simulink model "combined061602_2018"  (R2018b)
settings: Solver=ode5  StartTime=0.0  StopTime=inf  FixedStep=1e-5  RelTol=1e-3
libraries: powerlib x156, powerlib_meascontrol x64, simulink x32, dspsigops x2
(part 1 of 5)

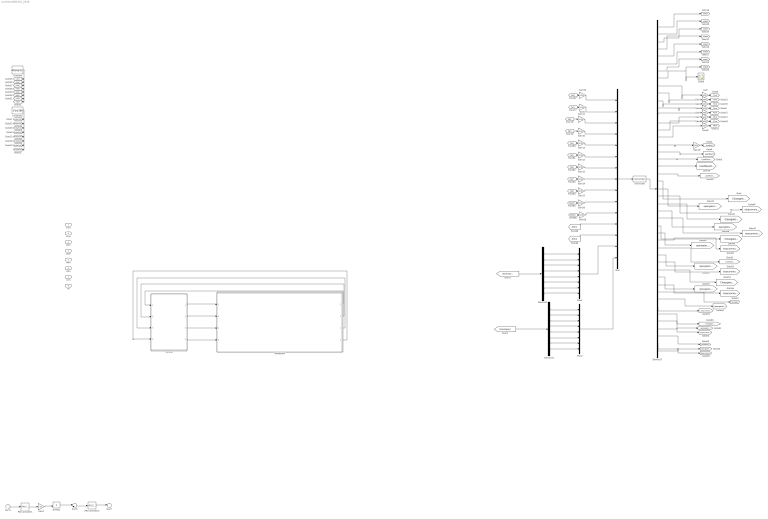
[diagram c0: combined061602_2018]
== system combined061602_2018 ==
  P1in : Inport
  P2in : Inport  Port=2
  Q1in : Inport  Port=3
  Q2in : Inport  Port=4
  vain : Inport  Port=5
  vbin : Inport  Port=6
  vcin : Inport  Port=7
  fin : Inport  Port=8
  Constant : Constant  Value=400/sqrt(3)
  Constant1 : Constant  Value=1*pi/180
  Control : Subsystem
  Demux15 : Demux  Outputs=8
  Demux16 : Demux  Outputs=8
  Demux17 : Demux  Outputs=45
  Divide1 : Product  Commented=on  Inputs=/*
  Gain{,3..9,19} (9 alike) : Gain  Gain=1000
  Gain1 : Gain  Commented=on  Gain=-2/3
  Gain{2,10..18,30} (11 alike) : Gain  Gain=1/1000  OutDataTypeStr=double
  Mux : Mux  Inputs=15
  Mux1 : Mux  Inputs=8
  Mux2 : Mux  Inputs=8
  PID Controller1 : simulink/Continuous/PID Controller  Commented=on  Controller=PI  Form=Parallel  TimeDomain=Continuous-time  SampleTime=-1  IntegratorMethod=Forward Euler  FilterMethod=Forward Euler  ControllerParametersSource=internal  P=1  I=1  D=0  UseFilter=on  N=100  TunerSelectOption=Transfer Function Based (PID Tuner App)  InitialConditionSource=internal  InitialConditionForIntegrator=0  InitialConditionForFilter=0  DifferentiatorICPrevScaledInput=0  ExternalReset=none  TrackingMode=off  Kt=1  LimitOutput=off  UpperSaturationLimit=inf  LowerSaturationLimit=-inf  LinearizeAsGain=on  AntiWindupMode=none  Kb=1  POutMin=[]  POutMax=[]  IOutMin=[]  IOutMax=[]  DOutMin=[]  DOutMax=[]  NOutMin=[]  NOutMax=[]  SumOutMin=[]  SumOutMax=[]  SaturationOutMin=[]  SaturationOutMax=[]  PParamMin=[]  PParamMax=[]  IParamMin=[]  IParamMax=[]  DParamMin=[]  DParamMax=[]  NParamMin=[]  NParamMax=[]  KbParamMin=[]  KbParamMax=[]  KtParamMin=[]  KtParamMax=[]  KbOutMin=[]  KbOutMax=[]  KtOutMin=[]  KtOutMax=[]  IntegratorOutMin=[]  IntegratorOutMax=[]  FilterOutMin=[]  FilterOutMax=[]  SumI1OutMin=[]  SumI1OutMax=[]  SumI2OutMin=[]  SumI2OutMax=[]  SumI3OutMin=[]  SumI3OutMax=[]  SumI4OutMin=[]  SumI4OutMax=[]  SumDOutMin=[]  SumDOutMax=[]  DifferentiatorOutMin=[]  DifferentiatorOutMax=[]  FilterDiffOutCoefMin=[]  FilterDiffOutCoefMax=[]  ReciprocalOutMin=[]  ReciprocalOutMax=[]  SumDenOutMin=[]  SumDenOutMax=[]  SumNumOutMin=[]  SumNumOutMax=[]  DivideOutMin=[]  DivideOutMax=[]  IntegratorContinuousStateAttributes=''  IntegratorStateMustResolveToSignalObject=off  IntegratorRTWStateStorageClass=Auto  FilterContinuousStateAttributes=''  FilterStateMustResolveToSignalObject=off  FilterRTWStateStorageClass=Auto  ParallelPVariant=InternalParameters  IdealPVariant=Disabled  IVariant=InternalParameters  DVariant=Disabled  IntegratorVariant=Continuous  SatVariant=Disabled  AWVariant=Passthrough  PCopyVariant=Disabled  TRVariant=Disabled  FdbkBlocksVariant=Forward  IdealPFdbkVariant=Disabled  SatFdbkVariant=Disabled  DerivativeFilterVariant=Disabled  NVariant=Disabled  NCopyVariant=Disabled_SignalSpec  FilterICVariant=Disabled  IntegratorICVariant=InternalICs  ExternalResetVariant=Disabled  TRSumVariant=Passthrough  SumFdbkVariant=Disabled  SumVariant=Sum_PI
  PID Controller3 : simulink/Continuous/PID Controller  Commented=on  Controller=PI  Form=Parallel  TimeDomain=Continuous-time  SampleTime=-1  IntegratorMethod=Forward Euler  FilterMethod=Forward Euler  ControllerParametersSource=internal  P=1  I=1  D=0  UseFilter=on  N=100  TunerSelectOption=Transfer Function Based (PID Tuner App)  InitialConditionSource=internal  InitialConditionForIntegrator=0  InitialConditionForFilter=0  DifferentiatorICPrevScaledInput=0  ExternalReset=none  TrackingMode=off  Kt=1  LimitOutput=off  UpperSaturationLimit=inf  LowerSaturationLimit=-inf  LinearizeAsGain=on  AntiWindupMode=none  Kb=1  POutMin=[]  POutMax=[]  IOutMin=[]  IOutMax=[]  DOutMin=[]  DOutMax=[]  NOutMin=[]  NOutMax=[]  SumOutMin=[]  SumOutMax=[]  SaturationOutMin=[]  SaturationOutMax=[]  PParamMin=[]  PParamMax=[]  IParamMin=[]  IParamMax=[]  DParamMin=[]  DParamMax=[]  NParamMin=[]  NParamMax=[]  KbParamMin=[]  KbParamMax=[]  KtParamMin=[]  KtParamMax=[]  KbOutMin=[]  KbOutMax=[]  KtOutMin=[]  KtOutMax=[]  IntegratorOutMin=[]  IntegratorOutMax=[]  FilterOutMin=[]  FilterOutMax=[]  SumI1OutMin=[]  SumI1OutMax=[]  SumI2OutMin=[]  SumI2OutMax=[]  SumI3OutMin=[]  SumI3OutMax=[]  SumI4OutMin=[]  SumI4OutMax=[]  SumDOutMin=[]  SumDOutMax=[]  DifferentiatorOutMin=[]  DifferentiatorOutMax=[]  FilterDiffOutCoefMin=[]  FilterDiffOutCoefMax=[]  ReciprocalOutMin=[]  ReciprocalOutMax=[]  SumDenOutMin=[]  SumDenOutMax=[]  SumNumOutMin=[]  SumNumOutMax=[]  DivideOutMin=[]  DivideOutMax=[]  IntegratorContinuousStateAttributes=''  IntegratorStateMustResolveToSignalObject=off  IntegratorRTWStateStorageClass=Auto  FilterContinuousStateAttributes=''  FilterStateMustResolveToSignalObject=off  FilterRTWStateStorageClass=Auto  ParallelPVariant=InternalParameters  IdealPVariant=Disabled  IVariant=InternalParameters  DVariant=Disabled  IntegratorVariant=Continuous  SatVariant=Disabled  AWVariant=Passthrough  PCopyVariant=Disabled  TRVariant=Disabled  FdbkBlocksVariant=Forward  IdealPFdbkVariant=Disabled  SatFdbkVariant=Disabled  DerivativeFilterVariant=Disabled  NVariant=Disabled  NCopyVariant=Disabled_SignalSpec  FilterICVariant=Disabled  IntegratorICVariant=InternalICs  ExternalResetVariant=Disabled  TRSumVariant=Passthrough  SumFdbkVariant=Disabled  SumVariant=Sum_PI
  S-Function : S-Function  FunctionName=modbusComPLCC  SFunctionDeploymentMode=off  EnableBusSupport=off
  Scope : Scope
  Subsystem : Subsystem
  Sum1 : Sum  Commented=on  Inputs=|+-
  Sum5 : Sum  Commented=on  Inputs=|+-
  Sum7 : Sum  Commented=on  Inputs=|++
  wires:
  Demux17/5 -> [enble5]
  Demux17/6 -> [enble6]
  Constant/1 -> [v1ref], [v2ref], [v3ref], [v4ref], [v5ref], [v6ref], [v7ref], [v8ref]
  Constant1/1 -> [theta1ref], [theta2ref], [theta3ref], [theta4ref], [theta5ref], [theta6ref], [theta8ref], [theta7ref]
  Demux17/4 -> [enble4]
  Sum5/1 -> PID Controller3/1
  Demux17/2 -> [enble2]
  Demux17/8 -> Scope/1, [enble8]
  Divide1/1 -> Sum5/1
  Demux17/3 -> [enble3]
  Demux17/1 -> [enble1]
  PID Controller3/1 -> Sum7/1
  Gain1/1 -> Divide1/2
  Sum1/1 -> PID Controller1/1
  PID Controller1/1 -> Gain1/1
  Q2in/1 -> ?
  P2in/1 -> ?
  Q1in/1 -> ?
  P1in/1 -> ?
  Control/1(P1out) -> Subsystem/1(P1ref2)
  Control/2(Q1out) -> Subsystem/2(Q1ref1)
  Control/3(P2out) -> Subsystem/3(P2ref)
  Control/4(Q2out) -> Subsystem/4(Q2ref)
  vain/1 -> ?
  vbin/1 -> ?
  fin/1 -> ?
  vcin/1 -> ?
  Subsystem/1(vaout) -> Control/1(vain)
  Subsystem/2(vbout) -> Control/2(vbin)
  Subsystem/3(vcout) -> Control/3(vcin)
  Subsystem/4(fout) -> Control/4(fin)
  Demux17/39 -> [stopcommand6]
  Demux17/37 -> [Closegatecommand6]
  Demux17/41 -> [opengatecommand7]
  Demux17/42 -> [stopcommand7]
  Demux17/40 -> [Closegatecommand7]
  [StartEnable] -> Demux15/1
  Demux16/2 -> Mux2/2
  Demux16/3 -> Mux2/3
  Demux16/1 -> Mux2/1
  Demux16/4 -> Mux2/4
  Demux16/5 -> Mux2/5
  Demux16/8 -> Mux2/8
  [RatedSpeed] -> Demux16/1
  Gain/1 -> [P1ref]
  Demux17/9 -> Gain/1
  Gain3/1 -> [P2ref]
  Gain4/1 -> [P3ref]
  Gain5/1 -> [P4ref]
  Gain6/1 -> [P5ref]
  Gain7/1 -> [P6ref]
  Gain8/1 -> [P7ref]
  Gain9/1 -> [P8ref]
  Demux17/16 -> Gain9/1
  Demux17/15 -> Gain8/1
  Demux17/14 -> Gain7/1
  Demux17/13 -> Gain6/1
  Demux17/12 -> Gain5/1
  Demux17/11 -> Gain4/1
  Demux17/10 -> Gain3/1
  [Pgt600] -> Gain18/1
  [Pgt400] -> Gain16/1
  [Pgt8] -> Gain17/1
  [Pgt7] -> Gain14/1
  [Pgt6] -> Gain15/1
  [Pgt5] -> Gain12/1
  [Pgt4] -> Gain13/1
  [Pgt3] -> Gain10/1
  [Pgt2] -> Gain11/1
  [Pgt1] -> Gain2/1
  [Pgt0] -> Gain30/1
  Gain30/1 -> Mux/1
  Gain2/1 -> Mux/2
  Gain11/1 -> Mux/3
  Gain10/1 -> Mux/4
  Gain13/1 -> Mux/5
  Gain12/1 -> Mux/6
  Gain15/1 -> Mux/7
  Gain14/1 -> Mux/8
  Gain17/1 -> Mux/9
  Gain16/1 -> Mux/10
  Gain18/1 -> Mux/11
  [SOC2] -> Mux/13
  [SOC1] -> Mux/12
  Mux1/1 -> Mux/14
  Mux2/1 -> Mux/15
  Mux/1 -> S-Function/1
  Demux17/43 -> [Closegatecommand8]
  Demux17/44 -> [opengatecommand8]
  Demux17/45 -> [stopcommand8]
  Demux17/38 -> [opengatecommand6]
  Demux17/34 -> [Closegatecommand5]
  Demux17/35 -> [opengatecommand5]
  Demux17/36 -> [stopcommand5]
  Demux17/32 -> [opengatecommand4]
  Demux17/31 -> [Closegatecommand4]
  Demux17/33 -> [stopcommand4]
  Demux17/29 -> [opengatecommand3]
  Demux17/28 -> [Closegatecommand3]
  Demux17/30 -> [stopcommand3]
  Demux17/25 -> [Closegatecommand2]
  Demux17/26 -> [opengatecommand2]
  Demux17/27 -> [stopcommand2]
  Demux17/23 -> [opengatecommand1]
  Demux17/24 -> [stopcommand1]
  Demux17/22 -> [Closegatecommand1]
  Demux17/17 -> Gain19/1
  Demux17/18 -> [LoadQset]
  Demux17/19 -> [LoadFactorySet]
  Demux17/20 -> [LoadSpeedSet]
  Demux17/21 -> [LoadTchangeSet]
  Demux17/7 -> [enble7]
  Demux16/6 -> Mux2/6
  Demux16/7 -> Mux2/7
  Demux15/1 -> Mux1/1
  Demux15/2 -> Mux1/2
  Demux15/3 -> Mux1/3
  Demux15/4 -> Mux1/4
  Demux15/5 -> Mux1/5
  Demux15/6 -> Mux1/6
  Demux15/7 -> Mux1/7
  Demux15/8 -> Mux1/8
  S-Function/1 -> Demux17/1
  Gain19/1 -> [LoadPset]

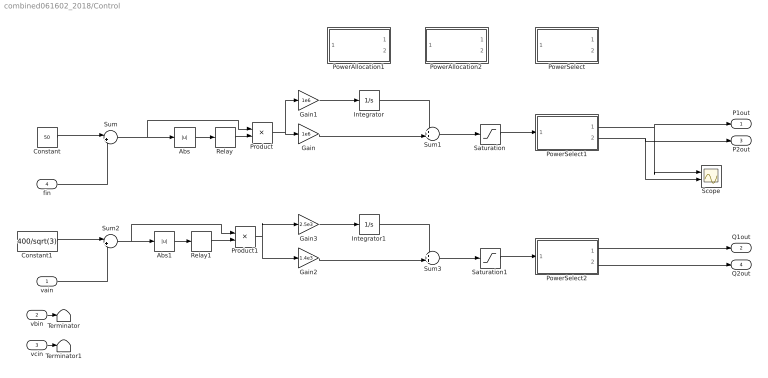
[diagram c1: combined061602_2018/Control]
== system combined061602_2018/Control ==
  vain : Inport
  vbin : Inport  Port=2
  vcin : Inport  Port=3
  fin : Inport  Port=4
  Abs : Abs
  Abs1 : Abs
  Constant : Constant  Value=50
  Constant1 : Constant  Value=400/sqrt(3)
  Gain : Gain  Gain=1e6
  Gain1 : Gain  Gain=1e6
  Gain2 : Gain  Gain=1.4e3
  Gain3 : Gain  Gain=2.5e3
  Integrator : Integrator
  Integrator1 : Integrator
  PowerAllocation1 : Subsystem  Commented=on
  PowerAllocation2 : Subsystem  Commented=on
  PowerSelect : Subsystem  Commented=on
  PowerSelect1 : Subsystem
  PowerSelect2 : Subsystem
  Product : Product
  Product1 : Product
  Relay : Relay  OnSwitchValue=0  OffSwitchValue=0
  Relay1 : Relay  OnSwitchValue=0  OffSwitchValue=0
  Saturation : Saturate  UpperLimit=1e6  LowerLimit=-1e6
  Saturation1 : Saturate  UpperLimit=5e5  LowerLimit=-5e5
  Scope : Scope  NumInputPorts=2
  Sum : Sum  Inputs=|+-
  Sum1 : Sum  Inputs=++|
  Sum2 : Sum  Inputs=|+-
  Sum3 : Sum  Inputs=++|
  Terminator : Terminator
  Terminator1 : Terminator
  P1out : Outport
  Q1out : Outport  Port=2
  P2out : Outport  Port=3
  Q2out : Outport  Port=4
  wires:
  PowerSelect2/1(P1) -> Q1out/1
  Integrator/1 -> Sum1/1
  PowerSelect1/1(P1) -> P1out/1, Scope/1
  Product1/1 -> Gain2/1, Gain3/1
  Integrator1/1 -> Sum3/1
  Gain3/1 -> Integrator1/1
  Sum1/1 -> Saturation/1
  Sum3/1 -> Saturation1/1
  Constant1/1 -> Sum2/1
  Gain1/1 -> Integrator/1
  Gain2/1 -> Sum3/2
  fin/1 -> Sum/2
  Saturation1/1 -> PowerSelect2/1(PAll)
  Gain/1 -> Sum1/2
  Product/1 -> Gain1/1, Gain/1
  vain/1 -> Sum2/2
  Saturation/1 -> PowerSelect1/1(PAll)
  vbin/1 -> Terminator/1
  vcin/1 -> Terminator1/1
  PowerSelect1/2(P2) -> P2out/1, Scope/2
  PowerSelect2/2(P2) -> Q2out/1
  Sum/1 -> Abs/1, Product/1
  Constant/1 -> Sum/1
  Relay/1 -> Product/2
  Abs/1 -> Relay/1
  Relay1/1 -> Product1/2
  Abs1/1 -> Relay1/1
  Sum2/1 -> Abs1/1, Product1/1

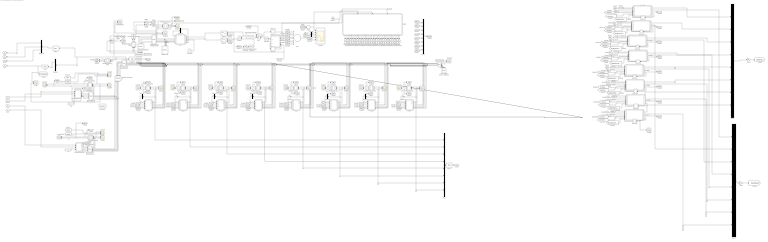
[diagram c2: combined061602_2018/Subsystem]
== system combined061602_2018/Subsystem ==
  P1ref2 : Inport
  Q1ref1 : Inport  Port=2
  P2ref : Inport  Port=3
  Q2ref : Inport  Port=4
  150kW Load : powerlib/Elements/Three-Phase Series RLC Load  LConnTagsString=A|B|C  Configuration=Y (grounded)  NominalVoltage=600  Vabc=[1e3 1e3 1e3]  Vabcp=[1e3 1e3 1e3]  NominalFrequency=50  UnbalancedPower=off  ActivePower=300e3  InductivePower=0  CapacitivePower=0  Pabc=[10e3 9e3 11e3]  QLabc=[100 90 110]  QCabc=[100 90 110]  Pabcp=[10e3 9e3 11e3]  QLabcp=[100 90 110]  QCabcp=[100 90 110]  Measurements=None  LoadType=constant Z
  400V/600V母线1 : Scope  NumInputPorts=2
  Add : Sum  Inputs=++++++++
  Add1 : Sum
  Clock{1..9} (9 alike) : Clock
  Constant2 : Constant
  Demux{1..2,10..19} (12 alike) : Demux  Outputs=3
  Gain : Gain  Gain=-1
  Gain1 : Gain  OutDataTypeStr=double
  Gain2 : Gain  OutDataTypeStr=double
  Gen FSM : MATLAB Function  TreatAsAtomicUnit=on
  Gen FSM1 : MATLAB Function  TreatAsAtomicUnit=on
  Gen FSM2 : MATLAB Function  TreatAsAtomicUnit=on
  Gen FSM3 : MATLAB Function  TreatAsAtomicUnit=on
  Gen FSM4 : MATLAB Function  TreatAsAtomicUnit=on
  Gen FSM5 : MATLAB Function  TreatAsAtomicUnit=on
  Gen FSM6 : MATLAB Function  TreatAsAtomicUnit=on
  Gen FSM7 : MATLAB Function  TreatAsAtomicUnit=on
  Isolation Transformer1 : powerlib/Elements/Three-Phase Transformer (Two Windings)  Winding1Connection=Yg  Winding2Connection=Yg  CoreType=Three single-phase transformers  SetSaturation=off  Hysteresis=off  DataFile='hysteresis'  SetInitialFlux=off  Measurements=None  UNITS=pu  NominalPower=[ 2000e3 , 50 ]  Winding1=[ 400 , 0.001 , 0.00 ]  Winding2=[ 400 , 0.001 , 0.05 ]  Rm=inf  Lm=inf  L0=0.5  Saturation=[ 0,0 ; 0.0024,1.2 ; 1.0,1.52 ]  InitialFluxes=[ 0.8 , -0.8 , 0.7 ]  MoreParameters=off  BreakLoop=off  DataType=off  TransfoNumber=1
  Load1 : Subsystem
  MATLAB Function1 : MATLAB Function  TreatAsAtomicUnit=on
  MGCC1 : MATLAB Function  Commented=on  TreatAsAtomicUnit=on
  MT_1 : Subsystem
  MT_10 : Subsystem
  MT_11 : Subsystem
  MT_12 : Subsystem
  MT_13 : Subsystem
  MT_14 : Subsystem
  MT_15 : Subsystem
  MT_9 : Subsystem
  Memory : Memory
  Memory1 : Memory
  Memory{2..9} (8 alike) : Memory  InitialCondition=[0 0 1 0 0]'
  Mux{,1..3} (4 alike) : Mux  Inputs=8
  PLL2 : powerlib_meascontrol/PLL/PLL  Fmin=45  Par_Init=[0, 50]  ParK=[100, 3200, 1]  TcD=1e-4  MaxRateChangeFreq=12  FilterCutOffFreq=25  Ts=0  AGC=on
  PQ Measurement_Load1 : Subsystem
  PQ Measurement_Load2 : Subsystem
  PQ Measurement_M10 : Subsystem
  PQ Measurement_M11 : Subsystem
  PQ Measurement_M12 : Subsystem
  PQ Measurement_M13 : Subsystem
  PQ Measurement_M14 : Subsystem
  PQ Measurement_M15 : Subsystem
  PQ Measurement_M16 : Subsystem
  PQ Measurement_M9 : Subsystem
  PQ Measurement_PCS1 : Subsystem
  PQ Measurement_PCS2 : Subsystem
  PQ Measurement_PCS3 : Subsystem
  Product : Product
  RMS{1..6,8} (7 alike) : powerlib_meascontrol/Measurements/RMS  TrueRMS=on  Freq=50  RMSInit=400/sqrt(3)  Ts=0
  Rate Limiter Dynamic : simulink/Discontinuities/Rate Limiter Dynamic
  Saturation : Saturate  UpperLimit=2500e3  LowerLimit=-1000e3
  Scope{,1..2,27..32,34..43,46..47,49..50,52} (24 alike) : Scope  NumInputPorts=2
  Scope3 : Scope  NumInputPorts=3
  Scope33 : Scope  NumInputPorts=6
  Scope4 : Scope
  Scope48 : Scope  NumInputPorts=3
  Storage Batteries3 : Subsystem
  Storage Batteries4 : Subsystem
  Switch : Switch  Criteria=u2 ~= 0
  Switch1 : Switch  Criteria=u2 ~= 0
  Three-Phase Series RLC Load Balance1 : powerlib/Elements/Three-Phase Series RLC Load  LConnTagsString=A|B|C  Configuration=Y (grounded)  NominalVoltage=0.40e3  Vabc=[1e3 1e3 1e3]  Vabcp=[1e3 1e3 1e3]  NominalFrequency=50  UnbalancedPower=off  ActivePower=10  InductivePower=0  CapacitivePower=0  Pabc=[10e3 9e3 11e3]  QLabc=[100 90 110]  QCabc=[100 90 110]  Pabcp=[10e3 9e3 11e3]  QLabcp=[100 90 110]  QCabcp=[100 90 110]  Measurements=None  LoadType=constant Z
  Three-Phase V-I Measurement{1..2,6..9} (6 alike) : powerlib/Measurements/Three-Phase V-I Measurement  VoltageMeasurement=phase-to-ground  SetLabelV=off  LabelV=Vabc  Vpu=off  VpuLL=off  CurrentMeasurement=yes  SetLabelI=off  LabelI=Iabc  Ipu=off  Pbase=100e6  Vbase=500e3  OutputType=Complex  PhasorSimulation=off  PSBequivalent=0
  Trigonometric Function : Trigonometry  Operator=acos
  Trigonometric Function1 : Trigonometry  Operator=tan
  Up-step Transformer1 : powerlib/Elements/Three-Phase Transformer (Two Windings)  Winding1Connection=Yg  Winding2Connection=Yg  CoreType=Three single-phase transformers  SetSaturation=off  Hysteresis=off  DataFile='hysteresis'  SetInitialFlux=off  Measurements=None  UNITS=pu  NominalPower=[ 4000e3 , 50 ]  Winding1=[ 400 , 0.001 , 0.00 ]  Winding2=[ 600 , 0.001 , 0.05 ]  Rm=inf  Lm=inf  L0=0.5  Saturation=[ 0,0 ; 0.0024,1.2 ; 1.0,1.52 ]  InitialFluxes=[ 0.8 , -0.8 , 0.7 ]  MoreParameters=off  BreakLoop=off  DataType=off  TransfoNumber=1
  fn1 : Constant
  fn2 : Constant
  powergui1 : powerlib/powergui  Priority=1  SimulationMode=Discrete  SampleTime=50e-6  frequency=60  Iterations=50  frequencyindice=0  Pbase=15e6  ErrMax=0.0001  UnitsV=V  UnitsW=MW  buscounter=0  FunctionMessages=off  echomessages=off  EnableUseOfTLC=off  CurrentSourceSwitches=off  DisableSnubberDevices=off  DisableRonSwitches=off  DisableVfSwitches=off  DisplayEquations=off  SolverType=Tustin/Backward Euler (TBE)  Interpol=off  ExternalGateDelay=off  methode=off  Ts=100  x0status=blocks  SPID=off  SwTol=0  HookPort=off  RestoreLinks=warning  ResistiveCurrentMeasurement=off  Frange=[0:2:500]  Ylog=off  Xlog=on  ShowGrid=off  save=off  variable=ZData  structure=0  ZoomFFT=off  StartTime=0.0  cycles=1  DisplayStyle=1  fundamental=60  FreqAxis=off  MaxFrequency=1000  frequencyindicesteady=1  RmsSteady=1  display=off
  vaout : Outport
  vbout : Outport  Port=2
  vcout : Outport  Port=3
  fout : Outport  Port=4
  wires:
  PQ Measurement_M14/2(Q) -> [Qgt6], Scope37/2  "燃机Q"
  PQ Measurement_M11/1(P) -> [Pgt3], Scope30/1  "燃机P"
  MT_14/2(Vabc) -> PQ Measurement_M14/1(Vabc), Scope39/1, Demux16/1
  PQ Measurement_M15/1(P) -> [Pgt7], Scope40/1  "燃机P"
  [v7ref] -> MT_15/3(Vref)
  Demux17/1 -> MT_15/1(Vt_a)
  [Udg2] -> Scope3/2
  Demux19/3 -> vcout/1
  Three-Phase V-I Measurement1/1 -> Scope2/1, Scope3/1, PQ Measurement_PCS1/1(Vabc)
  MGCC1/25(P7ref) -> [P7ref]
  Demux16/1 -> MT_14/1(Vt_a)
  MGCC1/7(enable2) -> [enble2]
  MT_15/1(Iabc) -> Scope41/2, PQ Measurement_M15/2(Iabc), Mux/7
  Three-Phase V-I Measurement9/1 -> Scope38/1
  Three-Phase V-I Measurement1/2 -> Scope2/2, PQ Measurement_PCS1/2(Iabc)
  Three-Phase V-I Measurement7/1 -> PQ Measurement_PCS3/1(Vabc), 400V/600V母线1/1, Demux1/1, RMS1/1
  PQ Measurement_PCS1/1(P) -> Scope1/1, [Pbat2]  "储能P"
  [v3ref] -> MT_11/3(Vref)
  MGCC1/26(theta7ref) -> [theta7ref]
  PQ Measurement_M16/2(Q) -> [Qgt8], Scope42/2  "燃机Q"
  MT_11/1(Iabc) -> Mux/3, Scope31/2, PQ Measurement_M11/2(Iabc)
  MT_12/2(Vabc) -> PQ Measurement_M12/1(Vabc), Scope34/1, Demux14/1
  Clock1/1 -> MATLAB Function1/1(clock), MGCC1/1(clock)
  Demux12/1 -> MT_10/1(Vt_a)
  Load1/1(Vabc) -> Demux10/1
  MGCC1/24(v6ref) -> [v6ref]
  PQ Measurement_M13/1(P) -> [Pgt5], Scope35/1  "燃机P"
  MGCC1/30(theta8ref) -> [theta8ref]
  MGCC1/13(P4ref) -> [P4ref]
  [v8ref] -> MT_1/3(Vref)
  PQ Measurement_M9/2(Q) -> [Qgt1], Scope49/2  "燃机Q"
  PQ Measurement_M10/1(P) -> [Pgt2], Scope28/1  "燃机P"
  PQ Measurement_PCS1/2(Q) -> [Qbat2], Scope1/2  "储能Q"
  PQ Measurement_M14/1(P) -> [Pgt6], Scope37/1  "燃机P"
  [freqdg2] -> Scope3/3
  MT_15/2(Vabc) -> Demux17/1, Scope41/1, PQ Measurement_M15/1(Vabc)
  MGCC1/21(P6ref) -> [P6ref]
  MGCC1/8(v2ref) -> [v2ref]
  MGCC1/10(theta3ref) -> [theta3ref]
  MT_9/2(Vabc) -> Demux11/1, Scope52/1, PQ Measurement_M9/1(Vabc)
  Saturation/1 -> Rate Limiter Dynamic/2, Memory1/1
  [v5ref] -> MT_13/3(Vref)
  Storage Batteries4/1(SOC) -> [SOC2]
  PQ Measurement_M11/2(Q) -> [Qgt3], Scope30/2  "燃机Q"
  MGCC1/3(enable1) -> [enble1]
  MGCC1/23(enable6) -> [enble6]
  MT_1/2(Vabc) -> PQ Measurement_M16/1(Vabc), Scope43/1, Demux18/1
  Add1/1 -> Scope33/1, MGCC1/2(p_bat)
  PQ Measurement_M9/1(P) -> [Pgt1], Scope49/1  "燃机P"
  [v1ref] -> MT_9/3(Vref)
  Demux13/1 -> MT_11/1(Vt_a)
  PQ Measurement_M12/1(P) -> [Pgt4], Scope32/1  "燃机P"
  PQ Measurement_M12/2(Q) -> [Qgt4], Scope32/2  "燃机Q"
  MGCC1/27(enable7) -> [enble7]
  MT_10/1(Iabc) -> Mux/2, PQ Measurement_M10/2(Iabc), Scope29/2
  Three-Phase V-I Measurement8/1 -> PQ Measurement_PCS2/1(Vabc), Scope48/1, Scope/2, Scope47/1
  MT_13/2(Vabc) -> Demux15/1, Scope36/1, PQ Measurement_M13/1(Vabc)
  Three-Phase V-I Measurement6/1 -> RMS5/1, PQ Measurement_Load1/1(Vabc), 400V/600V母线1/2, Scope46/1
  MGCC1/1(P1ref) -> [P1ref]
  [theta3ref] -> MT_11/4(theta(rad))
  MT_10/2(Vabc) -> PQ Measurement_M10/1(Vabc), Scope29/1, Demux12/1
  PLL2/1 -> Scope/1, [Frequency], fout/1
  MGCC1/18(theta5ref) -> [theta5ref]
  MGCC1/22(theta6ref) -> [theta6ref]
  MT_12/1(Iabc) -> Mux/4, PQ Measurement_M12/2(Iabc), Scope34/2
  Demux11/1 -> MT_9/1(Vt_a)
  Three-Phase V-I Measurement6/2 -> RMS6/1, PQ Measurement_Load1/2(Iabc), Scope46/2
  [theta7ref] -> MT_15/4(theta(rad))
  Constant2/1 -> Load1/3(active)
  MGCC1/9(P3ref) -> [P3ref]
  PQ Measurement_M15/2(Q) -> [Qgt7], Scope40/2  "燃机Q"
  PQ Measurement_M16/1(P) -> [Pgt8], Scope42/1  "燃机P"
  MGCC1/11(enable3) -> [enble3]
  MGCC1/17(P5ref) -> [P5ref]
  PQ Measurement_PCS2/1(P) -> [Pbat1], Scope27/1  "储能P"
  [theta8ref] -> MT_1/4(theta(rad))
  Demux15/1 -> MT_13/1(Vt_a)
  MGCC1/14(theta4ref) -> [theta4ref]
  [freqdg1] -> Scope48/3
  [P8ref] -> MT_1/2(Pref)
  MT_14/1(Iabc) -> PQ Measurement_M14/2(Iabc), Scope39/2, Mux/6
  PQ Measurement_PCS2/2(Q) -> [Qbat1], Scope27/2  "储能Q"
  PQ Measurement_M13/2(Q) -> [Qgt5], Scope35/2  "燃机Q"
  [P7ref] -> MT_15/2(Pref)
  Demux18/1 -> MT_1/1(Vt_a)
  [v2ref] -> MT_10/3(Vref)
  [v4ref] -> MT_12/3(Vref)
  Three-Phase V-I Measurement8/2 -> PQ Measurement_PCS2/2(Iabc), Scope47/2
  [v6ref] -> MT_14/3(Vref)
  MGCC1/5(P2ref) -> [P2ref]
  MT_11/2(Vabc) -> Demux13/1, Scope31/1, PQ Measurement_M11/1(Vabc)
  MGCC1/4(v1ref) -> [v1ref]
  [P5ref] -> MT_13/2(Pref)
  [Udg1] -> Scope48/2
  MGCC1/16(v4ref) -> [v4ref]
  MGCC1/19(enable5) -> [enble5]
  Demux14/1 -> MT_12/1(Vt_a)
  [theta4ref] -> MT_12/4(theta(rad))
  Three-Phase V-I Measurement9/2 -> Scope38/2
  MT_1/1(Iabc) -> Mux/8, PQ Measurement_M16/2(Iabc), Scope43/2
  MGCC1/32(v8ref) -> [v8ref]
  [theta1ref] -> MT_9/4(theta(rad))
  MGCC1/31(enable8) -> [enble8]
  MGCC1/20(v5ref) -> [v5ref]
  MT_9/1(Iabc) -> Mux/1, Scope52/2, PQ Measurement_M9/2(Iabc)
  MT_13/1(Iabc) -> Mux/5, Scope36/2, PQ Measurement_M13/2(Iabc)
  Demux10/1 -> Load1/4(Vt_a)
  MGCC1/28(v7ref) -> [v7ref]
  MGCC1/6(theta2ref) -> [theta2ref]
  MGCC1/2(theta1ref) -> [theta1ref]
  [theta6ref] -> MT_14/4(theta(rad))
  MGCC1/12(v3ref) -> [v3ref]
  MGCC1/29(P8ref) -> [P8ref]
  [theta5ref] -> MT_13/4(theta(rad))
  Demux19/2 -> vbout/1
  MGCC1/15(enable4) -> [enble4]
  [theta2ref] -> MT_10/4(theta(rad))
  RMS1/1 -> Demux19/1
  Storage Batteries3/1(SOC) -> [SOC1]
  Demux19/1 -> vaout/1
  P1ref2/1 -> Storage Batteries3/1(Pref)
  Q1ref1/1 -> Storage Batteries3/2(Qref)
  Q2ref/1 -> Storage Batteries4/2(Qref)
  P2ref/1 -> Storage Batteries4/1(Pref)
  Demux1/1 -> PLL2/1
  [P6ref] -> MT_14/2(Pref)
  [Active5] -> MT_13/5(Active)
  [P4ref] -> MT_12/2(Pref)
  [Active2] -> MT_10/5(Active)
  [Active4] -> MT_12/5(Active)
  [Active3] -> MT_11/5(Active)
  [P3ref] -> MT_11/2(Pref)
  [P1ref] -> MT_9/2(Pref)
  [Active6] -> MT_14/5(Active)
  [P2ref] -> MT_10/2(Pref)
  [Active8] -> MT_1/5(Active)
  [Active7] -> MT_15/5(Active)
  [Active1] -> MT_9/5(Active)
  Three-Phase V-I Measurement2/2 -> RMS3/1, PQ Measurement_Load2/2(Iabc)
  Three-Phase V-I Measurement2/1 -> RMS4/1, PQ Measurement_Load2/1(Vabc)
  PQ Measurement_Load2/1(P) -> [Pgt400]
  PQ Measurement_Load2/2(Q) -> [Qgt400]
  PQ Measurement_M10/2(Q) -> [Qgt2], Scope28/2  "燃机Q"
  Three-Phase V-I Measurement7/2 -> RMS8/1, PQ Measurement_PCS3/2(Iabc)
  PQ Measurement_PCS3/1(P) -> [Pgt0]  "储能P"
  PQ Measurement_PCS3/2(Q) -> [Qgt0]  "储能Q"
  Storage Batteries3/2(RemainCap) -> [RemainCap1]
  Storage Batteries4/2(RemainCap) -> [RemainCap2]
  RMS8/1 -> [I0]
  Mux/1 -> RMS2/1
  RMS2/1 -> [IG]
  RMS3/1 -> [I400]
  RMS4/1 -> [U400]
  RMS5/1 -> [U600]
  RMS6/1 -> [I600]
  [Pgt1] -> Add/1
  [Pgt2] -> Add/2
  [Pgt3] -> Add/3
  [Pgt4] -> Add/4
  [Pgt5] -> Add/5
  [Pgt6] -> Add/6
  [Pgt7] -> Add/7
  [Pgt8] -> Add/8
  [Pbat1] -> Add1/1
  [Pbat2] -> Add1/2
  Add/1 -> Scope33/2
  [U400] -> Demux2/1
  [Frequency] -> Scope33/4
  [enble1] -> Mux1/1
  [enble2] -> Mux1/2
  [enble3] -> Mux1/3
  [enble4] -> Mux1/4
  [enble5] -> Mux1/5
  [enble6] -> Mux1/6
  [enble7] -> Mux1/7
  [enble8] -> Mux1/8
  Mux1/1 -> [Enable]
  [Enable] -> Scope33/5
  Demux2/1 -> Scope33/3
  MATLAB Function1/2(Tlast) -> Memory/1
  Memory1/1 -> MATLAB Function1/2(plast)
  Rate Limiter Dynamic/1 -> Switch/1, Product/1
  Memory/1 -> MATLAB Function1/3("Tlast ")
  MATLAB Function1/1(p) -> Saturation/1
  Product/1 -> Switch1/1
  Switch1/1 -> Load1/2(Q)
  Switch/1 -> Load1/1(P)
  [LoadTchangeSet] -> Switch1/2, Switch/2, MATLAB Function1/4(Tchange)
  [LoadSpeedSet] -> Gain/1, Rate Limiter Dynamic/1
  Gain/1 -> Rate Limiter Dynamic/3
  [LoadFactorySet] -> Trigonometric Function/1
  Trigonometric Function/1 -> Trigonometric Function1/1
  Trigonometric Function1/1 -> Product/2
  [LoadPset] -> Switch/3
  [LoadQset] -> Switch1/3
  [enble1] -> Gen FSM/1(StartCommand)
  Clock2/1 -> Gen FSM/2(clock)
  Gen FSM/3(Active) -> [Active1]
  Gen FSM1/3(Active) -> [Active2]
  Gen FSM5/3(Active) -> [Active6]
  Gen FSM4/3(Active) -> [Active5]
  Gen FSM6/3(Active) -> [Active7]
  Gen FSM7/1(StartEnable) -> Mux2/8
  Gen FSM7/2(RatedSpeed) -> Mux3/8
  Gen FSM7/3(Active) -> [Active8]
  Gen FSM3/3(Active) -> [Active4]
  Gen FSM2/3(Active) -> [Active3]
  Gen FSM/1(StartEnable) -> Mux2/1
  Gen FSM1/1(StartEnable) -> Mux2/2
  Gen FSM2/1(StartEnable) -> Mux2/3
  Gen FSM3/1(StartEnable) -> Mux2/4
  Gen FSM4/1(StartEnable) -> Mux2/5
  Gen FSM5/1(StartEnable) -> Mux2/6
  Gen FSM6/1(StartEnable) -> Mux2/7
  Gen FSM/2(RatedSpeed) -> Mux3/1
  Gen FSM1/2(RatedSpeed) -> Mux3/2
  Gen FSM2/2(RatedSpeed) -> Mux3/3
  Gen FSM3/2(RatedSpeed) -> Mux3/4
  Gen FSM4/2(RatedSpeed) -> Mux3/5
  Gen FSM5/2(RatedSpeed) -> Mux3/6
  Gen FSM6/2(RatedSpeed) -> Mux3/7
  Mux2/1 -> Gain1/1
  Gen FSM/4(memory) -> Memory2/1
  Memory2/1 -> Gen FSM/3("memory ")
  Gain1/1 -> [StartEnable]
  Mux3/1 -> Gain2/1
  Gain2/1 -> [RatedSpeed]
  fn2/1 -> Storage Batteries3/3(PQ2VF)
  fn1/1 -> Storage Batteries4/3(PQ2VF)
  [Pgt1] -> Gen FSM/4(p)
  [Closegatecommand1] -> Gen FSM/5(ClosegateCommand)
  [opengatecommand1] -> Gen FSM/6(OpengateCommand)
  [stopcommand1] -> Gen FSM/7(stopcommand)
  [opengatecommand2] -> Gen FSM1/6(OpengateCommand)
  [stopcommand2] -> Gen FSM1/7(stopcommand)
  [Pgt2] -> Gen FSM1/4(p)
  [Closegatecommand2] -> Gen FSM1/5(ClosegateCommand)
  Clock3/1 -> Gen FSM1/2(clock)
  Gen FSM1/4(memory) -> Memory3/1
  Memory3/1 -> Gen FSM1/3("memory ")
  [enble2] -> Gen FSM1/1(StartCommand)
  [opengatecommand3] -> Gen FSM2/6(OpengateCommand)
  [stopcommand3] -> Gen FSM2/7(stopcommand)
  [Pgt3] -> Gen FSM2/4(p)
  [Closegatecommand3] -> Gen FSM2/5(ClosegateCommand)
  Clock4/1 -> Gen FSM2/2(clock)
  Gen FSM2/4(memory) -> Memory4/1
  Memory4/1 -> Gen FSM2/3("memory ")
  [enble3] -> Gen FSM2/1(StartCommand)
  [opengatecommand4] -> Gen FSM3/6(OpengateCommand)
  [stopcommand4] -> Gen FSM3/7(stopcommand)
  [Pgt4] -> Gen FSM3/4(p)
  [Closegatecommand4] -> Gen FSM3/5(ClosegateCommand)
  Clock5/1 -> Gen FSM3/2(clock)
  Gen FSM3/4(memory) -> Memory5/1
  Memory5/1 -> Gen FSM3/3("memory ")
  [enble4] -> Gen FSM3/1(StartCommand)
  [opengatecommand5] -> Gen FSM4/6(OpengateCommand)
  [stopcommand5] -> Gen FSM4/7(stopcommand)
  [Pgt5] -> Gen FSM4/4(p)
  [Closegatecommand5] -> Gen FSM4/5(ClosegateCommand)
  Clock6/1 -> Gen FSM4/2(clock)
  Gen FSM4/4(memory) -> Memory6/1
  Memory6/1 -> Gen FSM4/3("memory ")
  [enble5] -> Gen FSM4/1(StartCommand)
  [opengatecommand6] -> Gen FSM5/6(OpengateCommand)
  [stopcommand6] -> Gen FSM5/7(stopcommand)
  [Pgt6] -> Gen FSM5/4(p)
  [Closegatecommand6] -> Gen FSM5/5(ClosegateCommand)
  Clock7/1 -> Gen FSM5/2(clock)
  Gen FSM5/4(memory) -> Memory7/1
  Memory7/1 -> Gen FSM5/3("memory ")
  [enble6] -> Gen FSM5/1(StartCommand)
  [opengatecommand7] -> Gen FSM6/6(OpengateCommand)
  [stopcommand7] -> Gen FSM6/7(stopcommand)
  [Pgt7] -> Gen FSM6/4(p)
  [Closegatecommand7] -> Gen FSM6/5(ClosegateCommand)
  Clock8/1 -> Gen FSM6/2(clock)
  Gen FSM6/4(memory) -> Memory8/1
  Memory8/1 -> Gen FSM6/3("memory ")
  [enble7] -> Gen FSM6/1(StartCommand)
  [opengatecommand8] -> Gen FSM7/6(OpengateCommand)
  [stopcommand8] -> Gen FSM7/7(stopcommand)
  [Pgt8] -> Gen FSM7/4(p)
  [Closegatecommand8] -> Gen FSM7/5(ClosegateCommand)
  Clock9/1 -> Gen FSM7/2(clock)
  Gen FSM7/4(memory) -> Scope4/1, Memory9/1
  Memory9/1 -> Gen FSM7/3("memory ")
  [enble8] -> Gen FSM7/1(StartCommand)
  PQ Measurement_Load1/2(Q) -> [Qgt600], Scope50/2
  PQ Measurement_Load1/1(P) -> [Pgt600], Scope50/1, MGCC1/3(p_load)
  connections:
  Three-Phase V-I Measurement1/LConn1 -- Storage Batteries4/RConn1
  MT_12/RConn1 -- MT_1/RConn1 -- Three-Phase V-I Measurement9/LConn1 -- MT_15/RConn1 -- MT_14/RConn1 -- MT_13/RConn1 -- MT_11/RConn1 -- MT_10/RConn1 -- Three-Phase V-I Measurement2/LConn1 -- Three-Phase V-I Measurement7/RConn1 -- MT_9/RConn1
  Storage Batteries4/RConn2 -- Three-Phase V-I Measurement1/LConn2
  Three-Phase V-I Measurement9/LConn2 -- MT_1/RConn2 -- MT_15/RConn2 -- MT_14/RConn2 -- MT_13/RConn2 -- MT_12/RConn2 -- MT_11/RConn2 -- MT_10/RConn2 -- Three-Phase V-I Measurement2/LConn2 -- Three-Phase V-I Measurement7/RConn2 -- MT_9/RConn2
  Storage Batteries4/RConn3 -- Three-Phase V-I Measurement1/LConn3
  MT_15/RConn3 -- MT_1/RConn3 -- Three-Phase V-I Measurement9/LConn3 -- MT_14/RConn3 -- MT_13/RConn3 -- MT_12/RConn3 -- MT_11/RConn3 -- MT_10/RConn3 -- Three-Phase V-I Measurement2/LConn3 -- Three-Phase V-I Measurement7/RConn3 -- MT_9/RConn3
  Three-Phase V-I Measurement9/RConn1 -- Three-Phase Series RLC Load Balance1/LConn1
  Three-Phase V-I Measurement1/RConn2 -- Isolation Transformer1/LConn2 -- Three-Phase V-I Measurement8/RConn2
  Three-Phase V-I Measurement1/RConn1 -- Isolation Transformer1/LConn1 -- Three-Phase V-I Measurement8/RConn1
  Up-step Transformer1/RConn1 -- Three-Phase V-I Measurement6/LConn1
  Three-Phase V-I Measurement1/RConn3 -- Isolation Transformer1/LConn3 -- Three-Phase V-I Measurement8/RConn3
  Isolation Transformer1/RConn2 -- Three-Phase V-I Measurement7/LConn2
  Storage Batteries3/RConn1 -- Three-Phase V-I Measurement8/LConn1
  Three-Phase V-I Measurement9/RConn2 -- Three-Phase Series RLC Load Balance1/LConn2
  Load1/RConn1 -- 150kW Load/LConn1 -- Three-Phase V-I Measurement6/RConn1
  Isolation Transformer1/RConn1 -- Three-Phase V-I Measurement7/LConn1
  Storage Batteries3/RConn2 -- Three-Phase V-I Measurement8/LConn2
  Up-step Transformer1/RConn2 -- Three-Phase V-I Measurement6/LConn2
  Load1/RConn2 -- 150kW Load/LConn2 -- Three-Phase V-I Measurement6/RConn2
  Load1/RConn3 -- 150kW Load/LConn3 -- Three-Phase V-I Measurement6/RConn3
  Storage Batteries3/RConn3 -- Three-Phase V-I Measurement8/LConn3
  Up-step Transformer1/RConn3 -- Three-Phase V-I Measurement6/LConn3
  Isolation Transformer1/RConn3 -- Three-Phase V-I Measurement7/LConn3
  Three-Phase V-I Measurement9/RConn3 -- Three-Phase Series RLC Load Balance1/LConn3
  Up-step Transformer1/LConn1 -- Three-Phase V-I Measurement2/RConn1
  Up-step Transformer1/LConn2 -- Three-Phase V-I Measurement2/RConn2
  Up-step Transformer1/LConn3 -- Three-Phase V-I Measurement2/RConn3

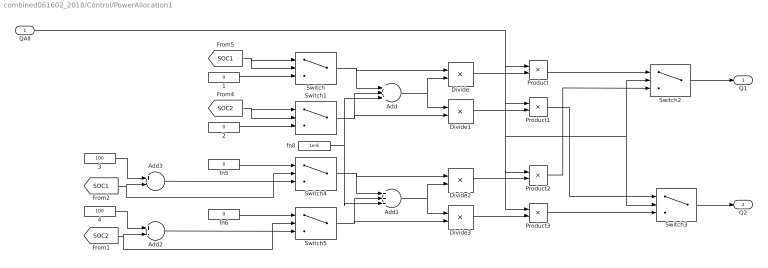
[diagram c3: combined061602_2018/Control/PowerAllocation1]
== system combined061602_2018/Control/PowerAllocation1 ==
  QAll : Inport
  1 : Constant  Value=0
  2 : Constant  Value=0
  3 : Constant  Value=100
  4 : Constant  Value=100
  Add : Sum  Inputs=+++  OutMin=[0.01]
  Add1 : Sum  Inputs=+++  OutMin=[0.01]
  Add2 : Sum  Inputs=+-  OutMin=[0.01]
  Add3 : Sum  Inputs=+-  OutMin=[0.01]
  Divide : Product  Inputs=*/
  Divide1 : Product  Inputs=/*
  Divide2 : Product  Inputs=*/
  Divide3 : Product  Inputs=/*
  Product{,1..3} (4 alike) : Product
  Switch : Switch  Criteria=u2 > Threshold  Threshold=10
  Switch1 : Switch  Criteria=u2 > Threshold  Threshold=10
  Switch2 : Switch  Criteria=u2 > Threshold
  Switch3 : Switch  Criteria=u2 > Threshold
  Switch4 : Switch  Criteria=u2 > Threshold  Threshold=90
  Switch5 : Switch  Criteria=u2 > Threshold  Threshold=90
  fn5 : Constant  Value=0
  fn6 : Constant  Value=0
  fn8 : Constant  Value=1e-6
  Q1 : Outport
  Q2 : Outport  Port=2
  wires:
  Switch3/1 -> Q2/1
  Product3/1 -> Switch3/3
  3/1 -> Add3/1
  [SOC1] -> Switch4/2, Add3/2
  [SOC2] -> Switch5/2, Add2/2
  4/1 -> Add2/1
  Switch2/1 -> Q1/1
  Add/1 -> Divide/2, Divide1/1
  2/1 -> Switch1/3
  fn6/1 -> Switch5/1
  [SOC2] -> Switch1/2, Switch1/1
  Divide2/1 -> Product2/2
  fn5/1 -> Switch4/1
  Switch4/1 -> Divide2/1, Add1/1
  Switch1/1 -> Add/2, Divide1/2
  Divide3/1 -> Product3/2
  [SOC1] -> Switch/1, Switch/2
  Product/1 -> Switch2/1
  Add3/1 -> Switch4/3
  Product2/1 -> Switch2/3
  QAll/1 -> Product/1, Product1/1, Product2/1, Product3/1, Switch3/2, Switch2/2
  Add2/1 -> Switch5/3
  Add1/1 -> Divide3/1, Divide2/2
  Product1/1 -> Switch3/1
  1/1 -> Switch/3
  Divide1/1 -> Product1/2
  Divide/1 -> Product/2
  Switch5/1 -> Divide3/2, Add1/2
  Switch/1 -> Add/1, Divide/1
  fn8/1 -> Add1/3, Add/3

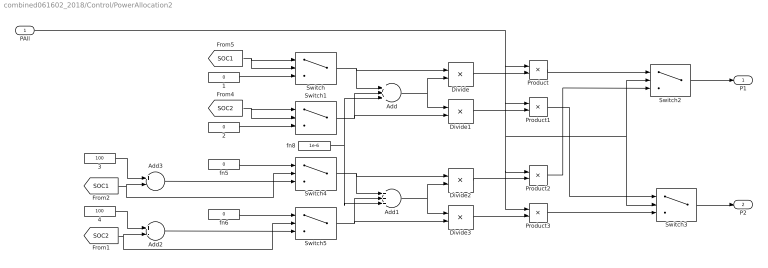
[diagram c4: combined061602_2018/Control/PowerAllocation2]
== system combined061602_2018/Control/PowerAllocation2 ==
  PAll : Inport
  1 : Constant  Value=0
  2 : Constant  Value=0
  3 : Constant  Value=100
  4 : Constant  Value=100
  Add : Sum  Inputs=+++  OutMin=[0.01]
  Add1 : Sum  Inputs=+++  OutMin=[0.01]
  Add2 : Sum  Inputs=+-  OutMin=[0.01]
  Add3 : Sum  Inputs=+-  OutMin=[0.01]
  Divide : Product  Inputs=*/
  Divide1 : Product  Inputs=/*
  Divide2 : Product  Inputs=*/
  Divide3 : Product  Inputs=/*
  Product{,1..3} (4 alike) : Product
  Switch : Switch  Criteria=u2 > Threshold  Threshold=10
  Switch1 : Switch  Criteria=u2 > Threshold  Threshold=10
  Switch2 : Switch  Criteria=u2 > Threshold
  Switch3 : Switch  Criteria=u2 > Threshold
  Switch4 : Switch  Criteria=u2 > Threshold  Threshold=90
  Switch5 : Switch  Criteria=u2 > Threshold  Threshold=90
  fn5 : Constant  Value=0
  fn6 : Constant  Value=0
  fn8 : Constant  Value=1e-6
  P1 : Outport
  P2 : Outport  Port=2
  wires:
  Switch3/1 -> P2/1
  Product3/1 -> Switch3/3
  3/1 -> Add3/1
  [SOC1] -> Switch4/2, Add3/2
  [SOC2] -> Switch5/2, Add2/2
  4/1 -> Add2/1
  Switch2/1 -> P1/1
  Add/1 -> Divide/2, Divide1/1
  2/1 -> Switch1/3
  fn6/1 -> Switch5/1
  [SOC2] -> Switch1/2, Switch1/1
  Divide2/1 -> Product2/2
  fn5/1 -> Switch4/1
  Switch4/1 -> Divide2/1, Add1/1
  Switch1/1 -> Add/2, Divide1/2
  Divide3/1 -> Product3/2
  [SOC1] -> Switch/1, Switch/2
  Product/1 -> Switch2/1
  Add3/1 -> Switch4/3
  Product2/1 -> Switch2/3
  PAll/1 -> Product/1, Product1/1, Product2/1, Product3/1, Switch3/2, Switch2/2
  Add2/1 -> Switch5/3
  Add1/1 -> Divide3/1, Divide2/2
  Product1/1 -> Switch3/1
  1/1 -> Switch/3
  Divide1/1 -> Product1/2
  Divide/1 -> Product/2
  Switch5/1 -> Divide3/2, Add1/2
  Switch/1 -> Add/1, Divide/1
  fn8/1 -> Add1/3, Add/3

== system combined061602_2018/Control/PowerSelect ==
  PAll : Inport
  Add4 : Sum  Inputs=+-  OutMin=[0.01]
  Add5 : Sum  OutMin=[0.01]
  Compare To Constant : simulink/Logic and Bit Operations/Compare To Constant  relop=>=  const=-5  OutDataTypeStr=boolean
  Compare To Constant1 : simulink/Logic and Bit Operations/Compare To Constant  relop=<=  const=5  OutDataTypeStr=boolean
  Divide4 : Product  Inputs=/*
  Divide5 : Product  Inputs=*/
  Product4 : Product
  Product5 : Product
  Switch7 : Switch  Criteria=u2 > Threshold
  Switch8 : Switch  Criteria=u2 > Threshold
  P1 : Outport
  P2 : Outport  Port=2
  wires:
  [SOC1] -> Add4/1
  [SOC2] -> Add4/2
  Add4/1 -> Compare To Constant/1, Compare To Constant1/1
  Compare To Constant/1 -> Add5/1, Divide5/1
  Compare To Constant1/1 -> Add5/2, Divide4/2
  Add5/1 -> Divide5/2, Divide4/1
  Divide5/1 -> Product4/2
  Divide4/1 -> Product5/2
  PAll/1 -> Switch8/2, Switch7/2, Product5/1, Product4/1
  Product4/1 -> Switch8/3, Switch7/1
  Product5/1 -> Switch8/1, Switch7/3
  Switch8/1 -> P2/1
  Switch7/1 -> P1/1

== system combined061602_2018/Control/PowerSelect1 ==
  PAll : Inport
  Add4 : Sum  Inputs=+-  OutMin=[0.01]
  Add5 : Sum  OutMin=[0.01]
  Compare To Constant : simulink/Logic and Bit Operations/Compare To Constant  relop=>=  const=-5  OutDataTypeStr=uint8
  Compare To Constant1 : simulink/Logic and Bit Operations/Compare To Constant  relop=<=  const=5  OutDataTypeStr=uint8
  Divide4 : Product  Inputs=/*  OutDataTypeStr=double
  Divide5 : Product  Inputs=*/  OutDataTypeStr=double
  Product4 : Product
  Product5 : Product
  Switch7 : Switch  Criteria=u2 > Threshold
  Switch8 : Switch  Criteria=u2 > Threshold
  P1 : Outport
  P2 : Outport  Port=2
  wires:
  Switch7/1 -> P1/1
  Switch8/1 -> P2/1
  Product5/1 -> Switch7/3, Switch8/1
  Product4/1 -> Switch7/1, Switch8/3
  PAll/1 -> Product4/1, Product5/1, Switch7/2, Switch8/2
  Divide4/1 -> Product5/2
  Divide5/1 -> Product4/2
  Add5/1 -> Divide4/1, Divide5/2
  Compare To Constant1/1 -> Divide4/2, Add5/2
  Compare To Constant/1 -> Divide5/1, Add5/1
  Add4/1 -> Compare To Constant1/1, Compare To Constant/1
  [SOC_PLC2] -> Add4/2
  [SOC_PLC1] -> Add4/1
  [SOC1] -> ?
  [SOC2] -> ?

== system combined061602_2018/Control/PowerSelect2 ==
  PAll : Inport
  Add4 : Sum  Inputs=+-  OutMin=[0.01]
  Add5 : Sum  OutMin=[0.01]
  Compare To Constant : simulink/Logic and Bit Operations/Compare To Constant  relop=>=  const=-5  OutDataTypeStr=uint8
  Compare To Constant1 : simulink/Logic and Bit Operations/Compare To Constant  relop=<=  const=5  OutDataTypeStr=uint8
  Divide4 : Product  Inputs=/*  OutDataTypeStr=double
  Divide5 : Product  Inputs=*/  OutDataTypeStr=double
  Product4 : Product
  Product5 : Product
  Switch7 : Switch  Criteria=u2 > Threshold
  Switch8 : Switch  Criteria=u2 > Threshold
  P1 : Outport
  P2 : Outport  Port=2
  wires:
  [SOC_PLC1] -> Add4/1
  [SOC_PLC2] -> Add4/2
  Add4/1 -> Compare To Constant/1, Compare To Constant1/1
  Compare To Constant/1 -> Add5/1, Divide5/1
  Compare To Constant1/1 -> Add5/2, Divide4/2
  Add5/1 -> Divide5/2, Divide4/1
  Divide5/1 -> Product4/2
  Divide4/1 -> Product5/2
  PAll/1 -> Switch8/2, Switch7/2, Product5/1, Product4/1
  Product4/1 -> Switch8/3, Switch7/1
  Product5/1 -> Switch8/1, Switch7/3
  Switch8/1 -> P2/1
  Switch7/1 -> P1/1
  [SOC1] -> ?
  [SOC2] -> ?

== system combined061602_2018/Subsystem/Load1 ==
  P : Inport
  Q : Inport  Port=2
  active : Inport  Port=3
  Vt_a : Inport  Port=4
  Current Caculator : MATLAB Function  TreatAsAtomicUnit=on
  Ground : powerlib/Elements/Ground  LConnTagsString=a
  Memory : Memory
  PLL : powerlib_meascontrol/PLL/PLL  Fmin=45  Par_Init=[0, 50]  ParK=[180, 3200, 1]  TcD=1e-4  MaxRateChangeFreq=12  FilterCutOffFreq=25  Ts=0  AGC=on
  Phase_A : powerlib/Electrical Sources/Controlled Current Source  Initialize=on  Source_Type=AC  Amplitude=0  Phase=0  Frequency=0  Measurements=None
  Phase_B : powerlib/Electrical Sources/Controlled Current Source  Initialize=on  Source_Type=AC  Amplitude=0  Phase=0  Frequency=0  Measurements=None
  Phase_C : powerlib/Electrical Sources/Controlled Current Source  Initialize=on  Source_Type=AC  Amplitude=0  Phase=0  Frequency=0  Measurements=None
  RMS1 : powerlib_meascontrol/Measurements/RMS  TrueRMS=on  Freq=50  RMSInit=600/sqrt(3)  Ts=0
  Three-Phase Series RLC Load1 : powerlib/Elements/Three-Phase Series RLC Load  LConnTagsString=A|B|C  Configuration=Y (grounded)  NominalVoltage=600  Vabc=[1e3 1e3 1e3]  Vabcp=[1e3 1e3 1e3]  NominalFrequency=50  UnbalancedPower=off  ActivePower=10  InductivePower=0  CapacitivePower=0  Pabc=[10e3 9e3 11e3]  QLabc=[100 90 110]  QCabc=[100 90 110]  Pabcp=[10e3 9e3 11e3]  QLabcp=[100 90 110]  QCabcp=[100 90 110]  Measurements=None  LoadType=constant Z
  Three-Phase Series RLC Load2 : powerlib/Elements/Three-Phase Series RLC Load  LConnTagsString=A|B|C  Configuration=Y (grounded)  NominalVoltage=600  Vabc=[1e3 1e3 1e3]  Vabcp=[1e3 1e3 1e3]  NominalFrequency=50  UnbalancedPower=off  ActivePower=10  InductivePower=0  CapacitivePower=0  Pabc=[10e3 9e3 11e3]  QLabc=[100 90 110]  QCabc=[100 90 110]  Pabcp=[10e3 9e3 11e3]  QLabcp=[100 90 110]  QCabcp=[100 90 110]  Measurements=None  LoadType=constant Z
  Three-Phase V-I Measurement : powerlib/Measurements/Three-Phase V-I Measurement  VoltageMeasurement=phase-to-ground  SetLabelV=off  LabelV=Vabc  Vpu=off  VpuLL=off  CurrentMeasurement=yes  SetLabelI=off  LabelI=Iabc  Ipu=off  Pbase=100e6  Vbase=500e3  OutputType=Complex  PhasorSimulation=off  PSBequivalent=0
  Three-Phase V-I Measurement1 : powerlib/Measurements/Three-Phase V-I Measurement  VoltageMeasurement=phase-to-ground  SetLabelV=off  LabelV=Vabc  Vpu=off  VpuLL=off  CurrentMeasurement=yes  SetLabelI=off  LabelI=Iabc  Ipu=off  Pbase=100e6  Vbase=500e3  OutputType=Complex  PhasorSimulation=off  PSBequivalent=0
  Three-Phase Breaker : powerlib/Elements/Three-Phase Breaker  InitialState=open  SwitchA=on  SwitchB=on  SwitchC=on  SwitchTimes=[2]  External=on  BreakerResistance=0.01  SnubberResistance=inf  SnubberCapacitance=inf  Measurements=None
  A : PMIOPort  Side=Right
  B : PMIOPort  Port=2  Side=Right
  C : PMIOPort  Port=3  Side=Right
  Vabc : Outport
  Iabc : Outport  Port=2
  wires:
  Current Caculator/2(ib) -> Phase_B/1
  Current Caculator/1(ia) -> Phase_A/1
  Current Caculator/3(ic) -> Phase_C/1
  active/1 -> Three-Phase Breaker/1, Current Caculator/5(active)
  Q/1 -> Current Caculator/2(q)
  Vt_a/1 -> Memory/1, PLL/1
  P/1 -> Current Caculator/1(p)
  RMS1/1 -> Current Caculator/4(vrms)
  Memory/1 -> RMS1/1
  Three-Phase V-I Measurement1/1 -> Vabc/1
  Three-Phase V-I Measurement1/2 -> Iabc/1
  PLL/2 -> Current Caculator/3(wt)
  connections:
  Three-Phase Breaker/LConn2 -- Three-Phase V-I Measurement/RConn2
  Ground/LConn1 -- Phase_B/LConn1 -- Phase_A/LConn1 -- Phase_C/LConn1
  Phase_C/RConn1 -- Three-Phase Series RLC Load1/LConn3 -- Three-Phase V-I Measurement/LConn3
  Three-Phase Breaker/LConn1 -- Three-Phase V-I Measurement/RConn1
  Three-Phase Breaker/LConn3 -- Three-Phase V-I Measurement/RConn3
  Three-Phase Breaker/RConn1 -- Three-Phase Series RLC Load2/LConn1 -- Three-Phase V-I Measurement1/LConn1
  Three-Phase V-I Measurement/LConn2 -- Three-Phase Series RLC Load1/LConn2 -- Phase_B/RConn1
  Phase_A/RConn1 -- Three-Phase Series RLC Load1/LConn1 -- Three-Phase V-I Measurement/LConn1
  Three-Phase Breaker/RConn3 -- Three-Phase Series RLC Load2/LConn3 -- Three-Phase V-I Measurement1/LConn3
  Three-Phase Breaker/RConn2 -- Three-Phase Series RLC Load2/LConn2 -- Three-Phase V-I Measurement1/LConn2
  A/RConn1 -- Three-Phase V-I Measurement1/RConn1
  Three-Phase V-I Measurement1/RConn2 -- B/RConn1
  C/RConn1 -- Three-Phase V-I Measurement1/RConn3

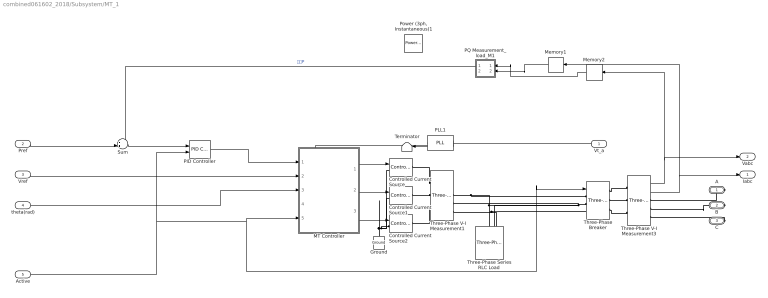
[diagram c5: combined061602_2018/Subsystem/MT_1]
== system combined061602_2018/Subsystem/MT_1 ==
  Vt_a : Inport
  Pref : Inport  Port=2
  Vref : Inport  Port=3
  theta(rad) : Inport  Port=4
  Active : Inport  Port=5
  Controlled Current Source : powerlib/Electrical Sources/Controlled Current Source  Initialize=on  Source_Type=AC  Amplitude=0  Phase=0  Frequency=0  Measurements=None
  Controlled Current Source1 : powerlib/Electrical Sources/Controlled Current Source  Initialize=on  Source_Type=AC  Amplitude=0  Phase=0  Frequency=0  Measurements=None
  Controlled Current Source2 : powerlib/Electrical Sources/Controlled Current Source  Initialize=on  Source_Type=AC  Amplitude=0  Phase=0  Frequency=0  Measurements=None
  Ground : powerlib/Elements/Ground  LConnTagsString=a
  MT Controller : MATLAB Function  TreatAsAtomicUnit=on
  Memory1 : Memory
  Memory2 : Memory
  PID Controller : simulink/Continuous/PID Controller  Controller=PI  Form=Parallel  TimeDomain=Continuous-time  SampleTime=-1  IntegratorMethod=Forward Euler  FilterMethod=Forward Euler  ControllerParametersSource=internal  P=0.01  I=0.2  D=0  UseFilter=on  N=100  TunerSelectOption=Transfer Function Based (PID Tuner App)  InitialConditionSource=internal  InitialConditionForIntegrator=0  InitialConditionForFilter=0  DifferentiatorICPrevScaledInput=0  ExternalReset=either  TrackingMode=off  Kt=1  LimitOutput=off  UpperSaturationLimit=inf  LowerSaturationLimit=-inf  LinearizeAsGain=on  AntiWindupMode=none  Kb=1  POutMin=[]  POutMax=[]  IOutMin=[]  IOutMax=[]  DOutMin=[]  DOutMax=[]  NOutMin=[]  NOutMax=[]  SumOutMin=[]  SumOutMax=[]  SaturationOutMin=[]  SaturationOutMax=[]  PParamMin=[]  PParamMax=[]  IParamMin=[]  IParamMax=[]  DParamMin=[]  DParamMax=[]  NParamMin=[]  NParamMax=[]  KbParamMin=[]  KbParamMax=[]  KtParamMin=[]  KtParamMax=[]  KbOutMin=[]  KbOutMax=[]  KtOutMin=[]  KtOutMax=[]  IntegratorOutMin=[]  IntegratorOutMax=[]  FilterOutMin=[]  FilterOutMax=[]  SumI1OutMin=[]  SumI1OutMax=[]  SumI2OutMin=[]  SumI2OutMax=[]  SumI3OutMin=[]  SumI3OutMax=[]  SumI4OutMin=[]  SumI4OutMax=[]  SumDOutMin=[]  SumDOutMax=[]  DifferentiatorOutMin=[]  DifferentiatorOutMax=[]  FilterDiffOutCoefMin=[]  FilterDiffOutCoefMax=[]  ReciprocalOutMin=[]  ReciprocalOutMax=[]  SumDenOutMin=[]  SumDenOutMax=[]  SumNumOutMin=[]  SumNumOutMax=[]  DivideOutMin=[]  DivideOutMax=[]  IntegratorContinuousStateAttributes=''  IntegratorStateMustResolveToSignalObject=off  IntegratorRTWStateStorageClass=Auto  FilterContinuousStateAttributes=''  FilterStateMustResolveToSignalObject=off  FilterRTWStateStorageClass=Auto  ParallelPVariant=InternalParameters  IdealPVariant=Disabled  IVariant=InternalParameters  DVariant=Disabled  IntegratorVariant=Continuous  SatVariant=Disabled  AWVariant=Passthrough  PCopyVariant=Disabled  TRVariant=Disabled  FdbkBlocksVariant=Forward  IdealPFdbkVariant=Disabled  SatFdbkVariant=Disabled  DerivativeFilterVariant=Disabled  NVariant=Disabled  NCopyVariant=Disabled_SignalSpec  FilterICVariant=Disabled  IntegratorICVariant=InternalICs  ExternalResetVariant=ExternalReset  TRSumVariant=Passthrough  SumFdbkVariant=Disabled  SumVariant=Sum_PI
  PLL1 : powerlib_meascontrol/PLL/PLL  Fmin=45  Par_Init=[0, 50]  ParK=[180, 3200, 1]  TcD=1e-4  MaxRateChangeFreq=12  FilterCutOffFreq=25  Ts=0  AGC=on
  PQ Measurement_load_M1 : Subsystem
  "Power (3ph, Instantaneous)1" : powerlib_meascontrol/Measurements/Power (3ph, Instantaneous)  Commented=on
  Sum : Sum  Inputs=-+|
  Terminator : Terminator
  Three-Phase Series RLC Load : powerlib/Elements/Three-Phase Series RLC Load  LConnTagsString=A|B|C  Configuration=Y (grounded)  NominalVoltage=400  Vabc=[1e3 1e3 1e3]  Vabcp=[1e3 1e3 1e3]  NominalFrequency=50  UnbalancedPower=off  ActivePower=10  InductivePower=0  CapacitivePower=0  Pabc=[10e3 9e3 11e3]  QLabc=[100 90 110]  QCabc=[100 90 110]  Pabcp=[10e3 9e3 11e3]  QLabcp=[100 90 110]  QCabcp=[100 90 110]  Measurements=None  LoadType=constant Z
  Three-Phase V-I Measurement1 : powerlib/Measurements/Three-Phase V-I Measurement  VoltageMeasurement=phase-to-ground  SetLabelV=off  LabelV=Vabc  Vpu=off  VpuLL=off  CurrentMeasurement=yes  SetLabelI=off  LabelI=Iabc  Ipu=off  Pbase=100e6  Vbase=500e3  OutputType=Complex  PhasorSimulation=off  PSBequivalent=0
  Three-Phase V-I Measurement3 : powerlib/Measurements/Three-Phase V-I Measurement  VoltageMeasurement=phase-to-ground  SetLabelV=off  LabelV=Vabc  Vpu=off  VpuLL=off  CurrentMeasurement=yes  SetLabelI=off  LabelI=Iabc  Ipu=off  Pbase=100e6  Vbase=500e3  OutputType=Complex  PhasorSimulation=off  PSBequivalent=0
  Three-Phase Breaker : powerlib/Elements/Three-Phase Breaker  InitialState=open  SwitchA=on  SwitchB=on  SwitchC=on  SwitchTimes=[2]  External=on  BreakerResistance=0.01  SnubberResistance=inf  SnubberCapacitance=0  Measurements=None
  A : PMIOPort  Side=Right
  B : PMIOPort  Port=2  Side=Right
  C : PMIOPort  Port=3  Side=Right
  Iabc : Outport
  Vabc : Outport  Port=2
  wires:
  PQ Measurement_load_M1/1(P) -> Sum/1  "燃机P"
  Memory2/1 -> PQ Measurement_load_M1/1(Vabc)
  Memory1/1 -> PQ Measurement_load_M1/2(Iabc)
  theta(rad)/1 -> MT Controller/3(theta)
  PID Controller/1 -> MT Controller/1(Pref)
  Pref/1 -> Sum/2
  Vref/1 -> MT Controller/2(Vref)
  Sum/1 -> PID Controller/1
  Active/1 -> PID Controller/2, Three-Phase Breaker/1, MT Controller/5(active)
  Three-Phase V-I Measurement3/2 -> Iabc/1, Memory1/1
  Vt_a/1 -> PLL1/1
  Three-Phase V-I Measurement3/1 -> Vabc/1, Memory2/1
  PLL1/1 -> Terminator/1
  MT Controller/3(ic) -> Controlled Current Source2/1
  MT Controller/2(ib) -> Controlled Current Source1/1
  PLL1/2 -> MT Controller/4(wt)
  MT Controller/1(ia) -> Controlled Current Source/1
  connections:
  Three-Phase V-I Measurement1/RConn3 -- Three-Phase Series RLC Load/LConn3 -- Three-Phase Breaker/LConn3
  Three-Phase V-I Measurement1/RConn1 -- Three-Phase Series RLC Load/LConn1 -- Three-Phase Breaker/LConn1
  Three-Phase Breaker/LConn2 -- Three-Phase V-I Measurement1/RConn2 -- Three-Phase Series RLC Load/LConn2
  Three-Phase Breaker/RConn3 -- Three-Phase V-I Measurement3/LConn3
  Three-Phase Breaker/RConn1 -- Three-Phase V-I Measurement3/LConn1
  Three-Phase V-I Measurement3/LConn2 -- Three-Phase Breaker/RConn2
  Three-Phase V-I Measurement1/LConn3 -- Controlled Current Source2/RConn1
  Three-Phase V-I Measurement1/LConn1 -- Controlled Current Source/RConn1
  Three-Phase V-I Measurement1/LConn2 -- Controlled Current Source1/RConn1
  C/RConn1 -- Three-Phase V-I Measurement3/RConn3
  B/RConn1 -- Three-Phase V-I Measurement3/RConn2
  A/RConn1 -- Three-Phase V-I Measurement3/RConn1
  Controlled Current Source2/LConn1 -- Controlled Current Source1/LConn1 -- Controlled Current Source/LConn1 -- Ground/LConn1
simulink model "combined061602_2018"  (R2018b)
settings: Solver=ode5  StartTime=0.0  StopTime=inf  FixedStep=1e-5  RelTol=1e-3
libraries: powerlib x156, powerlib_meascontrol x64, simulink x32, dspsigops x2
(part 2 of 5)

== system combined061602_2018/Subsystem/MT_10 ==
  Vt_a : Inport
  Pref : Inport  Port=2
  Vref : Inport  Port=3
  theta(rad) : Inport  Port=4
  Active : Inport  Port=5
  Controlled Current Source : powerlib/Electrical Sources/Controlled Current Source  Initialize=on  Source_Type=AC  Amplitude=0  Phase=0  Frequency=0  Measurements=None
  Controlled Current Source1 : powerlib/Electrical Sources/Controlled Current Source  Initialize=on  Source_Type=AC  Amplitude=0  Phase=0  Frequency=0  Measurements=None
  Controlled Current Source2 : powerlib/Electrical Sources/Controlled Current Source  Initialize=on  Source_Type=AC  Amplitude=0  Phase=0  Frequency=0  Measurements=None
  Ground : powerlib/Elements/Ground  LConnTagsString=a
  MT Controller : MATLAB Function  TreatAsAtomicUnit=on
  Memory1 : Memory
  Memory2 : Memory
  PID Controller : simulink/Continuous/PID Controller  Controller=PI  Form=Parallel  TimeDomain=Continuous-time  SampleTime=-1  IntegratorMethod=Forward Euler  FilterMethod=Forward Euler  ControllerParametersSource=internal  P=0.01  I=0.2  D=0  UseFilter=on  N=100  TunerSelectOption=Transfer Function Based (PID Tuner App)  InitialConditionSource=internal  InitialConditionForIntegrator=0  InitialConditionForFilter=0  DifferentiatorICPrevScaledInput=0  ExternalReset=either  TrackingMode=off  Kt=1  LimitOutput=off  UpperSaturationLimit=inf  LowerSaturationLimit=-inf  LinearizeAsGain=on  AntiWindupMode=none  Kb=1  POutMin=[]  POutMax=[]  IOutMin=[]  IOutMax=[]  DOutMin=[]  DOutMax=[]  NOutMin=[]  NOutMax=[]  SumOutMin=[]  SumOutMax=[]  SaturationOutMin=[]  SaturationOutMax=[]  PParamMin=[]  PParamMax=[]  IParamMin=[]  IParamMax=[]  DParamMin=[]  DParamMax=[]  NParamMin=[]  NParamMax=[]  KbParamMin=[]  KbParamMax=[]  KtParamMin=[]  KtParamMax=[]  KbOutMin=[]  KbOutMax=[]  KtOutMin=[]  KtOutMax=[]  IntegratorOutMin=[]  IntegratorOutMax=[]  FilterOutMin=[]  FilterOutMax=[]  SumI1OutMin=[]  SumI1OutMax=[]  SumI2OutMin=[]  SumI2OutMax=[]  SumI3OutMin=[]  SumI3OutMax=[]  SumI4OutMin=[]  SumI4OutMax=[]  SumDOutMin=[]  SumDOutMax=[]  DifferentiatorOutMin=[]  DifferentiatorOutMax=[]  FilterDiffOutCoefMin=[]  FilterDiffOutCoefMax=[]  ReciprocalOutMin=[]  ReciprocalOutMax=[]  SumDenOutMin=[]  SumDenOutMax=[]  SumNumOutMin=[]  SumNumOutMax=[]  DivideOutMin=[]  DivideOutMax=[]  IntegratorContinuousStateAttributes=''  IntegratorStateMustResolveToSignalObject=off  IntegratorRTWStateStorageClass=Auto  FilterContinuousStateAttributes=''  FilterStateMustResolveToSignalObject=off  FilterRTWStateStorageClass=Auto  ParallelPVariant=InternalParameters  IdealPVariant=Disabled  IVariant=InternalParameters  DVariant=Disabled  IntegratorVariant=Continuous  SatVariant=Disabled  AWVariant=Passthrough  PCopyVariant=Disabled  TRVariant=Disabled  FdbkBlocksVariant=Forward  IdealPFdbkVariant=Disabled  SatFdbkVariant=Disabled  DerivativeFilterVariant=Disabled  NVariant=Disabled  NCopyVariant=Disabled_SignalSpec  FilterICVariant=Disabled  IntegratorICVariant=InternalICs  ExternalResetVariant=ExternalReset  TRSumVariant=Passthrough  SumFdbkVariant=Disabled  SumVariant=Sum_PI
  PLL1 : powerlib_meascontrol/PLL/PLL  Fmin=45  Par_Init=[0, 50]  ParK=[180, 3200, 1]  TcD=1e-4  MaxRateChangeFreq=12  FilterCutOffFreq=25  Ts=0  AGC=on
  PQ Measurement_load_M2 : Subsystem
  Sum : Sum  Inputs=-+|
  Terminator : Terminator
  Three-Phase Series RLC Load : powerlib/Elements/Three-Phase Series RLC Load  LConnTagsString=A|B|C  Configuration=Y (grounded)  NominalVoltage=400  Vabc=[1e3 1e3 1e3]  Vabcp=[1e3 1e3 1e3]  NominalFrequency=50  UnbalancedPower=off  ActivePower=10  InductivePower=0  CapacitivePower=0  Pabc=[10e3 9e3 11e3]  QLabc=[100 90 110]  QCabc=[100 90 110]  Pabcp=[10e3 9e3 11e3]  QLabcp=[100 90 110]  QCabcp=[100 90 110]  Measurements=None  LoadType=constant Z
  Three-Phase V-I Measurement1 : powerlib/Measurements/Three-Phase V-I Measurement  VoltageMeasurement=phase-to-ground  SetLabelV=off  LabelV=Vabc  Vpu=off  VpuLL=off  CurrentMeasurement=yes  SetLabelI=off  LabelI=Iabc  Ipu=off  Pbase=100e6  Vbase=500e3  OutputType=Complex  PhasorSimulation=off  PSBequivalent=0
  Three-Phase V-I Measurement3 : powerlib/Measurements/Three-Phase V-I Measurement  VoltageMeasurement=phase-to-ground  SetLabelV=off  LabelV=Vabc  Vpu=off  VpuLL=off  CurrentMeasurement=yes  SetLabelI=off  LabelI=Iabc  Ipu=off  Pbase=100e6  Vbase=500e3  OutputType=Complex  PhasorSimulation=off  PSBequivalent=0
  Three-Phase Breaker : powerlib/Elements/Three-Phase Breaker  InitialState=open  SwitchA=on  SwitchB=on  SwitchC=on  SwitchTimes=[2]  External=on  BreakerResistance=0.01  SnubberResistance=inf  SnubberCapacitance=0  Measurements=None
  A : PMIOPort  Side=Right
  B : PMIOPort  Port=2  Side=Right
  C : PMIOPort  Port=3  Side=Right
  Iabc : Outport
  Vabc : Outport  Port=2
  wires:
  PQ Measurement_load_M2/1(P) -> Sum/1  "燃机P"
  Memory2/1 -> PQ Measurement_load_M2/1(Vabc)
  Memory1/1 -> PQ Measurement_load_M2/2(Iabc)
  theta(rad)/1 -> MT Controller/3(theta)
  PID Controller/1 -> MT Controller/1(Pref)
  Pref/1 -> Sum/2
  Vref/1 -> MT Controller/2(Vref)
  Sum/1 -> PID Controller/1
  Active/1 -> PID Controller/2, Three-Phase Breaker/1, MT Controller/5(active)
  Three-Phase V-I Measurement3/2 -> Iabc/1, Memory1/1
  Vt_a/1 -> PLL1/1
  Three-Phase V-I Measurement3/1 -> Vabc/1, Memory2/1
  PLL1/1 -> Terminator/1
  MT Controller/3(ic) -> Controlled Current Source2/1
  MT Controller/2(ib) -> Controlled Current Source1/1
  PLL1/2 -> MT Controller/4(wt)
  MT Controller/1(ia) -> Controlled Current Source/1
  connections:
  Three-Phase V-I Measurement1/RConn3 -- Three-Phase Series RLC Load/LConn3 -- Three-Phase Breaker/LConn3
  Three-Phase V-I Measurement1/RConn1 -- Three-Phase Series RLC Load/LConn1 -- Three-Phase Breaker/LConn1
  Three-Phase Breaker/LConn2 -- Three-Phase V-I Measurement1/RConn2 -- Three-Phase Series RLC Load/LConn2
  Three-Phase Breaker/RConn3 -- Three-Phase V-I Measurement3/LConn3
  Three-Phase Breaker/RConn1 -- Three-Phase V-I Measurement3/LConn1
  Three-Phase V-I Measurement3/LConn2 -- Three-Phase Breaker/RConn2
  Three-Phase V-I Measurement1/LConn3 -- Controlled Current Source2/RConn1
  Three-Phase V-I Measurement1/LConn1 -- Controlled Current Source/RConn1
  Three-Phase V-I Measurement1/LConn2 -- Controlled Current Source1/RConn1
  C/RConn1 -- Three-Phase V-I Measurement3/RConn3
  B/RConn1 -- Three-Phase V-I Measurement3/RConn2
  A/RConn1 -- Three-Phase V-I Measurement3/RConn1
  Controlled Current Source2/LConn1 -- Controlled Current Source1/LConn1 -- Controlled Current Source/LConn1 -- Ground/LConn1

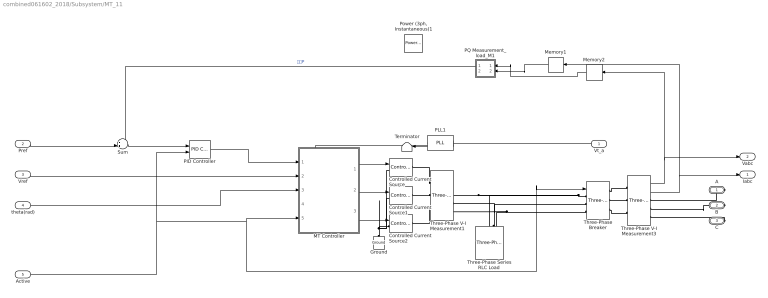
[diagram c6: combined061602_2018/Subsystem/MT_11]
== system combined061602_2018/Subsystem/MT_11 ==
  Vt_a : Inport
  Pref : Inport  Port=2
  Vref : Inport  Port=3
  theta(rad) : Inport  Port=4
  Active : Inport  Port=5
  Controlled Current Source : powerlib/Electrical Sources/Controlled Current Source  Initialize=on  Source_Type=AC  Amplitude=0  Phase=0  Frequency=0  Measurements=None
  Controlled Current Source1 : powerlib/Electrical Sources/Controlled Current Source  Initialize=on  Source_Type=AC  Amplitude=0  Phase=0  Frequency=0  Measurements=None
  Controlled Current Source2 : powerlib/Electrical Sources/Controlled Current Source  Initialize=on  Source_Type=AC  Amplitude=0  Phase=0  Frequency=0  Measurements=None
  Ground : powerlib/Elements/Ground  LConnTagsString=a
  MT Controller : MATLAB Function  TreatAsAtomicUnit=on
  Memory1 : Memory
  Memory2 : Memory
  PID Controller : simulink/Continuous/PID Controller  Controller=PI  Form=Parallel  TimeDomain=Continuous-time  SampleTime=-1  IntegratorMethod=Forward Euler  FilterMethod=Forward Euler  ControllerParametersSource=internal  P=0.01  I=0.2  D=0  UseFilter=on  N=100  TunerSelectOption=Transfer Function Based (PID Tuner App)  InitialConditionSource=internal  InitialConditionForIntegrator=0  InitialConditionForFilter=0  DifferentiatorICPrevScaledInput=0  ExternalReset=either  TrackingMode=off  Kt=1  LimitOutput=off  UpperSaturationLimit=inf  LowerSaturationLimit=-inf  LinearizeAsGain=on  AntiWindupMode=none  Kb=1  POutMin=[]  POutMax=[]  IOutMin=[]  IOutMax=[]  DOutMin=[]  DOutMax=[]  NOutMin=[]  NOutMax=[]  SumOutMin=[]  SumOutMax=[]  SaturationOutMin=[]  SaturationOutMax=[]  PParamMin=[]  PParamMax=[]  IParamMin=[]  IParamMax=[]  DParamMin=[]  DParamMax=[]  NParamMin=[]  NParamMax=[]  KbParamMin=[]  KbParamMax=[]  KtParamMin=[]  KtParamMax=[]  KbOutMin=[]  KbOutMax=[]  KtOutMin=[]  KtOutMax=[]  IntegratorOutMin=[]  IntegratorOutMax=[]  FilterOutMin=[]  FilterOutMax=[]  SumI1OutMin=[]  SumI1OutMax=[]  SumI2OutMin=[]  SumI2OutMax=[]  SumI3OutMin=[]  SumI3OutMax=[]  SumI4OutMin=[]  SumI4OutMax=[]  SumDOutMin=[]  SumDOutMax=[]  DifferentiatorOutMin=[]  DifferentiatorOutMax=[]  FilterDiffOutCoefMin=[]  FilterDiffOutCoefMax=[]  ReciprocalOutMin=[]  ReciprocalOutMax=[]  SumDenOutMin=[]  SumDenOutMax=[]  SumNumOutMin=[]  SumNumOutMax=[]  DivideOutMin=[]  DivideOutMax=[]  IntegratorContinuousStateAttributes=''  IntegratorStateMustResolveToSignalObject=off  IntegratorRTWStateStorageClass=Auto  FilterContinuousStateAttributes=''  FilterStateMustResolveToSignalObject=off  FilterRTWStateStorageClass=Auto  ParallelPVariant=InternalParameters  IdealPVariant=Disabled  IVariant=InternalParameters  DVariant=Disabled  IntegratorVariant=Continuous  SatVariant=Disabled  AWVariant=Passthrough  PCopyVariant=Disabled  TRVariant=Disabled  FdbkBlocksVariant=Forward  IdealPFdbkVariant=Disabled  SatFdbkVariant=Disabled  DerivativeFilterVariant=Disabled  NVariant=Disabled  NCopyVariant=Disabled_SignalSpec  FilterICVariant=Disabled  IntegratorICVariant=InternalICs  ExternalResetVariant=ExternalReset  TRSumVariant=Passthrough  SumFdbkVariant=Disabled  SumVariant=Sum_PI
  PLL1 : powerlib_meascontrol/PLL/PLL  Fmin=45  Par_Init=[0, 50]  ParK=[180, 3200, 1]  TcD=1e-4  MaxRateChangeFreq=12  FilterCutOffFreq=25  Ts=0  AGC=on
  PQ Measurement_load_M1 : Subsystem
  "Power (3ph, Instantaneous)1" : powerlib_meascontrol/Measurements/Power (3ph, Instantaneous)  Commented=on
  Sum : Sum  Inputs=-+|
  Terminator : Terminator
  Three-Phase Series RLC Load : powerlib/Elements/Three-Phase Series RLC Load  LConnTagsString=A|B|C  Configuration=Y (grounded)  NominalVoltage=400  Vabc=[1e3 1e3 1e3]  Vabcp=[1e3 1e3 1e3]  NominalFrequency=50  UnbalancedPower=off  ActivePower=10  InductivePower=0  CapacitivePower=0  Pabc=[10e3 9e3 11e3]  QLabc=[100 90 110]  QCabc=[100 90 110]  Pabcp=[10e3 9e3 11e3]  QLabcp=[100 90 110]  QCabcp=[100 90 110]  Measurements=None  LoadType=constant Z
  Three-Phase V-I Measurement1 : powerlib/Measurements/Three-Phase V-I Measurement  VoltageMeasurement=phase-to-ground  SetLabelV=off  LabelV=Vabc  Vpu=off  VpuLL=off  CurrentMeasurement=yes  SetLabelI=off  LabelI=Iabc  Ipu=off  Pbase=100e6  Vbase=500e3  OutputType=Complex  PhasorSimulation=off  PSBequivalent=0
  Three-Phase V-I Measurement3 : powerlib/Measurements/Three-Phase V-I Measurement  VoltageMeasurement=phase-to-ground  SetLabelV=off  LabelV=Vabc  Vpu=off  VpuLL=off  CurrentMeasurement=yes  SetLabelI=off  LabelI=Iabc  Ipu=off  Pbase=100e6  Vbase=500e3  OutputType=Complex  PhasorSimulation=off  PSBequivalent=0
  Three-Phase Breaker : powerlib/Elements/Three-Phase Breaker  InitialState=open  SwitchA=on  SwitchB=on  SwitchC=on  SwitchTimes=[2]  External=on  BreakerResistance=0.01  SnubberResistance=inf  SnubberCapacitance=0  Measurements=None
  A : PMIOPort  Side=Right
  B : PMIOPort  Port=2  Side=Right
  C : PMIOPort  Port=3  Side=Right
  Iabc : Outport
  Vabc : Outport  Port=2
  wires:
  MT Controller/1(ia) -> Controlled Current Source/1
  PLL1/2 -> MT Controller/4(wt)
  MT Controller/2(ib) -> Controlled Current Source1/1
  MT Controller/3(ic) -> Controlled Current Source2/1
  PLL1/1 -> Terminator/1
  Three-Phase V-I Measurement3/1 -> Memory2/1, Vabc/1
  Vt_a/1 -> PLL1/1
  Three-Phase V-I Measurement3/2 -> Memory1/1, Iabc/1
  Active/1 -> MT Controller/5(active), Three-Phase Breaker/1, PID Controller/2
  Sum/1 -> PID Controller/1
  Vref/1 -> MT Controller/2(Vref)
  Pref/1 -> Sum/2
  PID Controller/1 -> MT Controller/1(Pref)
  theta(rad)/1 -> MT Controller/3(theta)
  Memory1/1 -> PQ Measurement_load_M1/2(Iabc)
  Memory2/1 -> PQ Measurement_load_M1/1(Vabc)
  PQ Measurement_load_M1/1(P) -> Sum/1  "燃机P"
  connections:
  Ground/LConn1 -- Controlled Current Source/LConn1 -- Controlled Current Source1/LConn1 -- Controlled Current Source2/LConn1
  A/RConn1 -- Three-Phase V-I Measurement3/RConn1
  B/RConn1 -- Three-Phase V-I Measurement3/RConn2
  C/RConn1 -- Three-Phase V-I Measurement3/RConn3
  Three-Phase V-I Measurement1/LConn2 -- Controlled Current Source1/RConn1
  Three-Phase V-I Measurement1/LConn1 -- Controlled Current Source/RConn1
  Three-Phase V-I Measurement1/LConn3 -- Controlled Current Source2/RConn1
  Three-Phase V-I Measurement3/LConn2 -- Three-Phase Breaker/RConn2
  Three-Phase Breaker/RConn1 -- Three-Phase V-I Measurement3/LConn1
  Three-Phase Breaker/RConn3 -- Three-Phase V-I Measurement3/LConn3
  Three-Phase Series RLC Load/LConn2 -- Three-Phase V-I Measurement1/RConn2 -- Three-Phase Breaker/LConn2
  Three-Phase Breaker/LConn1 -- Three-Phase Series RLC Load/LConn1 -- Three-Phase V-I Measurement1/RConn1
  Three-Phase Breaker/LConn3 -- Three-Phase Series RLC Load/LConn3 -- Three-Phase V-I Measurement1/RConn3

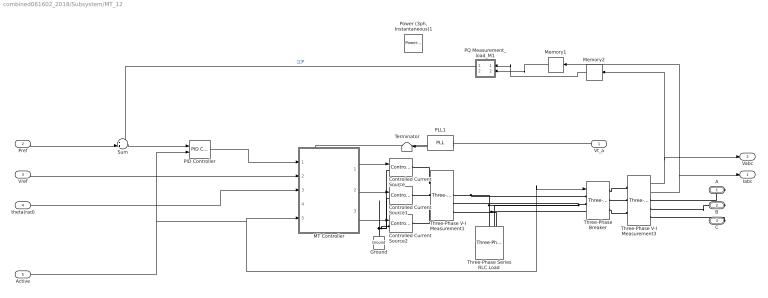
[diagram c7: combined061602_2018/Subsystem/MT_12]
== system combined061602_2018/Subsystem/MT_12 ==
  Vt_a : Inport
  Pref : Inport  Port=2
  Vref : Inport  Port=3
  theta(rad) : Inport  Port=4
  Active : Inport  Port=5
  Controlled Current Source : powerlib/Electrical Sources/Controlled Current Source  Initialize=on  Source_Type=AC  Amplitude=0  Phase=0  Frequency=0  Measurements=None
  Controlled Current Source1 : powerlib/Electrical Sources/Controlled Current Source  Initialize=on  Source_Type=AC  Amplitude=0  Phase=0  Frequency=0  Measurements=None
  Controlled Current Source2 : powerlib/Electrical Sources/Controlled Current Source  Initialize=on  Source_Type=AC  Amplitude=0  Phase=0  Frequency=0  Measurements=None
  Ground : powerlib/Elements/Ground  LConnTagsString=a
  MT Controller : MATLAB Function  TreatAsAtomicUnit=on
  Memory1 : Memory
  Memory2 : Memory
  PID Controller : simulink/Continuous/PID Controller  Controller=PI  Form=Parallel  TimeDomain=Continuous-time  SampleTime=-1  IntegratorMethod=Forward Euler  FilterMethod=Forward Euler  ControllerParametersSource=internal  P=0.01  I=0.2  D=0  UseFilter=on  N=100  TunerSelectOption=Transfer Function Based (PID Tuner App)  InitialConditionSource=internal  InitialConditionForIntegrator=0  InitialConditionForFilter=0  DifferentiatorICPrevScaledInput=0  ExternalReset=either  TrackingMode=off  Kt=1  LimitOutput=off  UpperSaturationLimit=inf  LowerSaturationLimit=-inf  LinearizeAsGain=on  AntiWindupMode=none  Kb=1  POutMin=[]  POutMax=[]  IOutMin=[]  IOutMax=[]  DOutMin=[]  DOutMax=[]  NOutMin=[]  NOutMax=[]  SumOutMin=[]  SumOutMax=[]  SaturationOutMin=[]  SaturationOutMax=[]  PParamMin=[]  PParamMax=[]  IParamMin=[]  IParamMax=[]  DParamMin=[]  DParamMax=[]  NParamMin=[]  NParamMax=[]  KbParamMin=[]  KbParamMax=[]  KtParamMin=[]  KtParamMax=[]  KbOutMin=[]  KbOutMax=[]  KtOutMin=[]  KtOutMax=[]  IntegratorOutMin=[]  IntegratorOutMax=[]  FilterOutMin=[]  FilterOutMax=[]  SumI1OutMin=[]  SumI1OutMax=[]  SumI2OutMin=[]  SumI2OutMax=[]  SumI3OutMin=[]  SumI3OutMax=[]  SumI4OutMin=[]  SumI4OutMax=[]  SumDOutMin=[]  SumDOutMax=[]  DifferentiatorOutMin=[]  DifferentiatorOutMax=[]  FilterDiffOutCoefMin=[]  FilterDiffOutCoefMax=[]  ReciprocalOutMin=[]  ReciprocalOutMax=[]  SumDenOutMin=[]  SumDenOutMax=[]  SumNumOutMin=[]  SumNumOutMax=[]  DivideOutMin=[]  DivideOutMax=[]  IntegratorContinuousStateAttributes=''  IntegratorStateMustResolveToSignalObject=off  IntegratorRTWStateStorageClass=Auto  FilterContinuousStateAttributes=''  FilterStateMustResolveToSignalObject=off  FilterRTWStateStorageClass=Auto  ParallelPVariant=InternalParameters  IdealPVariant=Disabled  IVariant=InternalParameters  DVariant=Disabled  IntegratorVariant=Continuous  SatVariant=Disabled  AWVariant=Passthrough  PCopyVariant=Disabled  TRVariant=Disabled  FdbkBlocksVariant=Forward  IdealPFdbkVariant=Disabled  SatFdbkVariant=Disabled  DerivativeFilterVariant=Disabled  NVariant=Disabled  NCopyVariant=Disabled_SignalSpec  FilterICVariant=Disabled  IntegratorICVariant=InternalICs  ExternalResetVariant=ExternalReset  TRSumVariant=Passthrough  SumFdbkVariant=Disabled  SumVariant=Sum_PI
  PLL1 : powerlib_meascontrol/PLL/PLL  Fmin=45  Par_Init=[0, 50]  ParK=[180, 3200, 1]  TcD=1e-4  MaxRateChangeFreq=12  FilterCutOffFreq=25  Ts=0  AGC=on
  PQ Measurement_load_M1 : Subsystem
  "Power (3ph, Instantaneous)1" : powerlib_meascontrol/Measurements/Power (3ph, Instantaneous)  Commented=on
  Sum : Sum  Inputs=-+|
  Terminator : Terminator
  Three-Phase Series RLC Load : powerlib/Elements/Three-Phase Series RLC Load  LConnTagsString=A|B|C  Configuration=Y (grounded)  NominalVoltage=400  Vabc=[1e3 1e3 1e3]  Vabcp=[1e3 1e3 1e3]  NominalFrequency=50  UnbalancedPower=off  ActivePower=10  InductivePower=0  CapacitivePower=0  Pabc=[10e3 9e3 11e3]  QLabc=[100 90 110]  QCabc=[100 90 110]  Pabcp=[10e3 9e3 11e3]  QLabcp=[100 90 110]  QCabcp=[100 90 110]  Measurements=None  LoadType=constant Z
  Three-Phase V-I Measurement1 : powerlib/Measurements/Three-Phase V-I Measurement  VoltageMeasurement=phase-to-ground  SetLabelV=off  LabelV=Vabc  Vpu=off  VpuLL=off  CurrentMeasurement=yes  SetLabelI=off  LabelI=Iabc  Ipu=off  Pbase=100e6  Vbase=500e3  OutputType=Complex  PhasorSimulation=off  PSBequivalent=0
  Three-Phase V-I Measurement3 : powerlib/Measurements/Three-Phase V-I Measurement  VoltageMeasurement=phase-to-ground  SetLabelV=off  LabelV=Vabc  Vpu=off  VpuLL=off  CurrentMeasurement=yes  SetLabelI=off  LabelI=Iabc  Ipu=off  Pbase=100e6  Vbase=500e3  OutputType=Complex  PhasorSimulation=off  PSBequivalent=0
  Three-Phase Breaker : powerlib/Elements/Three-Phase Breaker  InitialState=open  SwitchA=on  SwitchB=on  SwitchC=on  SwitchTimes=[2]  External=on  BreakerResistance=0.01  SnubberResistance=inf  SnubberCapacitance=0  Measurements=None
  A : PMIOPort  Side=Right
  B : PMIOPort  Port=2  Side=Right
  C : PMIOPort  Port=3  Side=Right
  Iabc : Outport
  Vabc : Outport  Port=2
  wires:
  PQ Measurement_load_M1/1(P) -> Sum/1  "燃机P"
  Memory2/1 -> PQ Measurement_load_M1/1(Vabc)
  Memory1/1 -> PQ Measurement_load_M1/2(Iabc)
  theta(rad)/1 -> MT Controller/3(theta)
  PID Controller/1 -> MT Controller/1(Pref)
  Pref/1 -> Sum/2
  Vref/1 -> MT Controller/2(Vref)
  Sum/1 -> PID Controller/1
  Active/1 -> PID Controller/2, Three-Phase Breaker/1, MT Controller/5(active)
  Three-Phase V-I Measurement3/2 -> Iabc/1, Memory1/1
  Vt_a/1 -> PLL1/1
  Three-Phase V-I Measurement3/1 -> Vabc/1, Memory2/1
  PLL1/1 -> Terminator/1
  MT Controller/3(ic) -> Controlled Current Source2/1
  MT Controller/2(ib) -> Controlled Current Source1/1
  PLL1/2 -> MT Controller/4(wt)
  MT Controller/1(ia) -> Controlled Current Source/1
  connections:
  Three-Phase V-I Measurement1/RConn3 -- Three-Phase Series RLC Load/LConn3 -- Three-Phase Breaker/LConn3
  Three-Phase V-I Measurement1/RConn1 -- Three-Phase Series RLC Load/LConn1 -- Three-Phase Breaker/LConn1
  Three-Phase Breaker/LConn2 -- Three-Phase V-I Measurement1/RConn2 -- Three-Phase Series RLC Load/LConn2
  Three-Phase Breaker/RConn3 -- Three-Phase V-I Measurement3/LConn3
  Three-Phase Breaker/RConn1 -- Three-Phase V-I Measurement3/LConn1
  Three-Phase V-I Measurement3/LConn2 -- Three-Phase Breaker/RConn2
  Three-Phase V-I Measurement1/LConn3 -- Controlled Current Source2/RConn1
  Three-Phase V-I Measurement1/LConn1 -- Controlled Current Source/RConn1
  Three-Phase V-I Measurement1/LConn2 -- Controlled Current Source1/RConn1
  C/RConn1 -- Three-Phase V-I Measurement3/RConn3
  B/RConn1 -- Three-Phase V-I Measurement3/RConn2
  A/RConn1 -- Three-Phase V-I Measurement3/RConn1
  Controlled Current Source2/LConn1 -- Controlled Current Source1/LConn1 -- Controlled Current Source/LConn1 -- Ground/LConn1

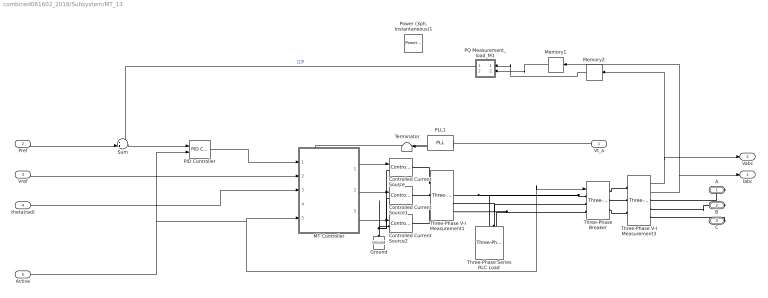
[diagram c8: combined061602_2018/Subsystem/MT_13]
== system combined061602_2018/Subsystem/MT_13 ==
  Vt_a : Inport
  Pref : Inport  Port=2
  Vref : Inport  Port=3
  theta(rad) : Inport  Port=4
  Active : Inport  Port=5
  Controlled Current Source : powerlib/Electrical Sources/Controlled Current Source  Initialize=on  Source_Type=AC  Amplitude=0  Phase=0  Frequency=0  Measurements=None
  Controlled Current Source1 : powerlib/Electrical Sources/Controlled Current Source  Initialize=on  Source_Type=AC  Amplitude=0  Phase=0  Frequency=0  Measurements=None
  Controlled Current Source2 : powerlib/Electrical Sources/Controlled Current Source  Initialize=on  Source_Type=AC  Amplitude=0  Phase=0  Frequency=0  Measurements=None
  Ground : powerlib/Elements/Ground  LConnTagsString=a
  MT Controller : MATLAB Function  TreatAsAtomicUnit=on
  Memory1 : Memory
  Memory2 : Memory
  PID Controller : simulink/Continuous/PID Controller  Controller=PI  Form=Parallel  TimeDomain=Continuous-time  SampleTime=-1  IntegratorMethod=Forward Euler  FilterMethod=Forward Euler  ControllerParametersSource=internal  P=0.01  I=0.2  D=0  UseFilter=on  N=100  TunerSelectOption=Transfer Function Based (PID Tuner App)  InitialConditionSource=internal  InitialConditionForIntegrator=0  InitialConditionForFilter=0  DifferentiatorICPrevScaledInput=0  ExternalReset=either  TrackingMode=off  Kt=1  LimitOutput=off  UpperSaturationLimit=inf  LowerSaturationLimit=-inf  LinearizeAsGain=on  AntiWindupMode=none  Kb=1  POutMin=[]  POutMax=[]  IOutMin=[]  IOutMax=[]  DOutMin=[]  DOutMax=[]  NOutMin=[]  NOutMax=[]  SumOutMin=[]  SumOutMax=[]  SaturationOutMin=[]  SaturationOutMax=[]  PParamMin=[]  PParamMax=[]  IParamMin=[]  IParamMax=[]  DParamMin=[]  DParamMax=[]  NParamMin=[]  NParamMax=[]  KbParamMin=[]  KbParamMax=[]  KtParamMin=[]  KtParamMax=[]  KbOutMin=[]  KbOutMax=[]  KtOutMin=[]  KtOutMax=[]  IntegratorOutMin=[]  IntegratorOutMax=[]  FilterOutMin=[]  FilterOutMax=[]  SumI1OutMin=[]  SumI1OutMax=[]  SumI2OutMin=[]  SumI2OutMax=[]  SumI3OutMin=[]  SumI3OutMax=[]  SumI4OutMin=[]  SumI4OutMax=[]  SumDOutMin=[]  SumDOutMax=[]  DifferentiatorOutMin=[]  DifferentiatorOutMax=[]  FilterDiffOutCoefMin=[]  FilterDiffOutCoefMax=[]  ReciprocalOutMin=[]  ReciprocalOutMax=[]  SumDenOutMin=[]  SumDenOutMax=[]  SumNumOutMin=[]  SumNumOutMax=[]  DivideOutMin=[]  DivideOutMax=[]  IntegratorContinuousStateAttributes=''  IntegratorStateMustResolveToSignalObject=off  IntegratorRTWStateStorageClass=Auto  FilterContinuousStateAttributes=''  FilterStateMustResolveToSignalObject=off  FilterRTWStateStorageClass=Auto  ParallelPVariant=InternalParameters  IdealPVariant=Disabled  IVariant=InternalParameters  DVariant=Disabled  IntegratorVariant=Continuous  SatVariant=Disabled  AWVariant=Passthrough  PCopyVariant=Disabled  TRVariant=Disabled  FdbkBlocksVariant=Forward  IdealPFdbkVariant=Disabled  SatFdbkVariant=Disabled  DerivativeFilterVariant=Disabled  NVariant=Disabled  NCopyVariant=Disabled_SignalSpec  FilterICVariant=Disabled  IntegratorICVariant=InternalICs  ExternalResetVariant=ExternalReset  TRSumVariant=Passthrough  SumFdbkVariant=Disabled  SumVariant=Sum_PI
  PLL1 : powerlib_meascontrol/PLL/PLL  Fmin=45  Par_Init=[0, 50]  ParK=[180, 3200, 1]  TcD=1e-4  MaxRateChangeFreq=12  FilterCutOffFreq=25  Ts=0  AGC=on
  PQ Measurement_load_M1 : Subsystem
  "Power (3ph, Instantaneous)1" : powerlib_meascontrol/Measurements/Power (3ph, Instantaneous)  Commented=on
  Sum : Sum  Inputs=-+|
  Terminator : Terminator
  Three-Phase Series RLC Load : powerlib/Elements/Three-Phase Series RLC Load  LConnTagsString=A|B|C  Configuration=Y (grounded)  NominalVoltage=400  Vabc=[1e3 1e3 1e3]  Vabcp=[1e3 1e3 1e3]  NominalFrequency=50  UnbalancedPower=off  ActivePower=10  InductivePower=0  CapacitivePower=0  Pabc=[10e3 9e3 11e3]  QLabc=[100 90 110]  QCabc=[100 90 110]  Pabcp=[10e3 9e3 11e3]  QLabcp=[100 90 110]  QCabcp=[100 90 110]  Measurements=None  LoadType=constant Z
  Three-Phase V-I Measurement1 : powerlib/Measurements/Three-Phase V-I Measurement  VoltageMeasurement=phase-to-ground  SetLabelV=off  LabelV=Vabc  Vpu=off  VpuLL=off  CurrentMeasurement=yes  SetLabelI=off  LabelI=Iabc  Ipu=off  Pbase=100e6  Vbase=500e3  OutputType=Complex  PhasorSimulation=off  PSBequivalent=0
  Three-Phase V-I Measurement3 : powerlib/Measurements/Three-Phase V-I Measurement  VoltageMeasurement=phase-to-ground  SetLabelV=off  LabelV=Vabc  Vpu=off  VpuLL=off  CurrentMeasurement=yes  SetLabelI=off  LabelI=Iabc  Ipu=off  Pbase=100e6  Vbase=500e3  OutputType=Complex  PhasorSimulation=off  PSBequivalent=0
  Three-Phase Breaker : powerlib/Elements/Three-Phase Breaker  InitialState=open  SwitchA=on  SwitchB=on  SwitchC=on  SwitchTimes=[2]  External=on  BreakerResistance=0.01  SnubberResistance=inf  SnubberCapacitance=0  Measurements=None
  A : PMIOPort  Side=Right
  B : PMIOPort  Port=2  Side=Right
  C : PMIOPort  Port=3  Side=Right
  Iabc : Outport
  Vabc : Outport  Port=2
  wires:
  MT Controller/1(ia) -> Controlled Current Source/1
  PLL1/2 -> MT Controller/4(wt)
  MT Controller/2(ib) -> Controlled Current Source1/1
  MT Controller/3(ic) -> Controlled Current Source2/1
  PLL1/1 -> Terminator/1
  Three-Phase V-I Measurement3/1 -> Memory2/1, Vabc/1
  Vt_a/1 -> PLL1/1
  Three-Phase V-I Measurement3/2 -> Memory1/1, Iabc/1
  Active/1 -> MT Controller/5(active), Three-Phase Breaker/1, PID Controller/2
  Sum/1 -> PID Controller/1
  Vref/1 -> MT Controller/2(Vref)
  Pref/1 -> Sum/2
  PID Controller/1 -> MT Controller/1(Pref)
  theta(rad)/1 -> MT Controller/3(theta)
  Memory1/1 -> PQ Measurement_load_M1/2(Iabc)
  Memory2/1 -> PQ Measurement_load_M1/1(Vabc)
  PQ Measurement_load_M1/1(P) -> Sum/1  "燃机P"
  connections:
  Ground/LConn1 -- Controlled Current Source/LConn1 -- Controlled Current Source1/LConn1 -- Controlled Current Source2/LConn1
  A/RConn1 -- Three-Phase V-I Measurement3/RConn1
  B/RConn1 -- Three-Phase V-I Measurement3/RConn2
  C/RConn1 -- Three-Phase V-I Measurement3/RConn3
  Three-Phase V-I Measurement1/LConn2 -- Controlled Current Source1/RConn1
  Three-Phase V-I Measurement1/LConn1 -- Controlled Current Source/RConn1
  Three-Phase V-I Measurement1/LConn3 -- Controlled Current Source2/RConn1
  Three-Phase V-I Measurement3/LConn2 -- Three-Phase Breaker/RConn2
  Three-Phase Breaker/RConn1 -- Three-Phase V-I Measurement3/LConn1
  Three-Phase Breaker/RConn3 -- Three-Phase V-I Measurement3/LConn3
  Three-Phase Series RLC Load/LConn2 -- Three-Phase V-I Measurement1/RConn2 -- Three-Phase Breaker/LConn2
  Three-Phase Breaker/LConn1 -- Three-Phase Series RLC Load/LConn1 -- Three-Phase V-I Measurement1/RConn1
  Three-Phase Breaker/LConn3 -- Three-Phase Series RLC Load/LConn3 -- Three-Phase V-I Measurement1/RConn3

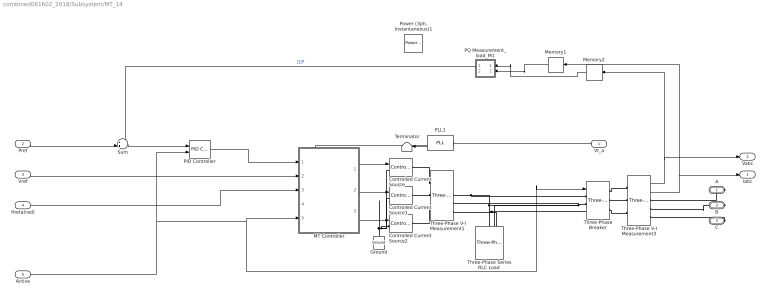
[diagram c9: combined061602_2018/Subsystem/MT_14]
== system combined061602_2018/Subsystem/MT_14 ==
  Vt_a : Inport
  Pref : Inport  Port=2
  Vref : Inport  Port=3
  theta(rad) : Inport  Port=4
  Active : Inport  Port=5
  Controlled Current Source : powerlib/Electrical Sources/Controlled Current Source  Initialize=on  Source_Type=AC  Amplitude=0  Phase=0  Frequency=0  Measurements=None
  Controlled Current Source1 : powerlib/Electrical Sources/Controlled Current Source  Initialize=on  Source_Type=AC  Amplitude=0  Phase=0  Frequency=0  Measurements=None
  Controlled Current Source2 : powerlib/Electrical Sources/Controlled Current Source  Initialize=on  Source_Type=AC  Amplitude=0  Phase=0  Frequency=0  Measurements=None
  Ground : powerlib/Elements/Ground  LConnTagsString=a
  MT Controller : MATLAB Function  TreatAsAtomicUnit=on
  Memory1 : Memory
  Memory2 : Memory
  PID Controller : simulink/Continuous/PID Controller  Controller=PI  Form=Parallel  TimeDomain=Continuous-time  SampleTime=-1  IntegratorMethod=Forward Euler  FilterMethod=Forward Euler  ControllerParametersSource=internal  P=0.01  I=0.2  D=0  UseFilter=on  N=100  TunerSelectOption=Transfer Function Based (PID Tuner App)  InitialConditionSource=internal  InitialConditionForIntegrator=0  InitialConditionForFilter=0  DifferentiatorICPrevScaledInput=0  ExternalReset=either  TrackingMode=off  Kt=1  LimitOutput=off  UpperSaturationLimit=inf  LowerSaturationLimit=-inf  LinearizeAsGain=on  AntiWindupMode=none  Kb=1  POutMin=[]  POutMax=[]  IOutMin=[]  IOutMax=[]  DOutMin=[]  DOutMax=[]  NOutMin=[]  NOutMax=[]  SumOutMin=[]  SumOutMax=[]  SaturationOutMin=[]  SaturationOutMax=[]  PParamMin=[]  PParamMax=[]  IParamMin=[]  IParamMax=[]  DParamMin=[]  DParamMax=[]  NParamMin=[]  NParamMax=[]  KbParamMin=[]  KbParamMax=[]  KtParamMin=[]  KtParamMax=[]  KbOutMin=[]  KbOutMax=[]  KtOutMin=[]  KtOutMax=[]  IntegratorOutMin=[]  IntegratorOutMax=[]  FilterOutMin=[]  FilterOutMax=[]  SumI1OutMin=[]  SumI1OutMax=[]  SumI2OutMin=[]  SumI2OutMax=[]  SumI3OutMin=[]  SumI3OutMax=[]  SumI4OutMin=[]  SumI4OutMax=[]  SumDOutMin=[]  SumDOutMax=[]  DifferentiatorOutMin=[]  DifferentiatorOutMax=[]  FilterDiffOutCoefMin=[]  FilterDiffOutCoefMax=[]  ReciprocalOutMin=[]  ReciprocalOutMax=[]  SumDenOutMin=[]  SumDenOutMax=[]  SumNumOutMin=[]  SumNumOutMax=[]  DivideOutMin=[]  DivideOutMax=[]  IntegratorContinuousStateAttributes=''  IntegratorStateMustResolveToSignalObject=off  IntegratorRTWStateStorageClass=Auto  FilterContinuousStateAttributes=''  FilterStateMustResolveToSignalObject=off  FilterRTWStateStorageClass=Auto  ParallelPVariant=InternalParameters  IdealPVariant=Disabled  IVariant=InternalParameters  DVariant=Disabled  IntegratorVariant=Continuous  SatVariant=Disabled  AWVariant=Passthrough  PCopyVariant=Disabled  TRVariant=Disabled  FdbkBlocksVariant=Forward  IdealPFdbkVariant=Disabled  SatFdbkVariant=Disabled  DerivativeFilterVariant=Disabled  NVariant=Disabled  NCopyVariant=Disabled_SignalSpec  FilterICVariant=Disabled  IntegratorICVariant=InternalICs  ExternalResetVariant=ExternalReset  TRSumVariant=Passthrough  SumFdbkVariant=Disabled  SumVariant=Sum_PI
  PLL1 : powerlib_meascontrol/PLL/PLL  Fmin=45  Par_Init=[0, 50]  ParK=[180, 3200, 1]  TcD=1e-4  MaxRateChangeFreq=12  FilterCutOffFreq=25  Ts=0  AGC=on
  PQ Measurement_load_M1 : Subsystem
  "Power (3ph, Instantaneous)1" : powerlib_meascontrol/Measurements/Power (3ph, Instantaneous)  Commented=on
  Sum : Sum  Inputs=-+|
  Terminator : Terminator
  Three-Phase Series RLC Load : powerlib/Elements/Three-Phase Series RLC Load  LConnTagsString=A|B|C  Configuration=Y (grounded)  NominalVoltage=400  Vabc=[1e3 1e3 1e3]  Vabcp=[1e3 1e3 1e3]  NominalFrequency=50  UnbalancedPower=off  ActivePower=10  InductivePower=0  CapacitivePower=0  Pabc=[10e3 9e3 11e3]  QLabc=[100 90 110]  QCabc=[100 90 110]  Pabcp=[10e3 9e3 11e3]  QLabcp=[100 90 110]  QCabcp=[100 90 110]  Measurements=None  LoadType=constant Z
  Three-Phase V-I Measurement1 : powerlib/Measurements/Three-Phase V-I Measurement  VoltageMeasurement=phase-to-ground  SetLabelV=off  LabelV=Vabc  Vpu=off  VpuLL=off  CurrentMeasurement=yes  SetLabelI=off  LabelI=Iabc  Ipu=off  Pbase=100e6  Vbase=500e3  OutputType=Complex  PhasorSimulation=off  PSBequivalent=0
  Three-Phase V-I Measurement3 : powerlib/Measurements/Three-Phase V-I Measurement  VoltageMeasurement=phase-to-ground  SetLabelV=off  LabelV=Vabc  Vpu=off  VpuLL=off  CurrentMeasurement=yes  SetLabelI=off  LabelI=Iabc  Ipu=off  Pbase=100e6  Vbase=500e3  OutputType=Complex  PhasorSimulation=off  PSBequivalent=0
  Three-Phase Breaker : powerlib/Elements/Three-Phase Breaker  InitialState=open  SwitchA=on  SwitchB=on  SwitchC=on  SwitchTimes=[2]  External=on  BreakerResistance=0.01  SnubberResistance=inf  SnubberCapacitance=0  Measurements=None
  A : PMIOPort  Side=Right
  B : PMIOPort  Port=2  Side=Right
  C : PMIOPort  Port=3  Side=Right
  Iabc : Outport
  Vabc : Outport  Port=2
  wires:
  PQ Measurement_load_M1/1(P) -> Sum/1  "燃机P"
  Memory2/1 -> PQ Measurement_load_M1/1(Vabc)
  Memory1/1 -> PQ Measurement_load_M1/2(Iabc)
  theta(rad)/1 -> MT Controller/3(theta)
  PID Controller/1 -> MT Controller/1(Pref)
  Pref/1 -> Sum/2
  Vref/1 -> MT Controller/2(Vref)
  Sum/1 -> PID Controller/1
  Active/1 -> PID Controller/2, Three-Phase Breaker/1, MT Controller/5(active)
  Three-Phase V-I Measurement3/2 -> Iabc/1, Memory1/1
  Vt_a/1 -> PLL1/1
  Three-Phase V-I Measurement3/1 -> Vabc/1, Memory2/1
  PLL1/1 -> Terminator/1
  MT Controller/3(ic) -> Controlled Current Source2/1
  MT Controller/2(ib) -> Controlled Current Source1/1
  PLL1/2 -> MT Controller/4(wt)
  MT Controller/1(ia) -> Controlled Current Source/1
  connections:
  Three-Phase V-I Measurement1/RConn3 -- Three-Phase Series RLC Load/LConn3 -- Three-Phase Breaker/LConn3
  Three-Phase V-I Measurement1/RConn1 -- Three-Phase Series RLC Load/LConn1 -- Three-Phase Breaker/LConn1
  Three-Phase Breaker/LConn2 -- Three-Phase V-I Measurement1/RConn2 -- Three-Phase Series RLC Load/LConn2
  Three-Phase Breaker/RConn3 -- Three-Phase V-I Measurement3/LConn3
  Three-Phase Breaker/RConn1 -- Three-Phase V-I Measurement3/LConn1
  Three-Phase V-I Measurement3/LConn2 -- Three-Phase Breaker/RConn2
  Three-Phase V-I Measurement1/LConn3 -- Controlled Current Source2/RConn1
  Three-Phase V-I Measurement1/LConn1 -- Controlled Current Source/RConn1
  Three-Phase V-I Measurement1/LConn2 -- Controlled Current Source1/RConn1
  C/RConn1 -- Three-Phase V-I Measurement3/RConn3
  B/RConn1 -- Three-Phase V-I Measurement3/RConn2
  A/RConn1 -- Three-Phase V-I Measurement3/RConn1
  Controlled Current Source2/LConn1 -- Controlled Current Source1/LConn1 -- Controlled Current Source/LConn1 -- Ground/LConn1

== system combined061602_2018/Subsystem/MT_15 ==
  Vt_a : Inport
  Pref : Inport  Port=2
  Vref : Inport  Port=3
  theta(rad) : Inport  Port=4
  Active : Inport  Port=5
  Controlled Current Source : powerlib/Electrical Sources/Controlled Current Source  Initialize=on  Source_Type=AC  Amplitude=0  Phase=0  Frequency=0  Measurements=None
  Controlled Current Source1 : powerlib/Electrical Sources/Controlled Current Source  Initialize=on  Source_Type=AC  Amplitude=0  Phase=0  Frequency=0  Measurements=None
  Controlled Current Source2 : powerlib/Electrical Sources/Controlled Current Source  Initialize=on  Source_Type=AC  Amplitude=0  Phase=0  Frequency=0  Measurements=None
  Ground : powerlib/Elements/Ground  LConnTagsString=a
  MT Controller : MATLAB Function  TreatAsAtomicUnit=on
  Memory1 : Memory
  Memory2 : Memory
  PID Controller : simulink/Continuous/PID Controller  Controller=PI  Form=Parallel  TimeDomain=Continuous-time  SampleTime=-1  IntegratorMethod=Forward Euler  FilterMethod=Forward Euler  ControllerParametersSource=internal  P=0.01  I=0.2  D=0  UseFilter=on  N=100  TunerSelectOption=Transfer Function Based (PID Tuner App)  InitialConditionSource=internal  InitialConditionForIntegrator=0  InitialConditionForFilter=0  DifferentiatorICPrevScaledInput=0  ExternalReset=either  TrackingMode=off  Kt=1  LimitOutput=off  UpperSaturationLimit=inf  LowerSaturationLimit=-inf  LinearizeAsGain=on  AntiWindupMode=none  Kb=1  POutMin=[]  POutMax=[]  IOutMin=[]  IOutMax=[]  DOutMin=[]  DOutMax=[]  NOutMin=[]  NOutMax=[]  SumOutMin=[]  SumOutMax=[]  SaturationOutMin=[]  SaturationOutMax=[]  PParamMin=[]  PParamMax=[]  IParamMin=[]  IParamMax=[]  DParamMin=[]  DParamMax=[]  NParamMin=[]  NParamMax=[]  KbParamMin=[]  KbParamMax=[]  KtParamMin=[]  KtParamMax=[]  KbOutMin=[]  KbOutMax=[]  KtOutMin=[]  KtOutMax=[]  IntegratorOutMin=[]  IntegratorOutMax=[]  FilterOutMin=[]  FilterOutMax=[]  SumI1OutMin=[]  SumI1OutMax=[]  SumI2OutMin=[]  SumI2OutMax=[]  SumI3OutMin=[]  SumI3OutMax=[]  SumI4OutMin=[]  SumI4OutMax=[]  SumDOutMin=[]  SumDOutMax=[]  DifferentiatorOutMin=[]  DifferentiatorOutMax=[]  FilterDiffOutCoefMin=[]  FilterDiffOutCoefMax=[]  ReciprocalOutMin=[]  ReciprocalOutMax=[]  SumDenOutMin=[]  SumDenOutMax=[]  SumNumOutMin=[]  SumNumOutMax=[]  DivideOutMin=[]  DivideOutMax=[]  IntegratorContinuousStateAttributes=''  IntegratorStateMustResolveToSignalObject=off  IntegratorRTWStateStorageClass=Auto  FilterContinuousStateAttributes=''  FilterStateMustResolveToSignalObject=off  FilterRTWStateStorageClass=Auto  ParallelPVariant=InternalParameters  IdealPVariant=Disabled  IVariant=InternalParameters  DVariant=Disabled  IntegratorVariant=Continuous  SatVariant=Disabled  AWVariant=Passthrough  PCopyVariant=Disabled  TRVariant=Disabled  FdbkBlocksVariant=Forward  IdealPFdbkVariant=Disabled  SatFdbkVariant=Disabled  DerivativeFilterVariant=Disabled  NVariant=Disabled  NCopyVariant=Disabled_SignalSpec  FilterICVariant=Disabled  IntegratorICVariant=InternalICs  ExternalResetVariant=ExternalReset  TRSumVariant=Passthrough  SumFdbkVariant=Disabled  SumVariant=Sum_PI
  PLL1 : powerlib_meascontrol/PLL/PLL  Fmin=45  Par_Init=[0, 50]  ParK=[180, 3200, 1]  TcD=1e-4  MaxRateChangeFreq=12  FilterCutOffFreq=25  Ts=0  AGC=on
  PQ Measurement_load_M1 : Subsystem
  "Power (3ph, Instantaneous)1" : powerlib_meascontrol/Measurements/Power (3ph, Instantaneous)  Commented=on
  Sum : Sum  Inputs=-+|
  Terminator : Terminator
  Three-Phase Series RLC Load : powerlib/Elements/Three-Phase Series RLC Load  LConnTagsString=A|B|C  Configuration=Y (grounded)  NominalVoltage=400  Vabc=[1e3 1e3 1e3]  Vabcp=[1e3 1e3 1e3]  NominalFrequency=50  UnbalancedPower=off  ActivePower=10  InductivePower=0  CapacitivePower=0  Pabc=[10e3 9e3 11e3]  QLabc=[100 90 110]  QCabc=[100 90 110]  Pabcp=[10e3 9e3 11e3]  QLabcp=[100 90 110]  QCabcp=[100 90 110]  Measurements=None  LoadType=constant Z
  Three-Phase V-I Measurement1 : powerlib/Measurements/Three-Phase V-I Measurement  VoltageMeasurement=phase-to-ground  SetLabelV=off  LabelV=Vabc  Vpu=off  VpuLL=off  CurrentMeasurement=yes  SetLabelI=off  LabelI=Iabc  Ipu=off  Pbase=100e6  Vbase=500e3  OutputType=Complex  PhasorSimulation=off  PSBequivalent=0
  Three-Phase V-I Measurement3 : powerlib/Measurements/Three-Phase V-I Measurement  VoltageMeasurement=phase-to-ground  SetLabelV=off  LabelV=Vabc  Vpu=off  VpuLL=off  CurrentMeasurement=yes  SetLabelI=off  LabelI=Iabc  Ipu=off  Pbase=100e6  Vbase=500e3  OutputType=Complex  PhasorSimulation=off  PSBequivalent=0
  Three-Phase Breaker : powerlib/Elements/Three-Phase Breaker  InitialState=open  SwitchA=on  SwitchB=on  SwitchC=on  SwitchTimes=[2]  External=on  BreakerResistance=0.01  SnubberResistance=inf  SnubberCapacitance=0  Measurements=None
  A : PMIOPort  Side=Right
  B : PMIOPort  Port=2  Side=Right
  C : PMIOPort  Port=3  Side=Right
  Iabc : Outport
  Vabc : Outport  Port=2
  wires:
  MT Controller/1(ia) -> Controlled Current Source/1
  PLL1/2 -> MT Controller/4(wt)
  MT Controller/2(ib) -> Controlled Current Source1/1
  MT Controller/3(ic) -> Controlled Current Source2/1
  PLL1/1 -> Terminator/1
  Three-Phase V-I Measurement3/1 -> Memory2/1, Vabc/1
  Vt_a/1 -> PLL1/1
  Three-Phase V-I Measurement3/2 -> Memory1/1, Iabc/1
  Active/1 -> MT Controller/5(active), Three-Phase Breaker/1, PID Controller/2
  Sum/1 -> PID Controller/1
  Vref/1 -> MT Controller/2(Vref)
  Pref/1 -> Sum/2
  PID Controller/1 -> MT Controller/1(Pref)
  theta(rad)/1 -> MT Controller/3(theta)
  Memory1/1 -> PQ Measurement_load_M1/2(Iabc)
  Memory2/1 -> PQ Measurement_load_M1/1(Vabc)
  PQ Measurement_load_M1/1(P) -> Sum/1  "燃机P"
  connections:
  Ground/LConn1 -- Controlled Current Source/LConn1 -- Controlled Current Source1/LConn1 -- Controlled Current Source2/LConn1
  A/RConn1 -- Three-Phase V-I Measurement3/RConn1
  B/RConn1 -- Three-Phase V-I Measurement3/RConn2
  C/RConn1 -- Three-Phase V-I Measurement3/RConn3
  Three-Phase V-I Measurement1/LConn2 -- Controlled Current Source1/RConn1
  Three-Phase V-I Measurement1/LConn1 -- Controlled Current Source/RConn1
  Three-Phase V-I Measurement1/LConn3 -- Controlled Current Source2/RConn1
  Three-Phase V-I Measurement3/LConn2 -- Three-Phase Breaker/RConn2
  Three-Phase Breaker/RConn1 -- Three-Phase V-I Measurement3/LConn1
  Three-Phase Breaker/RConn3 -- Three-Phase V-I Measurement3/LConn3
  Three-Phase Series RLC Load/LConn2 -- Three-Phase V-I Measurement1/RConn2 -- Three-Phase Breaker/LConn2
  Three-Phase Breaker/LConn1 -- Three-Phase Series RLC Load/LConn1 -- Three-Phase V-I Measurement1/RConn1
  Three-Phase Breaker/LConn3 -- Three-Phase Series RLC Load/LConn3 -- Three-Phase V-I Measurement1/RConn3

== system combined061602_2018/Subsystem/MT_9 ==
  Vt_a : Inport
  Pref : Inport  Port=2
  Vref : Inport  Port=3
  theta(rad) : Inport  Port=4
  Active : Inport  Port=5
  Controlled Current Source : powerlib/Electrical Sources/Controlled Current Source  Initialize=on  Source_Type=AC  Amplitude=0  Phase=0  Frequency=0  Measurements=None
  Controlled Current Source1 : powerlib/Electrical Sources/Controlled Current Source  Initialize=on  Source_Type=AC  Amplitude=0  Phase=0  Frequency=0  Measurements=None
  Controlled Current Source2 : powerlib/Electrical Sources/Controlled Current Source  Initialize=on  Source_Type=AC  Amplitude=0  Phase=0  Frequency=0  Measurements=None
  Ground : powerlib/Elements/Ground  LConnTagsString=a
  MT Controller : MATLAB Function  TreatAsAtomicUnit=on
  Memory1 : Memory
  Memory2 : Memory
  PID Controller : simulink/Continuous/PID Controller  Controller=PI  Form=Parallel  TimeDomain=Continuous-time  SampleTime=-1  IntegratorMethod=Forward Euler  FilterMethod=Forward Euler  ControllerParametersSource=internal  P=0.01  I=0.2  D=0  UseFilter=on  N=100  TunerSelectOption=Transfer Function Based (PID Tuner App)  InitialConditionSource=internal  InitialConditionForIntegrator=0  InitialConditionForFilter=0  DifferentiatorICPrevScaledInput=0  ExternalReset=either  TrackingMode=off  Kt=1  LimitOutput=off  UpperSaturationLimit=inf  LowerSaturationLimit=-inf  LinearizeAsGain=on  AntiWindupMode=none  Kb=1  POutMin=[]  POutMax=[]  IOutMin=[]  IOutMax=[]  DOutMin=[]  DOutMax=[]  NOutMin=[]  NOutMax=[]  SumOutMin=[]  SumOutMax=[]  SaturationOutMin=[]  SaturationOutMax=[]  PParamMin=[]  PParamMax=[]  IParamMin=[]  IParamMax=[]  DParamMin=[]  DParamMax=[]  NParamMin=[]  NParamMax=[]  KbParamMin=[]  KbParamMax=[]  KtParamMin=[]  KtParamMax=[]  KbOutMin=[]  KbOutMax=[]  KtOutMin=[]  KtOutMax=[]  IntegratorOutMin=[]  IntegratorOutMax=[]  FilterOutMin=[]  FilterOutMax=[]  SumI1OutMin=[]  SumI1OutMax=[]  SumI2OutMin=[]  SumI2OutMax=[]  SumI3OutMin=[]  SumI3OutMax=[]  SumI4OutMin=[]  SumI4OutMax=[]  SumDOutMin=[]  SumDOutMax=[]  DifferentiatorOutMin=[]  DifferentiatorOutMax=[]  FilterDiffOutCoefMin=[]  FilterDiffOutCoefMax=[]  ReciprocalOutMin=[]  ReciprocalOutMax=[]  SumDenOutMin=[]  SumDenOutMax=[]  SumNumOutMin=[]  SumNumOutMax=[]  DivideOutMin=[]  DivideOutMax=[]  IntegratorContinuousStateAttributes=''  IntegratorStateMustResolveToSignalObject=off  IntegratorRTWStateStorageClass=Auto  FilterContinuousStateAttributes=''  FilterStateMustResolveToSignalObject=off  FilterRTWStateStorageClass=Auto  ParallelPVariant=InternalParameters  IdealPVariant=Disabled  IVariant=InternalParameters  DVariant=Disabled  IntegratorVariant=Continuous  SatVariant=Disabled  AWVariant=Passthrough  PCopyVariant=Disabled  TRVariant=Disabled  FdbkBlocksVariant=Forward  IdealPFdbkVariant=Disabled  SatFdbkVariant=Disabled  DerivativeFilterVariant=Disabled  NVariant=Disabled  NCopyVariant=Disabled_SignalSpec  FilterICVariant=Disabled  IntegratorICVariant=InternalICs  ExternalResetVariant=ExternalReset  TRSumVariant=Passthrough  SumFdbkVariant=Disabled  SumVariant=Sum_PI
  PLL1 : powerlib_meascontrol/PLL/PLL  Fmin=45  Par_Init=[0, 50]  ParK=[180, 3200, 1]  TcD=1e-4  MaxRateChangeFreq=12  FilterCutOffFreq=25  Ts=0  AGC=on
  PQ Measurement_load_M1 : Subsystem
  "Power (3ph, Instantaneous)1" : powerlib_meascontrol/Measurements/Power (3ph, Instantaneous)  Commented=on
  Sum : Sum  Inputs=-+|
  Terminator : Terminator
  Three-Phase Series RLC Load : powerlib/Elements/Three-Phase Series RLC Load  LConnTagsString=A|B|C  Configuration=Y (grounded)  NominalVoltage=400  Vabc=[1e3 1e3 1e3]  Vabcp=[1e3 1e3 1e3]  NominalFrequency=50  UnbalancedPower=off  ActivePower=10  InductivePower=0  CapacitivePower=0  Pabc=[10e3 9e3 11e3]  QLabc=[100 90 110]  QCabc=[100 90 110]  Pabcp=[10e3 9e3 11e3]  QLabcp=[100 90 110]  QCabcp=[100 90 110]  Measurements=None  LoadType=constant Z
  Three-Phase V-I Measurement1 : powerlib/Measurements/Three-Phase V-I Measurement  VoltageMeasurement=phase-to-ground  SetLabelV=off  LabelV=Vabc  Vpu=off  VpuLL=off  CurrentMeasurement=yes  SetLabelI=off  LabelI=Iabc  Ipu=off  Pbase=100e6  Vbase=500e3  OutputType=Complex  PhasorSimulation=off  PSBequivalent=0
  Three-Phase V-I Measurement3 : powerlib/Measurements/Three-Phase V-I Measurement  VoltageMeasurement=phase-to-ground  SetLabelV=off  LabelV=Vabc  Vpu=off  VpuLL=off  CurrentMeasurement=yes  SetLabelI=off  LabelI=Iabc  Ipu=off  Pbase=100e6  Vbase=500e3  OutputType=Complex  PhasorSimulation=off  PSBequivalent=0
  Three-Phase Breaker : powerlib/Elements/Three-Phase Breaker  InitialState=open  SwitchA=on  SwitchB=on  SwitchC=on  SwitchTimes=[2]  External=on  BreakerResistance=0.01  SnubberResistance=inf  SnubberCapacitance=0  Measurements=None
  A : PMIOPort  Side=Right
  B : PMIOPort  Port=2  Side=Right
  C : PMIOPort  Port=3  Side=Right
  Iabc : Outport
  Vabc : Outport  Port=2
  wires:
  MT Controller/1(ia) -> Controlled Current Source/1
  PLL1/2 -> MT Controller/4(wt)
  MT Controller/2(ib) -> Controlled Current Source1/1
  MT Controller/3(ic) -> Controlled Current Source2/1
  PLL1/1 -> Terminator/1
  Three-Phase V-I Measurement3/1 -> Memory2/1, Vabc/1
  Vt_a/1 -> PLL1/1
  Three-Phase V-I Measurement3/2 -> Memory1/1, Iabc/1
  Active/1 -> MT Controller/5(active), Three-Phase Breaker/1, PID Controller/2
  Sum/1 -> PID Controller/1
  Vref/1 -> MT Controller/2(Vref)
  Pref/1 -> Sum/2
  PID Controller/1 -> MT Controller/1(Pref)
  theta(rad)/1 -> MT Controller/3(theta)
  Memory1/1 -> PQ Measurement_load_M1/2(Iabc)
  Memory2/1 -> PQ Measurement_load_M1/1(Vabc)
  PQ Measurement_load_M1/1(P) -> Sum/1  "燃机P"
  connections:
  Ground/LConn1 -- Controlled Current Source/LConn1 -- Controlled Current Source1/LConn1 -- Controlled Current Source2/LConn1
  A/RConn1 -- Three-Phase V-I Measurement3/RConn1
  B/RConn1 -- Three-Phase V-I Measurement3/RConn2
  C/RConn1 -- Three-Phase V-I Measurement3/RConn3
  Three-Phase V-I Measurement1/LConn2 -- Controlled Current Source1/RConn1
  Three-Phase V-I Measurement1/LConn1 -- Controlled Current Source/RConn1
  Three-Phase V-I Measurement1/LConn3 -- Controlled Current Source2/RConn1
  Three-Phase V-I Measurement3/LConn2 -- Three-Phase Breaker/RConn2
  Three-Phase Breaker/RConn1 -- Three-Phase V-I Measurement3/LConn1
  Three-Phase Breaker/RConn3 -- Three-Phase V-I Measurement3/LConn3
  Three-Phase Series RLC Load/LConn2 -- Three-Phase V-I Measurement1/RConn2 -- Three-Phase Breaker/LConn2
  Three-Phase Breaker/LConn1 -- Three-Phase Series RLC Load/LConn1 -- Three-Phase V-I Measurement1/RConn1
  Three-Phase Breaker/LConn3 -- Three-Phase Series RLC Load/LConn3 -- Three-Phase V-I Measurement1/RConn3

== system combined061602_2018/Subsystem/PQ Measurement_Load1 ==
  Vabc : Inport
  Iabc : Inport  Port=2
  Power : powerlib_meascontrol/Measurements/Power  Freq=50  Vinit=[1, 0]  Iinit=[1, 0]  Ts=0
  Sum of Elements : Sum  Inputs=+
  Sum of Elements1 : Sum  Inputs=+
  P : Outport
  Q : Outport  Port=2
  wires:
  Power/2 -> Sum of Elements1/1
  Sum of Elements1/1 -> Q/1
  Sum of Elements/1 -> P/1
  Iabc/1 -> Power/2
  Vabc/1 -> Power/1
  Power/1 -> Sum of Elements/1

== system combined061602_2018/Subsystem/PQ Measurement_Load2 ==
  Vabc : Inport
  Iabc : Inport  Port=2
  Power : powerlib_meascontrol/Measurements/Power  Freq=50  Vinit=[1, 0]  Iinit=[1, 0]  Ts=0
  Sum of Elements : Sum  Inputs=+
  Sum of Elements1 : Sum  Inputs=+
  P : Outport
  Q : Outport  Port=2
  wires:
  Power/1 -> Sum of Elements/1
  Vabc/1 -> Power/1
  Iabc/1 -> Power/2
  Sum of Elements/1 -> P/1
  Sum of Elements1/1 -> Q/1
  Power/2 -> Sum of Elements1/1

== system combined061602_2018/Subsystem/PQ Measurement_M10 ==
  Vabc : Inport
  Iabc : Inport  Port=2
  Power : powerlib_meascontrol/Measurements/Power  Freq=50  Vinit=[1, 0]  Iinit=[1, 0]  Ts=0
  Sum of Elements : Sum  Inputs=+
  Sum of Elements1 : Sum  Inputs=+
  P : Outport
  Q : Outport  Port=2
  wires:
  Power/2 -> Sum of Elements1/1
  Sum of Elements1/1 -> Q/1
  Sum of Elements/1 -> P/1
  Iabc/1 -> Power/2
  Vabc/1 -> Power/1
  Power/1 -> Sum of Elements/1

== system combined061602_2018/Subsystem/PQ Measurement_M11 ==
  Vabc : Inport
  Iabc : Inport  Port=2
  Power : powerlib_meascontrol/Measurements/Power  Freq=50  Vinit=[1, 0]  Iinit=[1, 0]  Ts=0
  Sum of Elements : Sum  Inputs=+
  Sum of Elements1 : Sum  Inputs=+
  P : Outport
  Q : Outport  Port=2
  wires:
  Power/1 -> Sum of Elements/1
  Vabc/1 -> Power/1
  Iabc/1 -> Power/2
  Sum of Elements/1 -> P/1
  Sum of Elements1/1 -> Q/1
  Power/2 -> Sum of Elements1/1

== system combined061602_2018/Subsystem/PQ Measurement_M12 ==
  Vabc : Inport
  Iabc : Inport  Port=2
  Power : powerlib_meascontrol/Measurements/Power  Freq=50  Vinit=[1, 0]  Iinit=[1, 0]  Ts=0
  Sum of Elements : Sum  Inputs=+
  Sum of Elements1 : Sum  Inputs=+
  P : Outport
  Q : Outport  Port=2
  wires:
  Power/2 -> Sum of Elements1/1
  Sum of Elements1/1 -> Q/1
  Sum of Elements/1 -> P/1
  Iabc/1 -> Power/2
  Vabc/1 -> Power/1
  Power/1 -> Sum of Elements/1

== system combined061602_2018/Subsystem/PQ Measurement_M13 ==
  Vabc : Inport
  Iabc : Inport  Port=2
  Power : powerlib_meascontrol/Measurements/Power  Freq=50  Vinit=[1, 0]  Iinit=[1, 0]  Ts=0
  Sum of Elements : Sum  Inputs=+
  Sum of Elements1 : Sum  Inputs=+
  P : Outport
  Q : Outport  Port=2
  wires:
  Power/1 -> Sum of Elements/1
  Vabc/1 -> Power/1
  Iabc/1 -> Power/2
  Sum of Elements/1 -> P/1
  Sum of Elements1/1 -> Q/1
  Power/2 -> Sum of Elements1/1
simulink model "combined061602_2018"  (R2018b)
settings: Solver=ode5  StartTime=0.0  StopTime=inf  FixedStep=1e-5  RelTol=1e-3
libraries: powerlib x156, powerlib_meascontrol x64, simulink x32, dspsigops x2
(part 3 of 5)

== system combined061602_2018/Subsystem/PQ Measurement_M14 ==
  Vabc : Inport
  Iabc : Inport  Port=2
  Power : powerlib_meascontrol/Measurements/Power  Freq=50  Vinit=[1, 0]  Iinit=[1, 0]  Ts=0
  Sum of Elements : Sum  Inputs=+
  Sum of Elements1 : Sum  Inputs=+
  P : Outport
  Q : Outport  Port=2
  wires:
  Power/2 -> Sum of Elements1/1
  Sum of Elements1/1 -> Q/1
  Sum of Elements/1 -> P/1
  Iabc/1 -> Power/2
  Vabc/1 -> Power/1
  Power/1 -> Sum of Elements/1

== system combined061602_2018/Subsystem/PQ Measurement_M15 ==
  Vabc : Inport
  Iabc : Inport  Port=2
  Power : powerlib_meascontrol/Measurements/Power  Freq=50  Vinit=[1, 0]  Iinit=[1, 0]  Ts=0
  Sum of Elements : Sum  Inputs=+
  Sum of Elements1 : Sum  Inputs=+
  P : Outport
  Q : Outport  Port=2
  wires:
  Power/1 -> Sum of Elements/1
  Vabc/1 -> Power/1
  Iabc/1 -> Power/2
  Sum of Elements/1 -> P/1
  Sum of Elements1/1 -> Q/1
  Power/2 -> Sum of Elements1/1

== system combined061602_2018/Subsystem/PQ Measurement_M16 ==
  Vabc : Inport
  Iabc : Inport  Port=2
  Power : powerlib_meascontrol/Measurements/Power  Freq=50  Vinit=[1, 0]  Iinit=[1, 0]  Ts=0
  Sum of Elements : Sum  Inputs=+
  Sum of Elements1 : Sum  Inputs=+
  P : Outport
  Q : Outport  Port=2
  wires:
  Power/2 -> Sum of Elements1/1
  Sum of Elements1/1 -> Q/1
  Sum of Elements/1 -> P/1
  Iabc/1 -> Power/2
  Vabc/1 -> Power/1
  Power/1 -> Sum of Elements/1

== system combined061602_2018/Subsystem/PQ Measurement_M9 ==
  Vabc : Inport
  Iabc : Inport  Port=2
  Power : powerlib_meascontrol/Measurements/Power  Freq=50  Vinit=[1, 0]  Iinit=[1, 0]  Ts=0
  Sum of Elements : Sum  Inputs=+
  Sum of Elements1 : Sum  Inputs=+
  P : Outport
  Q : Outport  Port=2
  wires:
  Power/1 -> Sum of Elements/1
  Vabc/1 -> Power/1
  Iabc/1 -> Power/2
  Sum of Elements/1 -> P/1
  Sum of Elements1/1 -> Q/1
  Power/2 -> Sum of Elements1/1

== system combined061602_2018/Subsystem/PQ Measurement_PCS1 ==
  Vabc : Inport
  Iabc : Inport  Port=2
  Power : powerlib_meascontrol/Measurements/Power  Freq=50  Vinit=[1, 0]  Iinit=[1, 0]  Ts=0
  Sum of Elements : Sum  Inputs=+
  Sum of Elements1 : Sum  Inputs=+
  P : Outport
  Q : Outport  Port=2
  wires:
  Power/2 -> Sum of Elements1/1
  Sum of Elements1/1 -> Q/1
  Sum of Elements/1 -> P/1
  Iabc/1 -> Power/2
  Vabc/1 -> Power/1
  Power/1 -> Sum of Elements/1

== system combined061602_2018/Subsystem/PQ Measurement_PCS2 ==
  Vabc : Inport
  Iabc : Inport  Port=2
  Power : powerlib_meascontrol/Measurements/Power  Freq=50  Vinit=[1, 0]  Iinit=[1, 0]  Ts=0
  Sum of Elements : Sum  Inputs=+
  Sum of Elements1 : Sum  Inputs=+
  P : Outport
  Q : Outport  Port=2
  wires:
  Power/1 -> Sum of Elements/1
  Vabc/1 -> Power/1
  Iabc/1 -> Power/2
  Sum of Elements/1 -> P/1
  Sum of Elements1/1 -> Q/1
  Power/2 -> Sum of Elements1/1

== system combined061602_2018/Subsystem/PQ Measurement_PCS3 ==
  Vabc : Inport
  Iabc : Inport  Port=2
  Power : powerlib_meascontrol/Measurements/Power  Freq=50  Vinit=[1, 0]  Iinit=[1, 0]  Ts=0
  Sum of Elements : Sum  Inputs=+
  Sum of Elements1 : Sum  Inputs=+
  P : Outport
  Q : Outport  Port=2
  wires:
  Power/2 -> Sum of Elements1/1
  Sum of Elements1/1 -> Q/1
  Sum of Elements/1 -> P/1
  Iabc/1 -> Power/2
  Vabc/1 -> Power/1
  Power/1 -> Sum of Elements/1

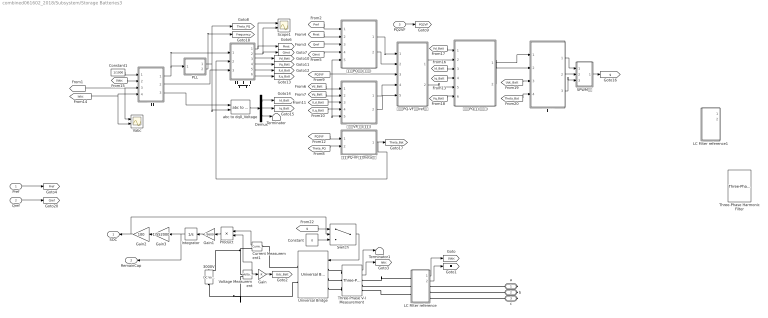
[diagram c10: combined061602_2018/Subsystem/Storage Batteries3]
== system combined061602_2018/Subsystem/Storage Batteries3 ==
  Pref : Inport
  Qref : Inport  Port=2
  PQ2VF : Inport  Port=3
  3000V : powerlib/Electrical Sources/DC Voltage Source  Amplitude=3000  Measurements=None
  Constant : Constant  Value=0
  Constant1 : Constant  Value=1/1000
  Current Measurement1 : powerlib/Measurements/Current Measurement  PhasorSimulation=off  OutputType=Complex  PSBequivalent=0
  Demux : Demux  Outputs=3
  Gain : Gain
  Gain1 : Gain  Gain=1/3600
  Gain2 : Gain  Gain=100  ParamDataTypeStr=double
  Gain3 : Gain  Gain=1/552000
  Integrator : Integrator  InitialCondition=552000*0.5  LimitOutput=on  UpperSaturationLimit=552000  LowerSaturationLimit=0
  LC Filter reference : Subsystem
  LC Filter reference1 : Subsystem  Commented=on
  PLL : Subsystem
  Product : Product
  SPWM控制 : Subsystem
  Scope1 : Scope  NumInputPorts=2
  Switch : Switch  Criteria=u2 > Threshold  Threshold=5
  Terminator : Terminator
  Terminator1 : Terminator
  Three-Phase Harmonic Filter : powerlib/Elements/Three-Phase Harmonic Filter  Commented=on  LConnTagsString=A|B|C  FilterType=Double-tuned  FilterConnection=Y (grounded)  ParNom=[400 50]  Qc=1000  Fr=[5*60]  Frd=[5*50 7*50]  Q=16  Measurements=None
  Three-Phase V-I Measurement : powerlib/Measurements/Three-Phase V-I Measurement  VoltageMeasurement=phase-to-ground  SetLabelV=off  LabelV=Vabc  Vpu=off  VpuLL=off  CurrentMeasurement=yes  SetLabelI=off  LabelI=Iabc  Ipu=off  Pbase=100e6  Vbase=500e3  OutputType=Complex  PhasorSimulation=off  PSBequivalent=0
  Universal Bridge : powerlib/Power Electronics/Universal Bridge  Arms=3  SnubberResistance=100000000  SnubberCapacitance=inf  Device=IGBT / Diodes  Ron=5e-3  Lon=0  ForwardVoltages="[  0  0  ]"  ForwardVoltage=0  GTOparameters=[ 10e-6 , 20e-6 ]  IGBTparameters=[ 1e-6 , 2e-6 ]  Measurements=None  Measurements_2=None  converterType=Rectifier
  Vabc : Scope  NumInputPorts=2
  Voltage Measurement : powerlib/Measurements/Voltage Measurement  PhasorSimulation=off  OutputType=Complex  PSBequivalent=0
  abc to dq0_Voltage : powerlib_meascontrol/Transformations/abc to dq0  Alignment=90 degrees behind phase A axis
  参考信号生成 : Subsystem
  变流器PQ-VF控制Iref切换 : Subsystem
  变流器PQ-VF控制theta变换 : Subsystem
  变流器PQ控制(电压环) : Subsystem
  变流器PQ控制(电流环) : Subsystem
  变流器VF控制(电压环) : Subsystem
  比例变换 : Subsystem
  电网电压定向，坐标变换 +瞬时功率计算 : Subsystem
  a : PMIOPort  Side=Right
  b : PMIOPort  Port=2  Side=Right
  c : PMIOPort  Port=3  Side=Right
  SOC : Outport
  RemainCap : Outport  Port=2
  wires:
  [Iq_Batt] -> 变流器PQ控制(电流环)/4(Iq_Batt)
  [Id_Batt] -> 变流器PQ控制(电流环)/3(Id_Batt)
  比例变换/3(Out3) -> abc to dq0_Voltage/1
  [Iabc] -> 比例变换/4(In3), Vabc/2
  PQ2VF/1 -> [PQ2VF]
  Qref/1 -> [Qref]
  Pref/1 -> [Pref]
  Three-Phase V-I Measurement/1 -> Terminator1/1
  Constant1/1 -> 比例变换/1(proportion)
  电网电压定向，坐标变换 +瞬时功率计算/6(ILq) -> [ILq_Batt]
  [PQ2VF] -> 变流器PQ-VF控制theta变换/1(PQ2VF)
  Three-Phase V-I Measurement/2 -> [Iabc]
  电网电压定向，坐标变换 +瞬时功率计算/2(Qinst) -> [Qinst], Scope1/2
  [Theta_PQ] -> 变流器PQ-VF控制theta变换/2(theta_PQref)
  [Vd_Batt] -> 变流器PQ控制(电流环)/1(Vd_Batt)
  变流器PQ控制(电压环)/2(Iq_PQref) -> 变流器PQ-VF控制Iref切换/2(Iq_PQref)
  LC Filter reference/2(ILabc) -> [IL]
  [Udc_Batt] -> 参考信号生成/3(Vdc_Batt)
  PLL/1(wt) -> [Theta_PQ], abc to dq0_Voltage/2
  变流器VF控制(电压环)/1(Id_VFref) -> 变流器PQ-VF控制Iref切换/4(Id_VFref)
  [PQ2VF] -> 变流器PQ-VF控制Iref切换/3(PQ2VF), 变流器VF控制(电压环)/5(PQ2VF), 变流器PQ控制(电压环)/5(PQ2VF)
  [Uabc] -> 比例变换/2(In1)
  变流器PQ-VF控制Iref切换/2(Iqref) -> 变流器PQ控制(电流环)/5(Iq_ref)
  [ILd_Batt] -> 变流器VF控制(电压环)/3(ILd)
  比例变换/1(Out1) -> PLL/1(Uabc), 电网电压定向，坐标变换 +瞬时功率计算/1(Uabc)
  Demux/3 -> Terminator/1
  [IL] -> 比例变换/3(In2), Vabc/1
  Demux/2 -> [Iq_Batt]
  Switch/1 -> Universal Bridge/1
  变流器PQ控制(电流环)/1(Vd_ref) -> 参考信号生成/1(Vd_ref)
  Gain/1 -> [Udc_Batt]
  LC Filter reference/1(Uabc) -> [Uabc]
  [Qinst] -> 变流器PQ控制(电压环)/4(Qinst)
  参考信号生成/1(Ua_ref) -> SPWM控制/1(a)
  [Vq_Batt] -> 变流器VF控制(电压环)/2(Vq_Batt)
  参考信号生成/3(Uc_ref) -> SPWM控制/3(c)
  变流器PQ控制(电压环)/1(Id_PQref) -> 变流器PQ-VF控制Iref切换/1(Id_PQref)
  [Theta_Bat] -> 参考信号生成/4(Theta_Park)
  变流器PQ-VF控制theta变换/1(theta_Bat) -> [Theta_Bat], 电网电压定向，坐标变换 +瞬时功率计算/2(wt)
  比例变换/2(Out2) -> 电网电压定向，坐标变换 +瞬时功率计算/3(ILabc)
  [Pref] -> 变流器PQ控制(电压环)/1(Pref)
  [Qref] -> 变流器PQ控制(电压环)/3(Qref)
  [Vq_Batt] -> 变流器PQ控制(电流环)/6(Vq_Batt)
  abc to dq0_Voltage/1 -> Demux/1
  [Pinst] -> 变流器PQ控制(电压环)/2(Pinst)
  [ILq_Batt] -> 变流器VF控制(电压环)/4(ILq)
  变流器PQ控制(电流环)/2(Vq_ref) -> 参考信号生成/2(Vq_ref)
  Demux/1 -> [Id_Batt]
  电网电压定向，坐标变换 +瞬时功率计算/3(Ud) -> [Vd_Batt]
  电网电压定向，坐标变换 +瞬时功率计算/4(Uq) -> [Vq_Batt]
  电网电压定向，坐标变换 +瞬时功率计算/1(Pinst) -> [Pinst], Scope1/1
  [Vd_Batt] -> 变流器VF控制(电压环)/1(Vd_Batt)
  电网电压定向，坐标变换 +瞬时功率计算/5(ILd) -> [ILd_Batt]
  PLL/2(freq) -> [Frequency]
  变流器VF控制(电压环)/2(Iq_VFref) -> 变流器PQ-VF控制Iref切换/5(Iq_VFref)
  参考信号生成/2(Ub_ref) -> SPWM控制/2(b)
  变流器PQ-VF控制Iref切换/1(Idref) -> 变流器PQ控制(电流环)/2(Id_ref)
  SPWM控制/1(g) -> [g]
  Gain1/1 -> Integrator/1
  Gain2/1 -> Switch/2, SOC/1
  Product/1 -> Gain1/1
  Gain3/1 -> Gain2/1
  Integrator/1 -> RemainCap/1, Gain3/1
  Voltage Measurement/1 -> Product/2, Gain/1
  Current Measurement1/1 -> Product/1
  [g] -> Switch/1
  Constant/1 -> Switch/3
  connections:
  LC Filter reference/RConn2 -- b/RConn1
  LC Filter reference/RConn3 -- c/RConn1
  LC Filter reference/RConn1 -- a/RConn1
  Three-Phase V-I Measurement/RConn3 -- LC Filter reference/LConn3
  Three-Phase V-I Measurement/LConn3 -- Universal Bridge/LConn3
  Three-Phase V-I Measurement/RConn1 -- LC Filter reference/LConn1
  Three-Phase V-I Measurement/RConn2 -- LC Filter reference/LConn2
  Current Measurement1/LConn1 -- Universal Bridge/RConn1
  Three-Phase V-I Measurement/LConn1 -- Universal Bridge/LConn1
  Universal Bridge/LConn2 -- Three-Phase V-I Measurement/LConn2
  3000V/LConn1 -- Voltage Measurement/LConn2 -- Universal Bridge/RConn2
  Voltage Measurement/LConn1 -- Current Measurement1/RConn1 -- 3000V/RConn1

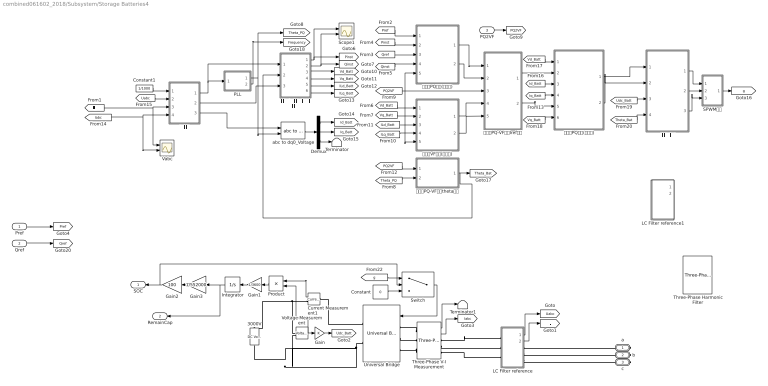
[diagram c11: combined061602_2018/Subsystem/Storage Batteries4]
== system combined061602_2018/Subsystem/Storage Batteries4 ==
  Pref : Inport
  Qref : Inport  Port=2
  PQ2VF : Inport  Port=3
  3000V : powerlib/Electrical Sources/DC Voltage Source  Amplitude=3000  Measurements=None
  Constant : Constant  Value=0
  Constant1 : Constant  Value=1/1000
  Current Measurement1 : powerlib/Measurements/Current Measurement  PhasorSimulation=off  OutputType=Complex  PSBequivalent=0
  Demux : Demux  Outputs=3
  Gain : Gain
  Gain1 : Gain  Gain=1/3600
  Gain2 : Gain  Gain=100
  Gain3 : Gain  Gain=1/552000
  Integrator : Integrator  InitialCondition=552000*0.5  LimitOutput=on  UpperSaturationLimit=552000  LowerSaturationLimit=0
  LC Filter reference : Subsystem
  LC Filter reference1 : Subsystem  Commented=on
  PLL : Subsystem
  Product : Product
  SPWM控制 : Subsystem
  Scope1 : Scope  NumInputPorts=2
  Switch : Switch  Criteria=u2 > Threshold  Threshold=5
  Terminator : Terminator
  Terminator1 : Terminator
  Three-Phase Harmonic Filter : powerlib/Elements/Three-Phase Harmonic Filter  Commented=on  LConnTagsString=A|B|C  FilterType=Double-tuned  FilterConnection=Y (grounded)  ParNom=[400 50]  Qc=1000  Fr=[5*60]  Frd=[5*50 7*50]  Q=16  Measurements=None
  Three-Phase V-I Measurement : powerlib/Measurements/Three-Phase V-I Measurement  VoltageMeasurement=phase-to-ground  SetLabelV=off  LabelV=Vabc  Vpu=off  VpuLL=off  CurrentMeasurement=yes  SetLabelI=off  LabelI=Iabc  Ipu=off  Pbase=100e6  Vbase=500e3  OutputType=Complex  PhasorSimulation=off  PSBequivalent=0
  Universal Bridge : powerlib/Power Electronics/Universal Bridge  Arms=3  SnubberResistance=100000000  SnubberCapacitance=inf  Device=IGBT / Diodes  Ron=5e-3  Lon=0  ForwardVoltages="[  0  0  ]"  ForwardVoltage=0  GTOparameters=[ 10e-6 , 20e-6 ]  IGBTparameters=[ 1e-6 , 2e-6 ]  Measurements=None  Measurements_2=None  converterType=Rectifier
  Vabc : Scope  NumInputPorts=2
  Voltage Measurement : powerlib/Measurements/Voltage Measurement  PhasorSimulation=off  OutputType=Complex  PSBequivalent=0
  abc to dq0_Voltage : powerlib_meascontrol/Transformations/abc to dq0  Alignment=90 degrees behind phase A axis
  参考信号生成 : Subsystem
  变流器PQ-VF控制Iref切换 : Subsystem
  变流器PQ-VF控制theta变换 : Subsystem
  变流器PQ控制(电压环) : Subsystem
  变流器PQ控制(电流环) : Subsystem
  变流器VF控制(电压环) : Subsystem
  比例变换 : Subsystem
  电网电压定向，坐标变换 +瞬时功率计算 : Subsystem
  a : PMIOPort  Side=Right
  b : PMIOPort  Port=2  Side=Right
  c : PMIOPort  Port=3  Side=Right
  SOC : Outport
  RemainCap : Outport  Port=2
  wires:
  Constant/1 -> Switch/3
  [g] -> Switch/1
  Current Measurement1/1 -> Product/1
  Voltage Measurement/1 -> Gain/1, Product/2
  Integrator/1 -> Gain3/1, RemainCap/1
  Gain3/1 -> Gain2/1
  Product/1 -> Gain1/1
  Gain2/1 -> SOC/1, Switch/2
  Gain1/1 -> Integrator/1
  SPWM控制/1(g) -> [g]
  变流器PQ-VF控制Iref切换/1(Idref) -> 变流器PQ控制(电流环)/2(Id_ref)
  参考信号生成/2(Ub_ref) -> SPWM控制/2(b)
  变流器VF控制(电压环)/2(Iq_VFref) -> 变流器PQ-VF控制Iref切换/5(Iq_VFref)
  PLL/2(freq) -> [Frequency]
  电网电压定向，坐标变换 +瞬时功率计算/5(ILd) -> [ILd_Batt]
  [Vd_Batt] -> 变流器VF控制(电压环)/1(Vd_Batt)
  电网电压定向，坐标变换 +瞬时功率计算/1(Pinst) -> Scope1/1, [Pinst]
  电网电压定向，坐标变换 +瞬时功率计算/4(Uq) -> [Vq_Batt]
  电网电压定向，坐标变换 +瞬时功率计算/3(Ud) -> [Vd_Batt]
  Demux/1 -> [Id_Batt]
  变流器PQ控制(电流环)/2(Vq_ref) -> 参考信号生成/2(Vq_ref)
  [ILq_Batt] -> 变流器VF控制(电压环)/4(ILq)
  [Pinst] -> 变流器PQ控制(电压环)/2(Pinst)
  abc to dq0_Voltage/1 -> Demux/1
  [Vq_Batt] -> 变流器PQ控制(电流环)/6(Vq_Batt)
  [Qref] -> 变流器PQ控制(电压环)/3(Qref)
  [Pref] -> 变流器PQ控制(电压环)/1(Pref)
  比例变换/2(Out2) -> 电网电压定向，坐标变换 +瞬时功率计算/3(ILabc)
  变流器PQ-VF控制theta变换/1(theta_Bat) -> 电网电压定向，坐标变换 +瞬时功率计算/2(wt), [Theta_Bat]
  [Theta_Bat] -> 参考信号生成/4(Theta_Park)
  变流器PQ控制(电压环)/1(Id_PQref) -> 变流器PQ-VF控制Iref切换/1(Id_PQref)
  参考信号生成/3(Uc_ref) -> SPWM控制/3(c)
  [Vq_Batt] -> 变流器VF控制(电压环)/2(Vq_Batt)
  参考信号生成/1(Ua_ref) -> SPWM控制/1(a)
  [Qinst] -> 变流器PQ控制(电压环)/4(Qinst)
  LC Filter reference/1(Uabc) -> [Uabc]
  Gain/1 -> [Udc_Batt]
  变流器PQ控制(电流环)/1(Vd_ref) -> 参考信号生成/1(Vd_ref)
  Switch/1 -> Universal Bridge/1
  Demux/2 -> [Iq_Batt]
  [IL] -> Vabc/1, 比例变换/3(In2)
  Demux/3 -> Terminator/1
  比例变换/1(Out1) -> 电网电压定向，坐标变换 +瞬时功率计算/1(Uabc), PLL/1(Uabc)
  [ILd_Batt] -> 变流器VF控制(电压环)/3(ILd)
  变流器PQ-VF控制Iref切换/2(Iqref) -> 变流器PQ控制(电流环)/5(Iq_ref)
  [Uabc] -> 比例变换/2(In1)
  [PQ2VF] -> 变流器PQ控制(电压环)/5(PQ2VF), 变流器VF控制(电压环)/5(PQ2VF), 变流器PQ-VF控制Iref切换/3(PQ2VF)
  变流器VF控制(电压环)/1(Id_VFref) -> 变流器PQ-VF控制Iref切换/4(Id_VFref)
  PLL/1(wt) -> abc to dq0_Voltage/2, [Theta_PQ]
  [Udc_Batt] -> 参考信号生成/3(Vdc_Batt)
  LC Filter reference/2(ILabc) -> [IL]
  变流器PQ控制(电压环)/2(Iq_PQref) -> 变流器PQ-VF控制Iref切换/2(Iq_PQref)
  [Vd_Batt] -> 变流器PQ控制(电流环)/1(Vd_Batt)
  [Theta_PQ] -> 变流器PQ-VF控制theta变换/2(theta_PQref)
  电网电压定向，坐标变换 +瞬时功率计算/2(Qinst) -> Scope1/2, [Qinst]
  Three-Phase V-I Measurement/2 -> [Iabc]
  [PQ2VF] -> 变流器PQ-VF控制theta变换/1(PQ2VF)
  电网电压定向，坐标变换 +瞬时功率计算/6(ILq) -> [ILq_Batt]
  Constant1/1 -> 比例变换/1(proportion)
  Three-Phase V-I Measurement/1 -> Terminator1/1
  Pref/1 -> [Pref]
  Qref/1 -> [Qref]
  PQ2VF/1 -> [PQ2VF]
  [Iabc] -> Vabc/2, 比例变换/4(In3)
  比例变换/3(Out3) -> abc to dq0_Voltage/1
  [Id_Batt] -> 变流器PQ控制(电流环)/3(Id_Batt)
  [Iq_Batt] -> 变流器PQ控制(电流环)/4(Iq_Batt)
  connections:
  Current Measurement1/RConn1 -- 3000V/RConn1 -- Voltage Measurement/LConn1
  Universal Bridge/RConn2 -- Voltage Measurement/LConn2 -- 3000V/LConn1
  Universal Bridge/LConn2 -- Three-Phase V-I Measurement/LConn2
  Three-Phase V-I Measurement/LConn1 -- Universal Bridge/LConn1
  Current Measurement1/LConn1 -- Universal Bridge/RConn1
  Three-Phase V-I Measurement/RConn2 -- LC Filter reference/LConn2
  Three-Phase V-I Measurement/RConn1 -- LC Filter reference/LConn1
  Three-Phase V-I Measurement/LConn3 -- Universal Bridge/LConn3
  Three-Phase V-I Measurement/RConn3 -- LC Filter reference/LConn3
  LC Filter reference/RConn1 -- a/RConn1
  LC Filter reference/RConn3 -- c/RConn1
  LC Filter reference/RConn2 -- b/RConn1

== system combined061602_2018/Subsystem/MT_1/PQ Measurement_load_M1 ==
  Vabc : Inport
  Iabc : Inport  Port=2
  Power : powerlib_meascontrol/Measurements/Power  Freq=50  Vinit=[1, 0]  Iinit=[1, 0]  Ts=0
  Sum of Elements : Sum  Inputs=+
  Sum of Elements1 : Sum  Inputs=+
  P : Outport
  Q : Outport  Port=2
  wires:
  Power/2 -> Sum of Elements1/1
  Sum of Elements1/1 -> Q/1
  Sum of Elements/1 -> P/1
  Iabc/1 -> Power/2
  Vabc/1 -> Power/1
  Power/1 -> Sum of Elements/1

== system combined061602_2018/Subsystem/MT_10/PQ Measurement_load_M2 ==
  Vabc : Inport
  Iabc : Inport  Port=2
  Power : powerlib_meascontrol/Measurements/Power  Freq=50  Vinit=[1, 0]  Iinit=[1, 0]  Ts=0
  Sum of Elements : Sum  Inputs=+
  Sum of Elements1 : Sum  Inputs=+
  P : Outport
  Q : Outport  Port=2
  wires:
  Power/2 -> Sum of Elements1/1
  Sum of Elements1/1 -> Q/1
  Sum of Elements/1 -> P/1
  Iabc/1 -> Power/2
  Vabc/1 -> Power/1
  Power/1 -> Sum of Elements/1

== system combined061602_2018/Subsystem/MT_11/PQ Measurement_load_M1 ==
  Vabc : Inport
  Iabc : Inport  Port=2
  Power : powerlib_meascontrol/Measurements/Power  Freq=50  Vinit=[1, 0]  Iinit=[1, 0]  Ts=0
  Sum of Elements : Sum  Inputs=+
  Sum of Elements1 : Sum  Inputs=+
  P : Outport
  Q : Outport  Port=2
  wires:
  Power/1 -> Sum of Elements/1
  Vabc/1 -> Power/1
  Iabc/1 -> Power/2
  Sum of Elements/1 -> P/1
  Sum of Elements1/1 -> Q/1
  Power/2 -> Sum of Elements1/1

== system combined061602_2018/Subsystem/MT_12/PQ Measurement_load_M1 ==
  Vabc : Inport
  Iabc : Inport  Port=2
  Power : powerlib_meascontrol/Measurements/Power  Freq=50  Vinit=[1, 0]  Iinit=[1, 0]  Ts=0
  Sum of Elements : Sum  Inputs=+
  Sum of Elements1 : Sum  Inputs=+
  P : Outport
  Q : Outport  Port=2
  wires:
  Power/2 -> Sum of Elements1/1
  Sum of Elements1/1 -> Q/1
  Sum of Elements/1 -> P/1
  Iabc/1 -> Power/2
  Vabc/1 -> Power/1
  Power/1 -> Sum of Elements/1

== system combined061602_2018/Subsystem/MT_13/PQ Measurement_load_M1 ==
  Vabc : Inport
  Iabc : Inport  Port=2
  Power : powerlib_meascontrol/Measurements/Power  Freq=50  Vinit=[1, 0]  Iinit=[1, 0]  Ts=0
  Sum of Elements : Sum  Inputs=+
  Sum of Elements1 : Sum  Inputs=+
  P : Outport
  Q : Outport  Port=2
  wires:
  Power/1 -> Sum of Elements/1
  Vabc/1 -> Power/1
  Iabc/1 -> Power/2
  Sum of Elements/1 -> P/1
  Sum of Elements1/1 -> Q/1
  Power/2 -> Sum of Elements1/1

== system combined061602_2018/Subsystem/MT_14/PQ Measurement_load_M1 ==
  Vabc : Inport
  Iabc : Inport  Port=2
  Power : powerlib_meascontrol/Measurements/Power  Freq=50  Vinit=[1, 0]  Iinit=[1, 0]  Ts=0
  Sum of Elements : Sum  Inputs=+
  Sum of Elements1 : Sum  Inputs=+
  P : Outport
  Q : Outport  Port=2
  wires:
  Power/2 -> Sum of Elements1/1
  Sum of Elements1/1 -> Q/1
  Sum of Elements/1 -> P/1
  Iabc/1 -> Power/2
  Vabc/1 -> Power/1
  Power/1 -> Sum of Elements/1

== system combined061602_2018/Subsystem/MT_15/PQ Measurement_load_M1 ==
  Vabc : Inport
  Iabc : Inport  Port=2
  Power : powerlib_meascontrol/Measurements/Power  Freq=50  Vinit=[1, 0]  Iinit=[1, 0]  Ts=0
  Sum of Elements : Sum  Inputs=+
  Sum of Elements1 : Sum  Inputs=+
  P : Outport
  Q : Outport  Port=2
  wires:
  Power/1 -> Sum of Elements/1
  Vabc/1 -> Power/1
  Iabc/1 -> Power/2
  Sum of Elements/1 -> P/1
  Sum of Elements1/1 -> Q/1
  Power/2 -> Sum of Elements1/1

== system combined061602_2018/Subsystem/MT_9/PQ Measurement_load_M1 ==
  Vabc : Inport
  Iabc : Inport  Port=2
  Power : powerlib_meascontrol/Measurements/Power  Freq=50  Vinit=[1, 0]  Iinit=[1, 0]  Ts=0
  Sum of Elements : Sum  Inputs=+
  Sum of Elements1 : Sum  Inputs=+
  P : Outport
  Q : Outport  Port=2
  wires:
  Power/1 -> Sum of Elements/1
  Vabc/1 -> Power/1
  Iabc/1 -> Power/2
  Sum of Elements/1 -> P/1
  Sum of Elements1/1 -> Q/1
  Power/2 -> Sum of Elements1/1

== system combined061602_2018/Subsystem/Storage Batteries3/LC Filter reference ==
  Current Measurement : powerlib/Measurements/Current Measurement  PhasorSimulation=off  OutputType=Complex  PSBequivalent=0
  Current Measurement1 : powerlib/Measurements/Current Measurement  PhasorSimulation=off  OutputType=Complex  PSBequivalent=0
  Current Measurement2 : powerlib/Measurements/Current Measurement  PhasorSimulation=off  OutputType=Complex  PSBequivalent=0
  Ground : powerlib/Elements/Ground  LConnTagsString=a
  Ground1 : powerlib/Elements/Ground  LConnTagsString=a
  Ground2 : powerlib/Elements/Ground  LConnTagsString=a
  Mux : Mux  Inputs=3
  Mux1 : Mux  Inputs=3
  Series RLC Branch : powerlib/Elements/Series RLC Branch  LConnTagsString=__new0  RConnTagsString=__new0  BranchType=L  Resistance=1  Inductance=1.5e-3  SetiL0=off  InitialCurrent=0  Capacitance=1e-6  Setx0=off  InitialVoltage=0  Measurements=None
  Series RLC Branch1 : powerlib/Elements/Series RLC Branch  LConnTagsString=__new0  RConnTagsString=__new0  BranchType=C  Resistance=1  Inductance=1e-3  SetiL0=off  InitialCurrent=0  Capacitance=5500e-6  Setx0=off  InitialVoltage=0  Measurements=None
  Series RLC Branch3 : powerlib/Elements/Series RLC Branch  LConnTagsString=__new0  RConnTagsString=__new0  BranchType=L  Resistance=1  Inductance=1.5e-3  SetiL0=off  InitialCurrent=0  Capacitance=1e-6  Setx0=off  InitialVoltage=0  Measurements=None
  Series RLC Branch4 : powerlib/Elements/Series RLC Branch  LConnTagsString=__new0  RConnTagsString=__new0  BranchType=C  Resistance=1  Inductance=1e-3  SetiL0=off  InitialCurrent=0  Capacitance=5500e-6  Setx0=off  InitialVoltage=0  Measurements=None
  Series RLC Branch6 : powerlib/Elements/Series RLC Branch  LConnTagsString=__new0  RConnTagsString=__new0  BranchType=L  Resistance=1  Inductance=1.5e-3  SetiL0=off  InitialCurrent=0  Capacitance=1e-6  Setx0=off  InitialVoltage=0  Measurements=None
  Series RLC Branch7 : powerlib/Elements/Series RLC Branch  LConnTagsString=__new0  RConnTagsString=__new0  BranchType=C  Resistance=1  Inductance=1e-3  SetiL0=off  InitialCurrent=0  Capacitance=5500e-6  Setx0=off  InitialVoltage=0  Measurements=None
  Voltage Measurement : powerlib/Measurements/Voltage Measurement  PhasorSimulation=off  OutputType=Complex  PSBequivalent=0
  Voltage Measurement1 : powerlib/Measurements/Voltage Measurement  PhasorSimulation=off  OutputType=Complex  PSBequivalent=0
  Voltage Measurement2 : powerlib/Measurements/Voltage Measurement  PhasorSimulation=off  OutputType=Complex  PSBequivalent=0
  A : PMIOPort  Side=Left
  a : PMIOPort  Port=2  Side=Right
  B : PMIOPort  Port=3  Side=Left
  b : PMIOPort  Port=4  Side=Right
  C : PMIOPort  Port=5  Side=Left
  c : PMIOPort  Port=6  Side=Right
  Uabc : Outport
  ILabc : Outport  Port=2
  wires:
  Current Measurement/1 -> Mux1/3
  Current Measurement1/1 -> Mux1/2
  Current Measurement2/1 -> Mux1/1
  Mux1/1 -> ILabc/1
  Mux/1 -> Uabc/1
  Voltage Measurement/1 -> Mux/3
  Voltage Measurement1/1 -> Mux/1
  Voltage Measurement2/1 -> Mux/2
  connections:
  Current Measurement2/RConn1 -- a/RConn1
  c/RConn1 -- Current Measurement/RConn1
  Current Measurement1/RConn1 -- b/RConn1
  Series RLC Branch1/LConn1 -- Voltage Measurement1/LConn1 -- Current Measurement2/LConn1 -- Series RLC Branch/RConn1
  Series RLC Branch4/LConn1 -- Current Measurement1/LConn1 -- Voltage Measurement2/LConn1 -- Series RLC Branch3/RConn1
  Series RLC Branch1/RConn1 -- Voltage Measurement1/LConn2 -- Ground/LConn1
  Series RLC Branch7/RConn1 -- Voltage Measurement/LConn2 -- Ground2/LConn1
  Series RLC Branch7/LConn1 -- Voltage Measurement/LConn1 -- Current Measurement/LConn1 -- Series RLC Branch6/RConn1
  Series RLC Branch4/RConn1 -- Voltage Measurement2/LConn2 -- Ground1/LConn1
  Series RLC Branch/LConn1 -- A/RConn1
  Series RLC Branch6/LConn1 -- C/RConn1
  Series RLC Branch3/LConn1 -- B/RConn1

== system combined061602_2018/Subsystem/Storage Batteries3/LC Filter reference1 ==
  Current Measurement : powerlib/Measurements/Current Measurement  PhasorSimulation=off  OutputType=Complex  PSBequivalent=0
  Current Measurement1 : powerlib/Measurements/Current Measurement  PhasorSimulation=off  OutputType=Complex  PSBequivalent=0
  Current Measurement2 : powerlib/Measurements/Current Measurement  PhasorSimulation=off  OutputType=Complex  PSBequivalent=0
  Ground : powerlib/Elements/Ground  LConnTagsString=a
  Ground1 : powerlib/Elements/Ground  LConnTagsString=a
  Ground2 : powerlib/Elements/Ground  LConnTagsString=a
  Mux : Mux  Inputs=3
  Mux1 : Mux  Inputs=3
  Series RLC Branch : powerlib/Elements/Series RLC Branch  LConnTagsString=__new0  RConnTagsString=__new0  BranchType=L  Resistance=1  Inductance=0.2e-3  SetiL0=off  InitialCurrent=0  Capacitance=1e-6  Setx0=off  InitialVoltage=0  Measurements=None
  Series RLC Branch1 : powerlib/Elements/Series RLC Branch  LConnTagsString=__new0  RConnTagsString=__new0  BranchType=C  Resistance=1  Inductance=1e-3  SetiL0=off  InitialCurrent=0  Capacitance=200e-6  Setx0=off  InitialVoltage=0  Measurements=None
  Series RLC Branch3 : powerlib/Elements/Series RLC Branch  LConnTagsString=__new0  RConnTagsString=__new0  BranchType=L  Resistance=1  Inductance=0.2e-3  SetiL0=off  InitialCurrent=0  Capacitance=1e-6  Setx0=off  InitialVoltage=0  Measurements=None
  Series RLC Branch4 : powerlib/Elements/Series RLC Branch  LConnTagsString=__new0  RConnTagsString=__new0  BranchType=C  Resistance=1  Inductance=1e-3  SetiL0=off  InitialCurrent=0  Capacitance=200e-6  Setx0=off  InitialVoltage=0  Measurements=None
  Series RLC Branch6 : powerlib/Elements/Series RLC Branch  LConnTagsString=__new0  RConnTagsString=__new0  BranchType=L  Resistance=1  Inductance=0.2e-3  SetiL0=off  InitialCurrent=0  Capacitance=1e-6  Setx0=off  InitialVoltage=0  Measurements=None
  Series RLC Branch7 : powerlib/Elements/Series RLC Branch  LConnTagsString=__new0  RConnTagsString=__new0  BranchType=C  Resistance=1  Inductance=1e-3  SetiL0=off  InitialCurrent=0  Capacitance=200e-6  Setx0=off  InitialVoltage=0  Measurements=None
  Voltage Measurement : powerlib/Measurements/Voltage Measurement  PhasorSimulation=off  OutputType=Complex  PSBequivalent=0
  Voltage Measurement1 : powerlib/Measurements/Voltage Measurement  PhasorSimulation=off  OutputType=Complex  PSBequivalent=0
  Voltage Measurement2 : powerlib/Measurements/Voltage Measurement  PhasorSimulation=off  OutputType=Complex  PSBequivalent=0
  A : PMIOPort  Side=Left
  a : PMIOPort  Port=2  Side=Right
  B : PMIOPort  Port=3  Side=Left
  b : PMIOPort  Port=4  Side=Right
  C : PMIOPort  Port=5  Side=Left
  c : PMIOPort  Port=6  Side=Right
  Uabc : Outport
  ILabc : Outport  Port=2
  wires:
  Current Measurement/1 -> Mux1/3
  Current Measurement1/1 -> Mux1/2
  Current Measurement2/1 -> Mux1/1
  Mux1/1 -> ILabc/1
  Mux/1 -> Uabc/1
  Voltage Measurement/1 -> Mux/3
  Voltage Measurement1/1 -> Mux/1
  Voltage Measurement2/1 -> Mux/2
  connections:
  Current Measurement2/RConn1 -- a/RConn1
  c/RConn1 -- Current Measurement/RConn1
  Current Measurement1/RConn1 -- b/RConn1
  Series RLC Branch1/LConn1 -- Voltage Measurement1/LConn1 -- Current Measurement2/LConn1 -- Series RLC Branch/RConn1
  Series RLC Branch4/LConn1 -- Current Measurement1/LConn1 -- Voltage Measurement2/LConn1 -- Series RLC Branch3/RConn1
  Series RLC Branch1/RConn1 -- Voltage Measurement1/LConn2 -- Ground/LConn1
  Series RLC Branch7/RConn1 -- Voltage Measurement/LConn2 -- Ground2/LConn1
  Series RLC Branch7/LConn1 -- Voltage Measurement/LConn1 -- Current Measurement/LConn1 -- Series RLC Branch6/RConn1
  Series RLC Branch4/RConn1 -- Voltage Measurement2/LConn2 -- Ground1/LConn1
  Series RLC Branch/LConn1 -- A/RConn1
  Series RLC Branch6/LConn1 -- C/RConn1
  Series RLC Branch3/LConn1 -- B/RConn1

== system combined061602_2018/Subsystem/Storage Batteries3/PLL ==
  Uabc : Inport
  Demux1 : Demux  Outputs=3
  PLL1 : powerlib_meascontrol/PLL/PLL  Fmin=45  Par_Init=[0, 50]  ParK=[180, 3200, 1]  TcD=1e-4  MaxRateChangeFreq=100  FilterCutOffFreq=25  Ts=0  AGC=on
  PLL_Parameter : powerlib_meascontrol/PLL/PLL  Fmin=45  Par_Init=[0, 50]  ParK=[50, 900, 0]  TcD=1e-4  MaxRateChangeFreq=12  FilterCutOffFreq=25  Ts=0  AGC=on
  Scope2 : Scope  NumInputPorts=2
  wt : Outport
  freq : Outport  Port=2
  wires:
  PLL1/1 -> freq/1, Scope2/1
  PLL1/2 -> wt/1, Scope2/2
  Demux1/1 -> PLL1/1
  Uabc/1 -> Demux1/1

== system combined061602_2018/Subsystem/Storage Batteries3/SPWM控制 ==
  a : Inport
  b : Inport  Port=2
  c : Inport  Port=3
  Logical Operator : Logic  Operator=NOT  AllPortsSameDT=off  OutDataTypeStr=boolean
  Logical Operator1 : Logic  Operator=NOT  AllPortsSameDT=off  OutDataTypeStr=boolean
  Logical Operator2 : Logic  Operator=NOT  AllPortsSameDT=off  OutDataTypeStr=boolean
  Mux1 : Mux  Inputs=6
  Relational Operator : RelationalOperator  OutDataTypeStr=boolean
  Relational Operator1 : RelationalOperator  OutDataTypeStr=boolean
  Relational Operator2 : RelationalOperator  OutDataTypeStr=boolean
  Triangle Generator : powerlib_meascontrol/Pulse & Signal Generators/Triangle Generator  Freq=5000  Phase=180  Ts=0
  g : Outport
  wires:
  a/1 -> Relational Operator/1
  b/1 -> Relational Operator1/1
  Logical Operator2/1 -> Mux1/6
  c/1 -> Relational Operator2/1
  Logical Operator1/1 -> Mux1/4
  Relational Operator2/1 -> Logical Operator2/1, Mux1/5
  Triangle Generator/1 -> Relational Operator/2, Relational Operator2/2, Relational Operator1/2
  Relational Operator/1 -> Mux1/1, Logical Operator/1
  Logical Operator/1 -> Mux1/2
  Mux1/1 -> g/1
  Relational Operator1/1 -> Mux1/3, Logical Operator1/1

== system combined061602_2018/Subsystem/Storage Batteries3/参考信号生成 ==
  Vd_ref : Inport
  Vq_ref : Inport  Port=2
  Vdc_Batt : Inport  Port=3
  Theta_Park : Inport  Port=4
  Constant : Constant  Value=0
  Constant1 : Constant  Value=350
  Demux1 : Demux  Outputs=3
  Divide : Product  Inputs=*/
  Divide1 : Product  Inputs=*/
  Gain : Gain  Gain=1/1000
  Gain6 : Gain  Gain=2
  Gain7 : Gain  Gain=2
  Mux : Mux  Inputs=3
  Switch1 : Switch  Criteria=u2 ~= 0
  dq0 to abc : powerlib_meascontrol/Transformations/dq0 to abc  Alignment=90 degrees behind phase A axis
  Ua_ref : Outport
  Ub_ref : Outport  Port=2
  Uc_ref : Outport  Port=3
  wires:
  Constant1/1 -> Switch1/3
  Switch1/1 -> Divide1/2, Divide/2
  Gain/1 -> Switch1/2, Switch1/1
  Demux1/1 -> Ua_ref/1
  Demux1/3 -> Uc_ref/1
  Vq_ref/1 -> Gain7/1
  Demux1/2 -> Ub_ref/1
  dq0 to abc/1 -> Demux1/1
  Constant/1 -> Mux/3
  Divide/1 -> Mux/1
  Gain6/1 -> Divide/1
  Vdc_Batt/1 -> Gain/1
  Gain7/1 -> Divide1/1
  Theta_Park/1 -> dq0 to abc/2
  Vd_ref/1 -> Gain6/1
  Divide1/1 -> Mux/2
  Mux/1 -> dq0 to abc/1

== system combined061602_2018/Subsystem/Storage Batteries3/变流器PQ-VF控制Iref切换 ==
  Id_PQref : Inport
  Iq_PQref : Inport  Port=2
  PQ2VF : Inport  Port=3
  Id_VFref : Inport  Port=4
  Iq_VFref : Inport  Port=5
  Saturation : Saturate  UpperLimit=5  LowerLimit=-5
  Saturation1 : Saturate  UpperLimit=5  LowerLimit=-5
  Switch : Switch  Criteria=u2 ~= 0
  Switch1 : Switch  Criteria=u2 ~= 0
  Idref : Outport
  Iqref : Outport  Port=2
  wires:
  Saturation1/1 -> Iqref/1
  Saturation/1 -> Idref/1
  Iq_PQref/1 -> Switch1/3
  Iq_VFref/1 -> Switch1/1
  Id_VFref/1 -> Switch/1
  Id_PQref/1 -> Switch/3
  Switch/1 -> Saturation/1
  Switch1/1 -> Saturation1/1
  PQ2VF/1 -> Switch/2, Switch1/2

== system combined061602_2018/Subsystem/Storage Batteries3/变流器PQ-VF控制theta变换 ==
  PQ2VF : Inport
  theta_PQref : Inport  Port=2
  Clock1 : Clock
  Constant3 : Constant  Value=2*pi
  Constant4 : Constant  Value=100*pi
  Constant5 : Constant  Value=0
  Mod : Math  Operator=mod
  Product1 : Product
  Sample and Hold : dspsigops/Sample and Hold  trig=Rising edge  initCond=0  latchinput=off
  Sum2 : Sum  Inputs=+|+
  Sum3 : Sum  Inputs=|+-
  Switch : Switch  Criteria=u2 ~= 0
  theta_Bat : Outport
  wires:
  Sample and Hold/1 -> Sum2/1
  Product1/1 -> Sum2/2
  Clock1/1 -> Sum3/1
  Sum3/1 -> Product1/2
  Constant5/1 -> Sum3/2
  Constant4/1 -> Product1/1
  Mod/1 -> Switch/1
  Switch/1 -> theta_Bat/1
  theta_PQref/1 -> Sample and Hold/1, Switch/3
  PQ2VF/1 -> Sample and Hold/Trigger, Switch/2
  Constant3/1 -> Mod/2
  Sum2/1 -> Mod/1

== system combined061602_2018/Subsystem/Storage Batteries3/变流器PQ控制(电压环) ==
  Pref : Inport
  Pinst : Inport  Port=2
  Qref : Inport  Port=3
  Qinst : Inport  Port=4
  PQ2VF : Inport  Port=5
  Discrete PID Controller : simulink/Continuous/PID Controller  Controller=PI  Form=Parallel  TimeDomain=Continuous-time  SampleTime=-1  IntegratorMethod=Forward Euler  FilterMethod=Forward Euler  ControllerParametersSource=internal  P=0.02  I=1/1e-3  D=0  UseFilter=on  N=100  TunerSelectOption=Transfer Function Based (PID Tuner App)  InitialConditionSource=internal  InitialConditionForIntegrator=0  InitialConditionForFilter=0  DifferentiatorICPrevScaledInput=0  ExternalReset=either  TrackingMode=off  Kt=1  LimitOutput=on  UpperSaturationLimit=13  LowerSaturationLimit=-13  LinearizeAsGain=off  AntiWindupMode=none  Kb=1  POutMin=[]  POutMax=[]  IOutMin=[]  IOutMax=[]  DOutMin=[]  DOutMax=[]  NOutMin=[]  NOutMax=[]  SumOutMin=[]  SumOutMax=[]  SaturationOutMin=[]  SaturationOutMax=[]  PParamMin=[]  PParamMax=[]  IParamMin=[]  IParamMax=[]  DParamMin=[]  DParamMax=[]  NParamMin=[]  NParamMax=[]  KbParamMin=[]  KbParamMax=[]  KtParamMin=[]  KtParamMax=[]  KbOutMin=[]  KbOutMax=[]  KtOutMin=[]  KtOutMax=[]  IntegratorOutMin=[]  IntegratorOutMax=[]  FilterOutMin=[]  FilterOutMax=[]  SumI1OutMin=[]  SumI1OutMax=[]  SumI2OutMin=[]  SumI2OutMax=[]  SumI3OutMin=[]  SumI3OutMax=[]  SumI4OutMin=[]  SumI4OutMax=[]  SumDOutMin=[]  SumDOutMax=[]  DifferentiatorOutMin=[]  DifferentiatorOutMax=[]  FilterDiffOutCoefMin=[]  FilterDiffOutCoefMax=[]  ReciprocalOutMin=[]  ReciprocalOutMax=[]  SumDenOutMin=[]  SumDenOutMax=[]  SumNumOutMin=[]  SumNumOutMax=[]  DivideOutMin=[]  DivideOutMax=[]  IntegratorContinuousStateAttributes=''  IntegratorStateMustResolveToSignalObject=off  IntegratorRTWStateStorageClass=Auto  FilterContinuousStateAttributes=''  FilterStateMustResolveToSignalObject=off  FilterRTWStateStorageClass=Auto  ParallelPVariant=InternalParameters  IdealPVariant=Disabled  IVariant=InternalParameters  DVariant=Disabled  IntegratorVariant=Continuous  SatVariant=Enabled  AWVariant=Passthrough  PCopyVariant=Disabled  TRVariant=Disabled  FdbkBlocksVariant=Forward  IdealPFdbkVariant=Disabled  SatFdbkVariant=Disabled  DerivativeFilterVariant=Disabled  NVariant=Disabled  NCopyVariant=Disabled_SignalSpec  FilterICVariant=Disabled  IntegratorICVariant=InternalICs  ExternalResetVariant=ExternalReset  TRSumVariant=Passthrough  SumFdbkVariant=Disabled  SumVariant=Sum_PI
  Discrete PID Controller1 : simulink/Continuous/PID Controller  Controller=PI  Form=Parallel  TimeDomain=Continuous-time  SampleTime=-1  IntegratorMethod=Forward Euler  FilterMethod=Forward Euler  ControllerParametersSource=internal  P=0.02  I=1/1e-3  D=0  UseFilter=on  N=100  TunerSelectOption=Transfer Function Based (PID Tuner App)  InitialConditionSource=internal  InitialConditionForIntegrator=0  InitialConditionForFilter=0  DifferentiatorICPrevScaledInput=0  ExternalReset=either  TrackingMode=off  Kt=1  LimitOutput=on  UpperSaturationLimit=13  LowerSaturationLimit=-13  LinearizeAsGain=off  AntiWindupMode=none  Kb=1  POutMin=[]  POutMax=[]  IOutMin=[]  IOutMax=[]  DOutMin=[]  DOutMax=[]  NOutMin=[]  NOutMax=[]  SumOutMin=[]  SumOutMax=[]  SaturationOutMin=[]  SaturationOutMax=[]  PParamMin=[]  PParamMax=[]  IParamMin=[]  IParamMax=[]  DParamMin=[]  DParamMax=[]  NParamMin=[]  NParamMax=[]  KbParamMin=[]  KbParamMax=[]  KtParamMin=[]  KtParamMax=[]  KbOutMin=[]  KbOutMax=[]  KtOutMin=[]  KtOutMax=[]  IntegratorOutMin=[]  IntegratorOutMax=[]  FilterOutMin=[]  FilterOutMax=[]  SumI1OutMin=[]  SumI1OutMax=[]  SumI2OutMin=[]  SumI2OutMax=[]  SumI3OutMin=[]  SumI3OutMax=[]  SumI4OutMin=[]  SumI4OutMax=[]  SumDOutMin=[]  SumDOutMax=[]  DifferentiatorOutMin=[]  DifferentiatorOutMax=[]  FilterDiffOutCoefMin=[]  FilterDiffOutCoefMax=[]  ReciprocalOutMin=[]  ReciprocalOutMax=[]  SumDenOutMin=[]  SumDenOutMax=[]  SumNumOutMin=[]  SumNumOutMax=[]  DivideOutMin=[]  DivideOutMax=[]  IntegratorContinuousStateAttributes=''  IntegratorStateMustResolveToSignalObject=off  IntegratorRTWStateStorageClass=Auto  FilterContinuousStateAttributes=''  FilterStateMustResolveToSignalObject=off  FilterRTWStateStorageClass=Auto  ParallelPVariant=InternalParameters  IdealPVariant=Disabled  IVariant=InternalParameters  DVariant=Disabled  IntegratorVariant=Continuous  SatVariant=Enabled  AWVariant=Passthrough  PCopyVariant=Disabled  TRVariant=Disabled  FdbkBlocksVariant=Forward  IdealPFdbkVariant=Disabled  SatFdbkVariant=Disabled  DerivativeFilterVariant=Disabled  NVariant=Disabled  NCopyVariant=Disabled_SignalSpec  FilterICVariant=Disabled  IntegratorICVariant=InternalICs  ExternalResetVariant=ExternalReset  TRSumVariant=Passthrough  SumFdbkVariant=Disabled  SumVariant=Sum_PI
  Gain : Gain  Gain=1e-6
  Gain2 : Gain  Gain=1e-6
  Saturation : Saturate  UpperLimit=5  LowerLimit=-5  LinearizeAsGain=off
  Saturation1 : Saturate  UpperLimit=5  LowerLimit=-5  LinearizeAsGain=off
  Scope1 : Scope  NumInputPorts=2
  Scope2 : Scope  NumInputPorts=2
  Sum : Sum  Inputs=|+-
  Sum1 : Sum  Inputs=|-+
  Id_PQref : Outport
  Iq_PQref : Outport  Port=2
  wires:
  PQ2VF/1 -> Discrete PID Controller/2, Discrete PID Controller1/2
  Discrete PID Controller/1 -> Saturation/1
  Sum/1 -> Discrete PID Controller/1
  Qinst/1 -> Sum1/2, Scope2/2
  Qref/1 -> Gain2/1
  Gain2/1 -> Sum1/1, Scope2/1
  Pinst/1 -> Sum/2
  Gain/1 -> Sum/1
  Pref/1 -> Gain/1
  Sum1/1 -> Discrete PID Controller1/1
  Discrete PID Controller1/1 -> Saturation1/1
  Saturation/1 -> Id_PQref/1, Scope1/1
  Saturation1/1 -> Iq_PQref/1, Scope1/2

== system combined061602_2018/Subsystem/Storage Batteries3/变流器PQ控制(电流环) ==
  Vd_Batt : Inport
  Id_ref : Inport  Port=2
  Id_Batt : Inport  Port=3
  Iq_Batt : Inport  Port=4
  Iq_ref : Inport  Port=5
  Vq_Batt : Inport  Port=6
  Gain : Gain  Gain=100*pi*1.5e-3
  Gain1 : Gain  Gain=100*pi*1.5e-3
  PID Controller : simulink/Continuous/PID Controller  Controller=PI  Form=Parallel  TimeDomain=Continuous-time  SampleTime=-1  IntegratorMethod=Forward Euler  FilterMethod=Forward Euler  ControllerParametersSource=internal  P=5  I=1/0.4  D=0  UseFilter=on  N=100  TunerSelectOption=Transfer Function Based (PID Tuner App)  InitialConditionSource=internal  InitialConditionForIntegrator=0  InitialConditionForFilter=0  DifferentiatorICPrevScaledInput=0  ExternalReset=none  TrackingMode=off  Kt=1  LimitOutput=off  UpperSaturationLimit=inf  LowerSaturationLimit=-inf  LinearizeAsGain=on  AntiWindupMode=none  Kb=1  POutMin=[]  POutMax=[]  IOutMin=[]  IOutMax=[]  DOutMin=[]  DOutMax=[]  NOutMin=[]  NOutMax=[]  SumOutMin=[]  SumOutMax=[]  SaturationOutMin=[]  SaturationOutMax=[]  PParamMin=[]  PParamMax=[]  IParamMin=[]  IParamMax=[]  DParamMin=[]  DParamMax=[]  NParamMin=[]  NParamMax=[]  KbParamMin=[]  KbParamMax=[]  KtParamMin=[]  KtParamMax=[]  KbOutMin=[]  KbOutMax=[]  KtOutMin=[]  KtOutMax=[]  IntegratorOutMin=[]  IntegratorOutMax=[]  FilterOutMin=[]  FilterOutMax=[]  SumI1OutMin=[]  SumI1OutMax=[]  SumI2OutMin=[]  SumI2OutMax=[]  SumI3OutMin=[]  SumI3OutMax=[]  SumI4OutMin=[]  SumI4OutMax=[]  SumDOutMin=[]  SumDOutMax=[]  DifferentiatorOutMin=[]  DifferentiatorOutMax=[]  FilterDiffOutCoefMin=[]  FilterDiffOutCoefMax=[]  ReciprocalOutMin=[]  ReciprocalOutMax=[]  SumDenOutMin=[]  SumDenOutMax=[]  SumNumOutMin=[]  SumNumOutMax=[]  DivideOutMin=[]  DivideOutMax=[]  IntegratorContinuousStateAttributes=''  IntegratorStateMustResolveToSignalObject=off  IntegratorRTWStateStorageClass=Auto  FilterContinuousStateAttributes=''  FilterStateMustResolveToSignalObject=off  FilterRTWStateStorageClass=Auto  ParallelPVariant=InternalParameters  IdealPVariant=Disabled  IVariant=InternalParameters  DVariant=Disabled  IntegratorVariant=Continuous  SatVariant=Disabled  AWVariant=Passthrough  PCopyVariant=Disabled  TRVariant=Disabled  FdbkBlocksVariant=Forward  IdealPFdbkVariant=Disabled  SatFdbkVariant=Disabled  DerivativeFilterVariant=Disabled  NVariant=Disabled  NCopyVariant=Disabled_SignalSpec  FilterICVariant=Disabled  IntegratorICVariant=InternalICs  ExternalResetVariant=Disabled  TRSumVariant=Passthrough  SumFdbkVariant=Disabled  SumVariant=Sum_PI
  PID Controller1 : simulink/Continuous/PID Controller  Controller=PI  Form=Parallel  TimeDomain=Continuous-time  SampleTime=-1  IntegratorMethod=Forward Euler  FilterMethod=Forward Euler  ControllerParametersSource=internal  P=5  I=1/0.4  D=0  UseFilter=on  N=100  TunerSelectOption=Transfer Function Based (PID Tuner App)  InitialConditionSource=internal  InitialConditionForIntegrator=0  InitialConditionForFilter=0  DifferentiatorICPrevScaledInput=0  ExternalReset=none  TrackingMode=off  Kt=1  LimitOutput=off  UpperSaturationLimit=inf  LowerSaturationLimit=-inf  LinearizeAsGain=on  AntiWindupMode=none  Kb=1  POutMin=[]  POutMax=[]  IOutMin=[]  IOutMax=[]  DOutMin=[]  DOutMax=[]  NOutMin=[]  NOutMax=[]  SumOutMin=[]  SumOutMax=[]  SaturationOutMin=[]  SaturationOutMax=[]  PParamMin=[]  PParamMax=[]  IParamMin=[]  IParamMax=[]  DParamMin=[]  DParamMax=[]  NParamMin=[]  NParamMax=[]  KbParamMin=[]  KbParamMax=[]  KtParamMin=[]  KtParamMax=[]  KbOutMin=[]  KbOutMax=[]  KtOutMin=[]  KtOutMax=[]  IntegratorOutMin=[]  IntegratorOutMax=[]  FilterOutMin=[]  FilterOutMax=[]  SumI1OutMin=[]  SumI1OutMax=[]  SumI2OutMin=[]  SumI2OutMax=[]  SumI3OutMin=[]  SumI3OutMax=[]  SumI4OutMin=[]  SumI4OutMax=[]  SumDOutMin=[]  SumDOutMax=[]  DifferentiatorOutMin=[]  DifferentiatorOutMax=[]  FilterDiffOutCoefMin=[]  FilterDiffOutCoefMax=[]  ReciprocalOutMin=[]  ReciprocalOutMax=[]  SumDenOutMin=[]  SumDenOutMax=[]  SumNumOutMin=[]  SumNumOutMax=[]  DivideOutMin=[]  DivideOutMax=[]  IntegratorContinuousStateAttributes=''  IntegratorStateMustResolveToSignalObject=off  IntegratorRTWStateStorageClass=Auto  FilterContinuousStateAttributes=''  FilterStateMustResolveToSignalObject=off  FilterRTWStateStorageClass=Auto  ParallelPVariant=InternalParameters  IdealPVariant=Disabled  IVariant=InternalParameters  DVariant=Disabled  IntegratorVariant=Continuous  SatVariant=Disabled  AWVariant=Passthrough  PCopyVariant=Disabled  TRVariant=Disabled  FdbkBlocksVariant=Forward  IdealPFdbkVariant=Disabled  SatFdbkVariant=Disabled  DerivativeFilterVariant=Disabled  NVariant=Disabled  NCopyVariant=Disabled_SignalSpec  FilterICVariant=Disabled  IntegratorICVariant=InternalICs  ExternalResetVariant=Disabled  TRSumVariant=Passthrough  SumFdbkVariant=Disabled  SumVariant=Sum_PI
  Sum : Sum  Inputs=|+-
  Sum1 : Sum  Inputs=-+|
  Sum4 : Sum  Inputs=++-
  Sum5 : Sum  Inputs=+++
  Vd_ref : Outport
  Vq_ref : Outport  Port=2
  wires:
  Sum1/1 -> PID Controller1/1
  PID Controller1/1 -> Sum5/2
  Sum/1 -> PID Controller/1
  Id_ref/1 -> Sum/1
  Iq_ref/1 -> Sum1/2
  Vq_Batt/1 -> Sum5/3
  Gain/1 -> Sum4/3
  Gain1/1 -> Sum5/1
  PID Controller/1 -> Sum4/2
  Sum5/1 -> Vq_ref/1
  Sum4/1 -> Vd_ref/1
  Id_Batt/1 -> Sum/2, Gain1/1
  Vd_Batt/1 -> Sum4/1
  Iq_Batt/1 -> Sum1/1, Gain/1
